VERSION 5.8 ;
BUSBITCHARS "[]" ;
DIVIDERCHAR "/" ;
UNITS
    DATABASE MICRONS 1000 ;
END UNITS

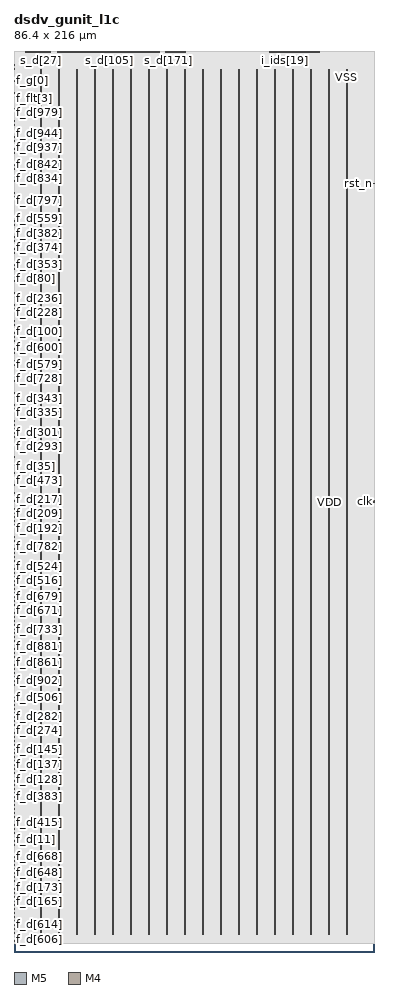
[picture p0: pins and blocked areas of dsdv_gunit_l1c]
MACRO dsdv_gunit_l1c
  FOREIGN dsdv_gunit_l1c 0 0 ;
  CLASS BLOCK ;
  SIZE 86.4 BY 216 ;
  PIN clk
    DIRECTION INPUT ;
    USE SIGNAL ;
    PORT
      LAYER M5 ;
        RECT  86.328 107.772 86.4 108.252 ;
    END
  END clk
  PIN f_d[0]
    DIRECTION INPUT ;
    USE SIGNAL ;
    PORT
      LAYER M4 ;
        RECT  0 24.912 0.084 24.936 ;
    END
  END f_d[0]
  PIN f_d[100]
    DIRECTION INPUT ;
    USE SIGNAL ;
    PORT
      LAYER M4 ;
        RECT  0 147.024 0.084 147.048 ;
    END
  END f_d[100]
  PIN f_d[101]
    DIRECTION INPUT ;
    USE SIGNAL ;
    PORT
      LAYER M4 ;
        RECT  0 147.216 0.084 147.24 ;
    END
  END f_d[101]
  PIN f_d[102]
    DIRECTION INPUT ;
    USE SIGNAL ;
    PORT
      LAYER M4 ;
        RECT  0 147.408 0.084 147.432 ;
    END
  END f_d[102]
  PIN f_d[103]
    DIRECTION INPUT ;
    USE SIGNAL ;
    PORT
      LAYER M4 ;
        RECT  0 147.6 0.084 147.624 ;
    END
  END f_d[103]
  PIN f_d[104]
    DIRECTION INPUT ;
    USE SIGNAL ;
    PORT
      LAYER M4 ;
        RECT  0 147.792 0.084 147.816 ;
    END
  END f_d[104]
  PIN f_d[105]
    DIRECTION INPUT ;
    USE SIGNAL ;
    PORT
      LAYER M4 ;
        RECT  0 147.984 0.084 148.008 ;
    END
  END f_d[105]
  PIN f_d[106]
    DIRECTION INPUT ;
    USE SIGNAL ;
    PORT
      LAYER M4 ;
        RECT  0 148.176 0.084 148.2 ;
    END
  END f_d[106]
  PIN f_d[107]
    DIRECTION INPUT ;
    USE SIGNAL ;
    PORT
      LAYER M4 ;
        RECT  0 148.368 0.084 148.392 ;
    END
  END f_d[107]
  PIN f_d[108]
    DIRECTION INPUT ;
    USE SIGNAL ;
    PORT
      LAYER M4 ;
        RECT  0 148.56 0.084 148.584 ;
    END
  END f_d[108]
  PIN f_d[109]
    DIRECTION INPUT ;
    USE SIGNAL ;
    PORT
      LAYER M4 ;
        RECT  0 148.752 0.084 148.776 ;
    END
  END f_d[109]
  PIN f_d[10]
    DIRECTION INPUT ;
    USE SIGNAL ;
    PORT
      LAYER M4 ;
        RECT  0 26.832 0.084 26.856 ;
    END
  END f_d[10]
  PIN f_d[110]
    DIRECTION INPUT ;
    USE SIGNAL ;
    PORT
      LAYER M4 ;
        RECT  0 148.944 0.084 148.968 ;
    END
  END f_d[110]
  PIN f_d[111]
    DIRECTION INPUT ;
    USE SIGNAL ;
    PORT
      LAYER M4 ;
        RECT  0 149.136 0.084 149.16 ;
    END
  END f_d[111]
  PIN f_d[112]
    DIRECTION INPUT ;
    USE SIGNAL ;
    PORT
      LAYER M4 ;
        RECT  0 149.328 0.084 149.352 ;
    END
  END f_d[112]
  PIN f_d[113]
    DIRECTION INPUT ;
    USE SIGNAL ;
    PORT
      LAYER M4 ;
        RECT  0 149.52 0.084 149.544 ;
    END
  END f_d[113]
  PIN f_d[114]
    DIRECTION INPUT ;
    USE SIGNAL ;
    PORT
      LAYER M4 ;
        RECT  0 149.712 0.084 149.736 ;
    END
  END f_d[114]
  PIN f_d[115]
    DIRECTION INPUT ;
    USE SIGNAL ;
    PORT
      LAYER M4 ;
        RECT  0 149.904 0.084 149.928 ;
    END
  END f_d[115]
  PIN f_d[116]
    DIRECTION INPUT ;
    USE SIGNAL ;
    PORT
      LAYER M4 ;
        RECT  0 150.096 0.084 150.12 ;
    END
  END f_d[116]
  PIN f_d[117]
    DIRECTION INPUT ;
    USE SIGNAL ;
    PORT
      LAYER M4 ;
        RECT  0 150.288 0.084 150.312 ;
    END
  END f_d[117]
  PIN f_d[118]
    DIRECTION INPUT ;
    USE SIGNAL ;
    PORT
      LAYER M4 ;
        RECT  0 150.48 0.084 150.504 ;
    END
  END f_d[118]
  PIN f_d[119]
    DIRECTION INPUT ;
    USE SIGNAL ;
    PORT
      LAYER M4 ;
        RECT  0 150.672 0.084 150.696 ;
    END
  END f_d[119]
  PIN f_d[11]
    DIRECTION INPUT ;
    USE SIGNAL ;
    PORT
      LAYER M4 ;
        RECT  0 27.024 0.084 27.048 ;
    END
  END f_d[11]
  PIN f_d[120]
    DIRECTION INPUT ;
    USE SIGNAL ;
    PORT
      LAYER M4 ;
        RECT  0 150.864 0.084 150.888 ;
    END
  END f_d[120]
  PIN f_d[121]
    DIRECTION INPUT ;
    USE SIGNAL ;
    PORT
      LAYER M4 ;
        RECT  0 151.056 0.084 151.08 ;
    END
  END f_d[121]
  PIN f_d[122]
    DIRECTION INPUT ;
    USE SIGNAL ;
    PORT
      LAYER M4 ;
        RECT  0 151.248 0.084 151.272 ;
    END
  END f_d[122]
  PIN f_d[123]
    DIRECTION INPUT ;
    USE SIGNAL ;
    PORT
      LAYER M4 ;
        RECT  0 151.44 0.084 151.464 ;
    END
  END f_d[123]
  PIN f_d[124]
    DIRECTION INPUT ;
    USE SIGNAL ;
    PORT
      LAYER M4 ;
        RECT  0 151.632 0.084 151.656 ;
    END
  END f_d[124]
  PIN f_d[125]
    DIRECTION INPUT ;
    USE SIGNAL ;
    PORT
      LAYER M4 ;
        RECT  0 151.824 0.084 151.848 ;
    END
  END f_d[125]
  PIN f_d[126]
    DIRECTION INPUT ;
    USE SIGNAL ;
    PORT
      LAYER M4 ;
        RECT  0 152.016 0.084 152.04 ;
    END
  END f_d[126]
  PIN f_d[127]
    DIRECTION INPUT ;
    USE SIGNAL ;
    PORT
      LAYER M4 ;
        RECT  0 152.208 0.084 152.232 ;
    END
  END f_d[127]
  PIN f_d[128]
    DIRECTION INPUT ;
    USE SIGNAL ;
    PORT
      LAYER M4 ;
        RECT  0 43.344 0.084 43.368 ;
    END
  END f_d[128]
  PIN f_d[129]
    DIRECTION INPUT ;
    USE SIGNAL ;
    PORT
      LAYER M4 ;
        RECT  0 43.536 0.084 43.56 ;
    END
  END f_d[129]
  PIN f_d[12]
    DIRECTION INPUT ;
    USE SIGNAL ;
    PORT
      LAYER M4 ;
        RECT  0 27.216 0.084 27.24 ;
    END
  END f_d[12]
  PIN f_d[130]
    DIRECTION INPUT ;
    USE SIGNAL ;
    PORT
      LAYER M4 ;
        RECT  0 43.728 0.084 43.752 ;
    END
  END f_d[130]
  PIN f_d[131]
    DIRECTION INPUT ;
    USE SIGNAL ;
    PORT
      LAYER M4 ;
        RECT  0 43.92 0.084 43.944 ;
    END
  END f_d[131]
  PIN f_d[132]
    DIRECTION INPUT ;
    USE SIGNAL ;
    PORT
      LAYER M4 ;
        RECT  0 44.112 0.084 44.136 ;
    END
  END f_d[132]
  PIN f_d[133]
    DIRECTION INPUT ;
    USE SIGNAL ;
    PORT
      LAYER M4 ;
        RECT  0 44.304 0.084 44.328 ;
    END
  END f_d[133]
  PIN f_d[134]
    DIRECTION INPUT ;
    USE SIGNAL ;
    PORT
      LAYER M4 ;
        RECT  0 44.496 0.084 44.52 ;
    END
  END f_d[134]
  PIN f_d[135]
    DIRECTION INPUT ;
    USE SIGNAL ;
    PORT
      LAYER M4 ;
        RECT  0 44.688 0.084 44.712 ;
    END
  END f_d[135]
  PIN f_d[136]
    DIRECTION INPUT ;
    USE SIGNAL ;
    PORT
      LAYER M4 ;
        RECT  0 44.88 0.084 44.904 ;
    END
  END f_d[136]
  PIN f_d[137]
    DIRECTION INPUT ;
    USE SIGNAL ;
    PORT
      LAYER M4 ;
        RECT  0 45.072 0.084 45.096 ;
    END
  END f_d[137]
  PIN f_d[138]
    DIRECTION INPUT ;
    USE SIGNAL ;
    PORT
      LAYER M4 ;
        RECT  0 45.264 0.084 45.288 ;
    END
  END f_d[138]
  PIN f_d[139]
    DIRECTION INPUT ;
    USE SIGNAL ;
    PORT
      LAYER M4 ;
        RECT  0 45.456 0.084 45.48 ;
    END
  END f_d[139]
  PIN f_d[13]
    DIRECTION INPUT ;
    USE SIGNAL ;
    PORT
      LAYER M4 ;
        RECT  0 27.408 0.084 27.432 ;
    END
  END f_d[13]
  PIN f_d[140]
    DIRECTION INPUT ;
    USE SIGNAL ;
    PORT
      LAYER M4 ;
        RECT  0 45.648 0.084 45.672 ;
    END
  END f_d[140]
  PIN f_d[141]
    DIRECTION INPUT ;
    USE SIGNAL ;
    PORT
      LAYER M4 ;
        RECT  0 45.84 0.084 45.864 ;
    END
  END f_d[141]
  PIN f_d[142]
    DIRECTION INPUT ;
    USE SIGNAL ;
    PORT
      LAYER M4 ;
        RECT  0 46.032 0.084 46.056 ;
    END
  END f_d[142]
  PIN f_d[143]
    DIRECTION INPUT ;
    USE SIGNAL ;
    PORT
      LAYER M4 ;
        RECT  0 46.224 0.084 46.248 ;
    END
  END f_d[143]
  PIN f_d[144]
    DIRECTION INPUT ;
    USE SIGNAL ;
    PORT
      LAYER M4 ;
        RECT  0 46.416 0.084 46.44 ;
    END
  END f_d[144]
  PIN f_d[145]
    DIRECTION INPUT ;
    USE SIGNAL ;
    PORT
      LAYER M4 ;
        RECT  0 46.608 0.084 46.632 ;
    END
  END f_d[145]
  PIN f_d[146]
    DIRECTION INPUT ;
    USE SIGNAL ;
    PORT
      LAYER M4 ;
        RECT  0 46.8 0.084 46.824 ;
    END
  END f_d[146]
  PIN f_d[147]
    DIRECTION INPUT ;
    USE SIGNAL ;
    PORT
      LAYER M4 ;
        RECT  0 46.992 0.084 47.016 ;
    END
  END f_d[147]
  PIN f_d[148]
    DIRECTION INPUT ;
    USE SIGNAL ;
    PORT
      LAYER M4 ;
        RECT  0 47.184 0.084 47.208 ;
    END
  END f_d[148]
  PIN f_d[149]
    DIRECTION INPUT ;
    USE SIGNAL ;
    PORT
      LAYER M4 ;
        RECT  0 47.376 0.084 47.4 ;
    END
  END f_d[149]
  PIN f_d[14]
    DIRECTION INPUT ;
    USE SIGNAL ;
    PORT
      LAYER M4 ;
        RECT  0 27.6 0.084 27.624 ;
    END
  END f_d[14]
  PIN f_d[150]
    DIRECTION INPUT ;
    USE SIGNAL ;
    PORT
      LAYER M4 ;
        RECT  0 47.568 0.084 47.592 ;
    END
  END f_d[150]
  PIN f_d[151]
    DIRECTION INPUT ;
    USE SIGNAL ;
    PORT
      LAYER M4 ;
        RECT  0 47.76 0.084 47.784 ;
    END
  END f_d[151]
  PIN f_d[152]
    DIRECTION INPUT ;
    USE SIGNAL ;
    PORT
      LAYER M4 ;
        RECT  0 47.952 0.084 47.976 ;
    END
  END f_d[152]
  PIN f_d[153]
    DIRECTION INPUT ;
    USE SIGNAL ;
    PORT
      LAYER M4 ;
        RECT  0 48.144 0.084 48.168 ;
    END
  END f_d[153]
  PIN f_d[154]
    DIRECTION INPUT ;
    USE SIGNAL ;
    PORT
      LAYER M4 ;
        RECT  0 48.336 0.084 48.36 ;
    END
  END f_d[154]
  PIN f_d[155]
    DIRECTION INPUT ;
    USE SIGNAL ;
    PORT
      LAYER M4 ;
        RECT  0 48.528 0.084 48.552 ;
    END
  END f_d[155]
  PIN f_d[156]
    DIRECTION INPUT ;
    USE SIGNAL ;
    PORT
      LAYER M4 ;
        RECT  0 48.72 0.084 48.744 ;
    END
  END f_d[156]
  PIN f_d[157]
    DIRECTION INPUT ;
    USE SIGNAL ;
    PORT
      LAYER M4 ;
        RECT  0 48.912 0.084 48.936 ;
    END
  END f_d[157]
  PIN f_d[158]
    DIRECTION INPUT ;
    USE SIGNAL ;
    PORT
      LAYER M4 ;
        RECT  0 49.104 0.084 49.128 ;
    END
  END f_d[158]
  PIN f_d[159]
    DIRECTION INPUT ;
    USE SIGNAL ;
    PORT
      LAYER M4 ;
        RECT  0 49.296 0.084 49.32 ;
    END
  END f_d[159]
  PIN f_d[15]
    DIRECTION INPUT ;
    USE SIGNAL ;
    PORT
      LAYER M4 ;
        RECT  0 27.792 0.084 27.816 ;
    END
  END f_d[15]
  PIN f_d[160]
    DIRECTION INPUT ;
    USE SIGNAL ;
    PORT
      LAYER M4 ;
        RECT  0 11.088 0.084 11.112 ;
    END
  END f_d[160]
  PIN f_d[161]
    DIRECTION INPUT ;
    USE SIGNAL ;
    PORT
      LAYER M4 ;
        RECT  0 11.28 0.084 11.304 ;
    END
  END f_d[161]
  PIN f_d[162]
    DIRECTION INPUT ;
    USE SIGNAL ;
    PORT
      LAYER M4 ;
        RECT  0 11.472 0.084 11.496 ;
    END
  END f_d[162]
  PIN f_d[163]
    DIRECTION INPUT ;
    USE SIGNAL ;
    PORT
      LAYER M4 ;
        RECT  0 11.664 0.084 11.688 ;
    END
  END f_d[163]
  PIN f_d[164]
    DIRECTION INPUT ;
    USE SIGNAL ;
    PORT
      LAYER M4 ;
        RECT  0 11.856 0.084 11.88 ;
    END
  END f_d[164]
  PIN f_d[165]
    DIRECTION INPUT ;
    USE SIGNAL ;
    PORT
      LAYER M4 ;
        RECT  0 12.048 0.084 12.072 ;
    END
  END f_d[165]
  PIN f_d[166]
    DIRECTION INPUT ;
    USE SIGNAL ;
    PORT
      LAYER M4 ;
        RECT  0 12.24 0.084 12.264 ;
    END
  END f_d[166]
  PIN f_d[167]
    DIRECTION INPUT ;
    USE SIGNAL ;
    PORT
      LAYER M4 ;
        RECT  0 12.432 0.084 12.456 ;
    END
  END f_d[167]
  PIN f_d[168]
    DIRECTION INPUT ;
    USE SIGNAL ;
    PORT
      LAYER M4 ;
        RECT  0 12.624 0.084 12.648 ;
    END
  END f_d[168]
  PIN f_d[169]
    DIRECTION INPUT ;
    USE SIGNAL ;
    PORT
      LAYER M4 ;
        RECT  0 12.816 0.084 12.84 ;
    END
  END f_d[169]
  PIN f_d[16]
    DIRECTION INPUT ;
    USE SIGNAL ;
    PORT
      LAYER M4 ;
        RECT  0 27.984 0.084 28.008 ;
    END
  END f_d[16]
  PIN f_d[170]
    DIRECTION INPUT ;
    USE SIGNAL ;
    PORT
      LAYER M4 ;
        RECT  0 13.008 0.084 13.032 ;
    END
  END f_d[170]
  PIN f_d[171]
    DIRECTION INPUT ;
    USE SIGNAL ;
    PORT
      LAYER M4 ;
        RECT  0 13.2 0.084 13.224 ;
    END
  END f_d[171]
  PIN f_d[172]
    DIRECTION INPUT ;
    USE SIGNAL ;
    PORT
      LAYER M4 ;
        RECT  0 13.392 0.084 13.416 ;
    END
  END f_d[172]
  PIN f_d[173]
    DIRECTION INPUT ;
    USE SIGNAL ;
    PORT
      LAYER M4 ;
        RECT  0 13.584 0.084 13.608 ;
    END
  END f_d[173]
  PIN f_d[174]
    DIRECTION INPUT ;
    USE SIGNAL ;
    PORT
      LAYER M4 ;
        RECT  0 13.776 0.084 13.8 ;
    END
  END f_d[174]
  PIN f_d[175]
    DIRECTION INPUT ;
    USE SIGNAL ;
    PORT
      LAYER M4 ;
        RECT  0 13.968 0.084 13.992 ;
    END
  END f_d[175]
  PIN f_d[176]
    DIRECTION INPUT ;
    USE SIGNAL ;
    PORT
      LAYER M4 ;
        RECT  0 14.16 0.084 14.184 ;
    END
  END f_d[176]
  PIN f_d[177]
    DIRECTION INPUT ;
    USE SIGNAL ;
    PORT
      LAYER M4 ;
        RECT  0 14.352 0.084 14.376 ;
    END
  END f_d[177]
  PIN f_d[178]
    DIRECTION INPUT ;
    USE SIGNAL ;
    PORT
      LAYER M4 ;
        RECT  0 14.544 0.084 14.568 ;
    END
  END f_d[178]
  PIN f_d[179]
    DIRECTION INPUT ;
    USE SIGNAL ;
    PORT
      LAYER M4 ;
        RECT  0 14.736 0.084 14.76 ;
    END
  END f_d[179]
  PIN f_d[17]
    DIRECTION INPUT ;
    USE SIGNAL ;
    PORT
      LAYER M4 ;
        RECT  0 28.176 0.084 28.2 ;
    END
  END f_d[17]
  PIN f_d[180]
    DIRECTION INPUT ;
    USE SIGNAL ;
    PORT
      LAYER M4 ;
        RECT  0 14.928 0.084 14.952 ;
    END
  END f_d[180]
  PIN f_d[181]
    DIRECTION INPUT ;
    USE SIGNAL ;
    PORT
      LAYER M4 ;
        RECT  0 15.12 0.084 15.144 ;
    END
  END f_d[181]
  PIN f_d[182]
    DIRECTION INPUT ;
    USE SIGNAL ;
    PORT
      LAYER M4 ;
        RECT  0 15.312 0.084 15.336 ;
    END
  END f_d[182]
  PIN f_d[183]
    DIRECTION INPUT ;
    USE SIGNAL ;
    PORT
      LAYER M4 ;
        RECT  0 15.504 0.084 15.528 ;
    END
  END f_d[183]
  PIN f_d[184]
    DIRECTION INPUT ;
    USE SIGNAL ;
    PORT
      LAYER M4 ;
        RECT  0 15.696 0.084 15.72 ;
    END
  END f_d[184]
  PIN f_d[185]
    DIRECTION INPUT ;
    USE SIGNAL ;
    PORT
      LAYER M4 ;
        RECT  0 15.888 0.084 15.912 ;
    END
  END f_d[185]
  PIN f_d[186]
    DIRECTION INPUT ;
    USE SIGNAL ;
    PORT
      LAYER M4 ;
        RECT  0 16.08 0.084 16.104 ;
    END
  END f_d[186]
  PIN f_d[187]
    DIRECTION INPUT ;
    USE SIGNAL ;
    PORT
      LAYER M4 ;
        RECT  0 16.272 0.084 16.296 ;
    END
  END f_d[187]
  PIN f_d[188]
    DIRECTION INPUT ;
    USE SIGNAL ;
    PORT
      LAYER M4 ;
        RECT  0 16.464 0.084 16.488 ;
    END
  END f_d[188]
  PIN f_d[189]
    DIRECTION INPUT ;
    USE SIGNAL ;
    PORT
      LAYER M4 ;
        RECT  0 16.656 0.084 16.68 ;
    END
  END f_d[189]
  PIN f_d[18]
    DIRECTION INPUT ;
    USE SIGNAL ;
    PORT
      LAYER M4 ;
        RECT  0 28.368 0.084 28.392 ;
    END
  END f_d[18]
  PIN f_d[190]
    DIRECTION INPUT ;
    USE SIGNAL ;
    PORT
      LAYER M4 ;
        RECT  0 16.848 0.084 16.872 ;
    END
  END f_d[190]
  PIN f_d[191]
    DIRECTION INPUT ;
    USE SIGNAL ;
    PORT
      LAYER M4 ;
        RECT  0 17.04 0.084 17.064 ;
    END
  END f_d[191]
  PIN f_d[192]
    DIRECTION INPUT ;
    USE SIGNAL ;
    PORT
      LAYER M4 ;
        RECT  0 101.712 0.084 101.736 ;
    END
  END f_d[192]
  PIN f_d[193]
    DIRECTION INPUT ;
    USE SIGNAL ;
    PORT
      LAYER M4 ;
        RECT  0 101.904 0.084 101.928 ;
    END
  END f_d[193]
  PIN f_d[194]
    DIRECTION INPUT ;
    USE SIGNAL ;
    PORT
      LAYER M4 ;
        RECT  0 102.096 0.084 102.12 ;
    END
  END f_d[194]
  PIN f_d[195]
    DIRECTION INPUT ;
    USE SIGNAL ;
    PORT
      LAYER M4 ;
        RECT  0 102.288 0.084 102.312 ;
    END
  END f_d[195]
  PIN f_d[196]
    DIRECTION INPUT ;
    USE SIGNAL ;
    PORT
      LAYER M4 ;
        RECT  0 102.48 0.084 102.504 ;
    END
  END f_d[196]
  PIN f_d[197]
    DIRECTION INPUT ;
    USE SIGNAL ;
    PORT
      LAYER M4 ;
        RECT  0 102.672 0.084 102.696 ;
    END
  END f_d[197]
  PIN f_d[198]
    DIRECTION INPUT ;
    USE SIGNAL ;
    PORT
      LAYER M4 ;
        RECT  0 102.864 0.084 102.888 ;
    END
  END f_d[198]
  PIN f_d[199]
    DIRECTION INPUT ;
    USE SIGNAL ;
    PORT
      LAYER M4 ;
        RECT  0 103.056 0.084 103.08 ;
    END
  END f_d[199]
  PIN f_d[19]
    DIRECTION INPUT ;
    USE SIGNAL ;
    PORT
      LAYER M4 ;
        RECT  0 28.56 0.084 28.584 ;
    END
  END f_d[19]
  PIN f_d[1]
    DIRECTION INPUT ;
    USE SIGNAL ;
    PORT
      LAYER M4 ;
        RECT  0 25.104 0.084 25.128 ;
    END
  END f_d[1]
  PIN f_d[200]
    DIRECTION INPUT ;
    USE SIGNAL ;
    PORT
      LAYER M4 ;
        RECT  0 103.248 0.084 103.272 ;
    END
  END f_d[200]
  PIN f_d[201]
    DIRECTION INPUT ;
    USE SIGNAL ;
    PORT
      LAYER M4 ;
        RECT  0 103.44 0.084 103.464 ;
    END
  END f_d[201]
  PIN f_d[202]
    DIRECTION INPUT ;
    USE SIGNAL ;
    PORT
      LAYER M4 ;
        RECT  0 103.632 0.084 103.656 ;
    END
  END f_d[202]
  PIN f_d[203]
    DIRECTION INPUT ;
    USE SIGNAL ;
    PORT
      LAYER M4 ;
        RECT  0 103.824 0.084 103.848 ;
    END
  END f_d[203]
  PIN f_d[204]
    DIRECTION INPUT ;
    USE SIGNAL ;
    PORT
      LAYER M4 ;
        RECT  0 104.016 0.084 104.04 ;
    END
  END f_d[204]
  PIN f_d[205]
    DIRECTION INPUT ;
    USE SIGNAL ;
    PORT
      LAYER M4 ;
        RECT  0 104.4 0.084 104.424 ;
    END
  END f_d[205]
  PIN f_d[206]
    DIRECTION INPUT ;
    USE SIGNAL ;
    PORT
      LAYER M4 ;
        RECT  0 104.592 0.084 104.616 ;
    END
  END f_d[206]
  PIN f_d[207]
    DIRECTION INPUT ;
    USE SIGNAL ;
    PORT
      LAYER M4 ;
        RECT  0 104.784 0.084 104.808 ;
    END
  END f_d[207]
  PIN f_d[208]
    DIRECTION INPUT ;
    USE SIGNAL ;
    PORT
      LAYER M4 ;
        RECT  0 104.976 0.084 105 ;
    END
  END f_d[208]
  PIN f_d[209]
    DIRECTION INPUT ;
    USE SIGNAL ;
    PORT
      LAYER M4 ;
        RECT  0 105.168 0.084 105.192 ;
    END
  END f_d[209]
  PIN f_d[20]
    DIRECTION INPUT ;
    USE SIGNAL ;
    PORT
      LAYER M4 ;
        RECT  0 28.752 0.084 28.776 ;
    END
  END f_d[20]
  PIN f_d[210]
    DIRECTION INPUT ;
    USE SIGNAL ;
    PORT
      LAYER M4 ;
        RECT  0 105.36 0.084 105.384 ;
    END
  END f_d[210]
  PIN f_d[211]
    DIRECTION INPUT ;
    USE SIGNAL ;
    PORT
      LAYER M4 ;
        RECT  0 105.552 0.084 105.576 ;
    END
  END f_d[211]
  PIN f_d[212]
    DIRECTION INPUT ;
    USE SIGNAL ;
    PORT
      LAYER M4 ;
        RECT  0 105.744 0.084 105.768 ;
    END
  END f_d[212]
  PIN f_d[213]
    DIRECTION INPUT ;
    USE SIGNAL ;
    PORT
      LAYER M4 ;
        RECT  0 105.936 0.084 105.96 ;
    END
  END f_d[213]
  PIN f_d[214]
    DIRECTION INPUT ;
    USE SIGNAL ;
    PORT
      LAYER M4 ;
        RECT  0 106.128 0.084 106.152 ;
    END
  END f_d[214]
  PIN f_d[215]
    DIRECTION INPUT ;
    USE SIGNAL ;
    PORT
      LAYER M4 ;
        RECT  0 106.32 0.084 106.344 ;
    END
  END f_d[215]
  PIN f_d[216]
    DIRECTION INPUT ;
    USE SIGNAL ;
    PORT
      LAYER M4 ;
        RECT  0 106.512 0.084 106.536 ;
    END
  END f_d[216]
  PIN f_d[217]
    DIRECTION INPUT ;
    USE SIGNAL ;
    PORT
      LAYER M4 ;
        RECT  0 106.704 0.084 106.728 ;
    END
  END f_d[217]
  PIN f_d[218]
    DIRECTION INPUT ;
    USE SIGNAL ;
    PORT
      LAYER M4 ;
        RECT  0 106.896 0.084 106.92 ;
    END
  END f_d[218]
  PIN f_d[219]
    DIRECTION INPUT ;
    USE SIGNAL ;
    PORT
      LAYER M4 ;
        RECT  0 107.088 0.084 107.112 ;
    END
  END f_d[219]
  PIN f_d[21]
    DIRECTION INPUT ;
    USE SIGNAL ;
    PORT
      LAYER M4 ;
        RECT  0 28.944 0.084 28.968 ;
    END
  END f_d[21]
  PIN f_d[220]
    DIRECTION INPUT ;
    USE SIGNAL ;
    PORT
      LAYER M4 ;
        RECT  0 107.28 0.084 107.304 ;
    END
  END f_d[220]
  PIN f_d[221]
    DIRECTION INPUT ;
    USE SIGNAL ;
    PORT
      LAYER M4 ;
        RECT  0 107.472 0.084 107.496 ;
    END
  END f_d[221]
  PIN f_d[222]
    DIRECTION INPUT ;
    USE SIGNAL ;
    PORT
      LAYER M4 ;
        RECT  0 107.664 0.084 107.688 ;
    END
  END f_d[222]
  PIN f_d[223]
    DIRECTION INPUT ;
    USE SIGNAL ;
    PORT
      LAYER M4 ;
        RECT  0 152.4 0.084 152.424 ;
    END
  END f_d[223]
  PIN f_d[224]
    DIRECTION INPUT ;
    USE SIGNAL ;
    PORT
      LAYER M4 ;
        RECT  0 152.592 0.084 152.616 ;
    END
  END f_d[224]
  PIN f_d[225]
    DIRECTION INPUT ;
    USE SIGNAL ;
    PORT
      LAYER M4 ;
        RECT  0 152.784 0.084 152.808 ;
    END
  END f_d[225]
  PIN f_d[226]
    DIRECTION INPUT ;
    USE SIGNAL ;
    PORT
      LAYER M4 ;
        RECT  0 152.976 0.084 153 ;
    END
  END f_d[226]
  PIN f_d[227]
    DIRECTION INPUT ;
    USE SIGNAL ;
    PORT
      LAYER M4 ;
        RECT  0 153.168 0.084 153.192 ;
    END
  END f_d[227]
  PIN f_d[228]
    DIRECTION INPUT ;
    USE SIGNAL ;
    PORT
      LAYER M4 ;
        RECT  0 153.36 0.084 153.384 ;
    END
  END f_d[228]
  PIN f_d[229]
    DIRECTION INPUT ;
    USE SIGNAL ;
    PORT
      LAYER M4 ;
        RECT  0 153.552 0.084 153.576 ;
    END
  END f_d[229]
  PIN f_d[22]
    DIRECTION INPUT ;
    USE SIGNAL ;
    PORT
      LAYER M4 ;
        RECT  0 29.136 0.084 29.16 ;
    END
  END f_d[22]
  PIN f_d[230]
    DIRECTION INPUT ;
    USE SIGNAL ;
    PORT
      LAYER M4 ;
        RECT  0 153.744 0.084 153.768 ;
    END
  END f_d[230]
  PIN f_d[231]
    DIRECTION INPUT ;
    USE SIGNAL ;
    PORT
      LAYER M4 ;
        RECT  0 153.936 0.084 153.96 ;
    END
  END f_d[231]
  PIN f_d[232]
    DIRECTION INPUT ;
    USE SIGNAL ;
    PORT
      LAYER M4 ;
        RECT  0 154.128 0.084 154.152 ;
    END
  END f_d[232]
  PIN f_d[233]
    DIRECTION INPUT ;
    USE SIGNAL ;
    PORT
      LAYER M4 ;
        RECT  0 154.32 0.084 154.344 ;
    END
  END f_d[233]
  PIN f_d[234]
    DIRECTION INPUT ;
    USE SIGNAL ;
    PORT
      LAYER M4 ;
        RECT  0 154.512 0.084 154.536 ;
    END
  END f_d[234]
  PIN f_d[235]
    DIRECTION INPUT ;
    USE SIGNAL ;
    PORT
      LAYER M4 ;
        RECT  0 154.704 0.084 154.728 ;
    END
  END f_d[235]
  PIN f_d[236]
    DIRECTION INPUT ;
    USE SIGNAL ;
    PORT
      LAYER M4 ;
        RECT  0 154.896 0.084 154.92 ;
    END
  END f_d[236]
  PIN f_d[237]
    DIRECTION INPUT ;
    USE SIGNAL ;
    PORT
      LAYER M4 ;
        RECT  0 155.088 0.084 155.112 ;
    END
  END f_d[237]
  PIN f_d[238]
    DIRECTION INPUT ;
    USE SIGNAL ;
    PORT
      LAYER M4 ;
        RECT  0 155.28 0.084 155.304 ;
    END
  END f_d[238]
  PIN f_d[239]
    DIRECTION INPUT ;
    USE SIGNAL ;
    PORT
      LAYER M4 ;
        RECT  0 155.472 0.084 155.496 ;
    END
  END f_d[239]
  PIN f_d[23]
    DIRECTION INPUT ;
    USE SIGNAL ;
    PORT
      LAYER M4 ;
        RECT  0 29.328 0.084 29.352 ;
    END
  END f_d[23]
  PIN f_d[240]
    DIRECTION INPUT ;
    USE SIGNAL ;
    PORT
      LAYER M4 ;
        RECT  0 155.664 0.084 155.688 ;
    END
  END f_d[240]
  PIN f_d[241]
    DIRECTION INPUT ;
    USE SIGNAL ;
    PORT
      LAYER M4 ;
        RECT  0 155.856 0.084 155.88 ;
    END
  END f_d[241]
  PIN f_d[242]
    DIRECTION INPUT ;
    USE SIGNAL ;
    PORT
      LAYER M4 ;
        RECT  0 156.048 0.084 156.072 ;
    END
  END f_d[242]
  PIN f_d[243]
    DIRECTION INPUT ;
    USE SIGNAL ;
    PORT
      LAYER M4 ;
        RECT  0 156.24 0.084 156.264 ;
    END
  END f_d[243]
  PIN f_d[244]
    DIRECTION INPUT ;
    USE SIGNAL ;
    PORT
      LAYER M4 ;
        RECT  0 156.432 0.084 156.456 ;
    END
  END f_d[244]
  PIN f_d[245]
    DIRECTION INPUT ;
    USE SIGNAL ;
    PORT
      LAYER M4 ;
        RECT  0 156.624 0.084 156.648 ;
    END
  END f_d[245]
  PIN f_d[246]
    DIRECTION INPUT ;
    USE SIGNAL ;
    PORT
      LAYER M4 ;
        RECT  0 156.816 0.084 156.84 ;
    END
  END f_d[246]
  PIN f_d[247]
    DIRECTION INPUT ;
    USE SIGNAL ;
    PORT
      LAYER M4 ;
        RECT  0 157.008 0.084 157.032 ;
    END
  END f_d[247]
  PIN f_d[248]
    DIRECTION INPUT ;
    USE SIGNAL ;
    PORT
      LAYER M4 ;
        RECT  0 157.2 0.084 157.224 ;
    END
  END f_d[248]
  PIN f_d[249]
    DIRECTION INPUT ;
    USE SIGNAL ;
    PORT
      LAYER M4 ;
        RECT  0 157.392 0.084 157.416 ;
    END
  END f_d[249]
  PIN f_d[24]
    DIRECTION INPUT ;
    USE SIGNAL ;
    PORT
      LAYER M4 ;
        RECT  0 29.52 0.084 29.544 ;
    END
  END f_d[24]
  PIN f_d[250]
    DIRECTION INPUT ;
    USE SIGNAL ;
    PORT
      LAYER M4 ;
        RECT  0 157.584 0.084 157.608 ;
    END
  END f_d[250]
  PIN f_d[251]
    DIRECTION INPUT ;
    USE SIGNAL ;
    PORT
      LAYER M4 ;
        RECT  0 157.776 0.084 157.8 ;
    END
  END f_d[251]
  PIN f_d[252]
    DIRECTION INPUT ;
    USE SIGNAL ;
    PORT
      LAYER M4 ;
        RECT  0 157.968 0.084 157.992 ;
    END
  END f_d[252]
  PIN f_d[253]
    DIRECTION INPUT ;
    USE SIGNAL ;
    PORT
      LAYER M4 ;
        RECT  0 158.16 0.084 158.184 ;
    END
  END f_d[253]
  PIN f_d[254]
    DIRECTION INPUT ;
    USE SIGNAL ;
    PORT
      LAYER M4 ;
        RECT  0 158.352 0.084 158.376 ;
    END
  END f_d[254]
  PIN f_d[255]
    DIRECTION INPUT ;
    USE SIGNAL ;
    PORT
      LAYER M4 ;
        RECT  0 49.488 0.084 49.512 ;
    END
  END f_d[255]
  PIN f_d[256]
    DIRECTION INPUT ;
    USE SIGNAL ;
    PORT
      LAYER M4 ;
        RECT  0 49.68 0.084 49.704 ;
    END
  END f_d[256]
  PIN f_d[257]
    DIRECTION INPUT ;
    USE SIGNAL ;
    PORT
      LAYER M4 ;
        RECT  0 49.872 0.084 49.896 ;
    END
  END f_d[257]
  PIN f_d[258]
    DIRECTION INPUT ;
    USE SIGNAL ;
    PORT
      LAYER M4 ;
        RECT  0 50.064 0.084 50.088 ;
    END
  END f_d[258]
  PIN f_d[259]
    DIRECTION INPUT ;
    USE SIGNAL ;
    PORT
      LAYER M4 ;
        RECT  0 50.256 0.084 50.28 ;
    END
  END f_d[259]
  PIN f_d[25]
    DIRECTION INPUT ;
    USE SIGNAL ;
    PORT
      LAYER M4 ;
        RECT  0 29.712 0.084 29.736 ;
    END
  END f_d[25]
  PIN f_d[260]
    DIRECTION INPUT ;
    USE SIGNAL ;
    PORT
      LAYER M4 ;
        RECT  0 50.448 0.084 50.472 ;
    END
  END f_d[260]
  PIN f_d[261]
    DIRECTION INPUT ;
    USE SIGNAL ;
    PORT
      LAYER M4 ;
        RECT  0 50.64 0.084 50.664 ;
    END
  END f_d[261]
  PIN f_d[262]
    DIRECTION INPUT ;
    USE SIGNAL ;
    PORT
      LAYER M4 ;
        RECT  0 50.832 0.084 50.856 ;
    END
  END f_d[262]
  PIN f_d[263]
    DIRECTION INPUT ;
    USE SIGNAL ;
    PORT
      LAYER M4 ;
        RECT  0 51.024 0.084 51.048 ;
    END
  END f_d[263]
  PIN f_d[264]
    DIRECTION INPUT ;
    USE SIGNAL ;
    PORT
      LAYER M4 ;
        RECT  0 51.216 0.084 51.24 ;
    END
  END f_d[264]
  PIN f_d[265]
    DIRECTION INPUT ;
    USE SIGNAL ;
    PORT
      LAYER M4 ;
        RECT  0 51.408 0.084 51.432 ;
    END
  END f_d[265]
  PIN f_d[266]
    DIRECTION INPUT ;
    USE SIGNAL ;
    PORT
      LAYER M4 ;
        RECT  0 51.6 0.084 51.624 ;
    END
  END f_d[266]
  PIN f_d[267]
    DIRECTION INPUT ;
    USE SIGNAL ;
    PORT
      LAYER M4 ;
        RECT  0 51.792 0.084 51.816 ;
    END
  END f_d[267]
  PIN f_d[268]
    DIRECTION INPUT ;
    USE SIGNAL ;
    PORT
      LAYER M4 ;
        RECT  0 51.984 0.084 52.008 ;
    END
  END f_d[268]
  PIN f_d[269]
    DIRECTION INPUT ;
    USE SIGNAL ;
    PORT
      LAYER M4 ;
        RECT  0 52.176 0.084 52.2 ;
    END
  END f_d[269]
  PIN f_d[26]
    DIRECTION INPUT ;
    USE SIGNAL ;
    PORT
      LAYER M4 ;
        RECT  0 29.904 0.084 29.928 ;
    END
  END f_d[26]
  PIN f_d[270]
    DIRECTION INPUT ;
    USE SIGNAL ;
    PORT
      LAYER M4 ;
        RECT  0 52.368 0.084 52.392 ;
    END
  END f_d[270]
  PIN f_d[271]
    DIRECTION INPUT ;
    USE SIGNAL ;
    PORT
      LAYER M4 ;
        RECT  0 52.56 0.084 52.584 ;
    END
  END f_d[271]
  PIN f_d[272]
    DIRECTION INPUT ;
    USE SIGNAL ;
    PORT
      LAYER M4 ;
        RECT  0 52.752 0.084 52.776 ;
    END
  END f_d[272]
  PIN f_d[273]
    DIRECTION INPUT ;
    USE SIGNAL ;
    PORT
      LAYER M4 ;
        RECT  0 52.944 0.084 52.968 ;
    END
  END f_d[273]
  PIN f_d[274]
    DIRECTION INPUT ;
    USE SIGNAL ;
    PORT
      LAYER M4 ;
        RECT  0 53.136 0.084 53.16 ;
    END
  END f_d[274]
  PIN f_d[275]
    DIRECTION INPUT ;
    USE SIGNAL ;
    PORT
      LAYER M4 ;
        RECT  0 53.328 0.084 53.352 ;
    END
  END f_d[275]
  PIN f_d[276]
    DIRECTION INPUT ;
    USE SIGNAL ;
    PORT
      LAYER M4 ;
        RECT  0 53.52 0.084 53.544 ;
    END
  END f_d[276]
  PIN f_d[277]
    DIRECTION INPUT ;
    USE SIGNAL ;
    PORT
      LAYER M4 ;
        RECT  0 53.712 0.084 53.736 ;
    END
  END f_d[277]
  PIN f_d[278]
    DIRECTION INPUT ;
    USE SIGNAL ;
    PORT
      LAYER M4 ;
        RECT  0 53.904 0.084 53.928 ;
    END
  END f_d[278]
  PIN f_d[279]
    DIRECTION INPUT ;
    USE SIGNAL ;
    PORT
      LAYER M4 ;
        RECT  0 54.096 0.084 54.12 ;
    END
  END f_d[279]
  PIN f_d[27]
    DIRECTION INPUT ;
    USE SIGNAL ;
    PORT
      LAYER M4 ;
        RECT  0 30.096 0.084 30.12 ;
    END
  END f_d[27]
  PIN f_d[280]
    DIRECTION INPUT ;
    USE SIGNAL ;
    PORT
      LAYER M4 ;
        RECT  0 54.288 0.084 54.312 ;
    END
  END f_d[280]
  PIN f_d[281]
    DIRECTION INPUT ;
    USE SIGNAL ;
    PORT
      LAYER M4 ;
        RECT  0 54.48 0.084 54.504 ;
    END
  END f_d[281]
  PIN f_d[282]
    DIRECTION INPUT ;
    USE SIGNAL ;
    PORT
      LAYER M4 ;
        RECT  0 54.672 0.084 54.696 ;
    END
  END f_d[282]
  PIN f_d[283]
    DIRECTION INPUT ;
    USE SIGNAL ;
    PORT
      LAYER M4 ;
        RECT  0 54.864 0.084 54.888 ;
    END
  END f_d[283]
  PIN f_d[284]
    DIRECTION INPUT ;
    USE SIGNAL ;
    PORT
      LAYER M4 ;
        RECT  0 55.056 0.084 55.08 ;
    END
  END f_d[284]
  PIN f_d[285]
    DIRECTION INPUT ;
    USE SIGNAL ;
    PORT
      LAYER M4 ;
        RECT  0 55.248 0.084 55.272 ;
    END
  END f_d[285]
  PIN f_d[286]
    DIRECTION INPUT ;
    USE SIGNAL ;
    PORT
      LAYER M4 ;
        RECT  0 55.44 0.084 55.464 ;
    END
  END f_d[286]
  PIN f_d[287]
    DIRECTION INPUT ;
    USE SIGNAL ;
    PORT
      LAYER M4 ;
        RECT  0 120.144 0.084 120.168 ;
    END
  END f_d[287]
  PIN f_d[288]
    DIRECTION INPUT ;
    USE SIGNAL ;
    PORT
      LAYER M4 ;
        RECT  0 120.336 0.084 120.36 ;
    END
  END f_d[288]
  PIN f_d[289]
    DIRECTION INPUT ;
    USE SIGNAL ;
    PORT
      LAYER M4 ;
        RECT  0 120.528 0.084 120.552 ;
    END
  END f_d[289]
  PIN f_d[28]
    DIRECTION INPUT ;
    USE SIGNAL ;
    PORT
      LAYER M4 ;
        RECT  0 30.288 0.084 30.312 ;
    END
  END f_d[28]
  PIN f_d[290]
    DIRECTION INPUT ;
    USE SIGNAL ;
    PORT
      LAYER M4 ;
        RECT  0 120.72 0.084 120.744 ;
    END
  END f_d[290]
  PIN f_d[291]
    DIRECTION INPUT ;
    USE SIGNAL ;
    PORT
      LAYER M4 ;
        RECT  0 120.912 0.084 120.936 ;
    END
  END f_d[291]
  PIN f_d[292]
    DIRECTION INPUT ;
    USE SIGNAL ;
    PORT
      LAYER M4 ;
        RECT  0 121.104 0.084 121.128 ;
    END
  END f_d[292]
  PIN f_d[293]
    DIRECTION INPUT ;
    USE SIGNAL ;
    PORT
      LAYER M4 ;
        RECT  0 121.296 0.084 121.32 ;
    END
  END f_d[293]
  PIN f_d[294]
    DIRECTION INPUT ;
    USE SIGNAL ;
    PORT
      LAYER M4 ;
        RECT  0 121.488 0.084 121.512 ;
    END
  END f_d[294]
  PIN f_d[295]
    DIRECTION INPUT ;
    USE SIGNAL ;
    PORT
      LAYER M4 ;
        RECT  0 121.68 0.084 121.704 ;
    END
  END f_d[295]
  PIN f_d[296]
    DIRECTION INPUT ;
    USE SIGNAL ;
    PORT
      LAYER M4 ;
        RECT  0 121.872 0.084 121.896 ;
    END
  END f_d[296]
  PIN f_d[297]
    DIRECTION INPUT ;
    USE SIGNAL ;
    PORT
      LAYER M4 ;
        RECT  0 122.064 0.084 122.088 ;
    END
  END f_d[297]
  PIN f_d[298]
    DIRECTION INPUT ;
    USE SIGNAL ;
    PORT
      LAYER M4 ;
        RECT  0 122.256 0.084 122.28 ;
    END
  END f_d[298]
  PIN f_d[299]
    DIRECTION INPUT ;
    USE SIGNAL ;
    PORT
      LAYER M4 ;
        RECT  0 122.448 0.084 122.472 ;
    END
  END f_d[299]
  PIN f_d[29]
    DIRECTION INPUT ;
    USE SIGNAL ;
    PORT
      LAYER M4 ;
        RECT  0 30.48 0.084 30.504 ;
    END
  END f_d[29]
  PIN f_d[2]
    DIRECTION INPUT ;
    USE SIGNAL ;
    PORT
      LAYER M4 ;
        RECT  0 25.296 0.084 25.32 ;
    END
  END f_d[2]
  PIN f_d[300]
    DIRECTION INPUT ;
    USE SIGNAL ;
    PORT
      LAYER M4 ;
        RECT  0 122.64 0.084 122.664 ;
    END
  END f_d[300]
  PIN f_d[301]
    DIRECTION INPUT ;
    USE SIGNAL ;
    PORT
      LAYER M4 ;
        RECT  0 122.832 0.084 122.856 ;
    END
  END f_d[301]
  PIN f_d[302]
    DIRECTION INPUT ;
    USE SIGNAL ;
    PORT
      LAYER M4 ;
        RECT  0 123.024 0.084 123.048 ;
    END
  END f_d[302]
  PIN f_d[303]
    DIRECTION INPUT ;
    USE SIGNAL ;
    PORT
      LAYER M4 ;
        RECT  0 123.216 0.084 123.24 ;
    END
  END f_d[303]
  PIN f_d[304]
    DIRECTION INPUT ;
    USE SIGNAL ;
    PORT
      LAYER M4 ;
        RECT  0 123.408 0.084 123.432 ;
    END
  END f_d[304]
  PIN f_d[305]
    DIRECTION INPUT ;
    USE SIGNAL ;
    PORT
      LAYER M4 ;
        RECT  0 123.6 0.084 123.624 ;
    END
  END f_d[305]
  PIN f_d[306]
    DIRECTION INPUT ;
    USE SIGNAL ;
    PORT
      LAYER M4 ;
        RECT  0 123.792 0.084 123.816 ;
    END
  END f_d[306]
  PIN f_d[307]
    DIRECTION INPUT ;
    USE SIGNAL ;
    PORT
      LAYER M4 ;
        RECT  0 123.984 0.084 124.008 ;
    END
  END f_d[307]
  PIN f_d[308]
    DIRECTION INPUT ;
    USE SIGNAL ;
    PORT
      LAYER M4 ;
        RECT  0 124.176 0.084 124.2 ;
    END
  END f_d[308]
  PIN f_d[309]
    DIRECTION INPUT ;
    USE SIGNAL ;
    PORT
      LAYER M4 ;
        RECT  0 124.368 0.084 124.392 ;
    END
  END f_d[309]
  PIN f_d[30]
    DIRECTION INPUT ;
    USE SIGNAL ;
    PORT
      LAYER M4 ;
        RECT  0 30.672 0.084 30.696 ;
    END
  END f_d[30]
  PIN f_d[310]
    DIRECTION INPUT ;
    USE SIGNAL ;
    PORT
      LAYER M4 ;
        RECT  0 124.56 0.084 124.584 ;
    END
  END f_d[310]
  PIN f_d[311]
    DIRECTION INPUT ;
    USE SIGNAL ;
    PORT
      LAYER M4 ;
        RECT  0 124.752 0.084 124.776 ;
    END
  END f_d[311]
  PIN f_d[312]
    DIRECTION INPUT ;
    USE SIGNAL ;
    PORT
      LAYER M4 ;
        RECT  0 124.944 0.084 124.968 ;
    END
  END f_d[312]
  PIN f_d[313]
    DIRECTION INPUT ;
    USE SIGNAL ;
    PORT
      LAYER M4 ;
        RECT  0 125.136 0.084 125.16 ;
    END
  END f_d[313]
  PIN f_d[314]
    DIRECTION INPUT ;
    USE SIGNAL ;
    PORT
      LAYER M4 ;
        RECT  0 125.328 0.084 125.352 ;
    END
  END f_d[314]
  PIN f_d[315]
    DIRECTION INPUT ;
    USE SIGNAL ;
    PORT
      LAYER M4 ;
        RECT  0 125.52 0.084 125.544 ;
    END
  END f_d[315]
  PIN f_d[316]
    DIRECTION INPUT ;
    USE SIGNAL ;
    PORT
      LAYER M4 ;
        RECT  0 125.712 0.084 125.736 ;
    END
  END f_d[316]
  PIN f_d[317]
    DIRECTION INPUT ;
    USE SIGNAL ;
    PORT
      LAYER M4 ;
        RECT  0 125.904 0.084 125.928 ;
    END
  END f_d[317]
  PIN f_d[318]
    DIRECTION INPUT ;
    USE SIGNAL ;
    PORT
      LAYER M4 ;
        RECT  0 126.096 0.084 126.12 ;
    END
  END f_d[318]
  PIN f_d[319]
    DIRECTION INPUT ;
    USE SIGNAL ;
    PORT
      LAYER M4 ;
        RECT  0 126.288 0.084 126.312 ;
    END
  END f_d[319]
  PIN f_d[31]
    DIRECTION INPUT ;
    USE SIGNAL ;
    PORT
      LAYER M4 ;
        RECT  0 30.864 0.084 30.888 ;
    END
  END f_d[31]
  PIN f_d[320]
    DIRECTION INPUT ;
    USE SIGNAL ;
    PORT
      LAYER M4 ;
        RECT  0 126.48 0.084 126.504 ;
    END
  END f_d[320]
  PIN f_d[321]
    DIRECTION INPUT ;
    USE SIGNAL ;
    PORT
      LAYER M4 ;
        RECT  0 126.672 0.084 126.696 ;
    END
  END f_d[321]
  PIN f_d[322]
    DIRECTION INPUT ;
    USE SIGNAL ;
    PORT
      LAYER M4 ;
        RECT  0 126.864 0.084 126.888 ;
    END
  END f_d[322]
  PIN f_d[323]
    DIRECTION INPUT ;
    USE SIGNAL ;
    PORT
      LAYER M4 ;
        RECT  0 127.056 0.084 127.08 ;
    END
  END f_d[323]
  PIN f_d[324]
    DIRECTION INPUT ;
    USE SIGNAL ;
    PORT
      LAYER M4 ;
        RECT  0 127.248 0.084 127.272 ;
    END
  END f_d[324]
  PIN f_d[325]
    DIRECTION INPUT ;
    USE SIGNAL ;
    PORT
      LAYER M4 ;
        RECT  0 127.44 0.084 127.464 ;
    END
  END f_d[325]
  PIN f_d[326]
    DIRECTION INPUT ;
    USE SIGNAL ;
    PORT
      LAYER M4 ;
        RECT  0 127.632 0.084 127.656 ;
    END
  END f_d[326]
  PIN f_d[327]
    DIRECTION INPUT ;
    USE SIGNAL ;
    PORT
      LAYER M4 ;
        RECT  0 127.824 0.084 127.848 ;
    END
  END f_d[327]
  PIN f_d[328]
    DIRECTION INPUT ;
    USE SIGNAL ;
    PORT
      LAYER M4 ;
        RECT  0 128.016 0.084 128.04 ;
    END
  END f_d[328]
  PIN f_d[329]
    DIRECTION INPUT ;
    USE SIGNAL ;
    PORT
      LAYER M4 ;
        RECT  0 128.208 0.084 128.232 ;
    END
  END f_d[329]
  PIN f_d[32]
    DIRECTION INPUT ;
    USE SIGNAL ;
    PORT
      LAYER M4 ;
        RECT  0 114 0.084 114.024 ;
    END
  END f_d[32]
  PIN f_d[330]
    DIRECTION INPUT ;
    USE SIGNAL ;
    PORT
      LAYER M4 ;
        RECT  0 128.4 0.084 128.424 ;
    END
  END f_d[330]
  PIN f_d[331]
    DIRECTION INPUT ;
    USE SIGNAL ;
    PORT
      LAYER M4 ;
        RECT  0 128.592 0.084 128.616 ;
    END
  END f_d[331]
  PIN f_d[332]
    DIRECTION INPUT ;
    USE SIGNAL ;
    PORT
      LAYER M4 ;
        RECT  0 128.784 0.084 128.808 ;
    END
  END f_d[332]
  PIN f_d[333]
    DIRECTION INPUT ;
    USE SIGNAL ;
    PORT
      LAYER M4 ;
        RECT  0 128.976 0.084 129 ;
    END
  END f_d[333]
  PIN f_d[334]
    DIRECTION INPUT ;
    USE SIGNAL ;
    PORT
      LAYER M4 ;
        RECT  0 129.168 0.084 129.192 ;
    END
  END f_d[334]
  PIN f_d[335]
    DIRECTION INPUT ;
    USE SIGNAL ;
    PORT
      LAYER M4 ;
        RECT  0 129.36 0.084 129.384 ;
    END
  END f_d[335]
  PIN f_d[336]
    DIRECTION INPUT ;
    USE SIGNAL ;
    PORT
      LAYER M4 ;
        RECT  0 129.552 0.084 129.576 ;
    END
  END f_d[336]
  PIN f_d[337]
    DIRECTION INPUT ;
    USE SIGNAL ;
    PORT
      LAYER M4 ;
        RECT  0 129.744 0.084 129.768 ;
    END
  END f_d[337]
  PIN f_d[338]
    DIRECTION INPUT ;
    USE SIGNAL ;
    PORT
      LAYER M4 ;
        RECT  0 129.936 0.084 129.96 ;
    END
  END f_d[338]
  PIN f_d[339]
    DIRECTION INPUT ;
    USE SIGNAL ;
    PORT
      LAYER M4 ;
        RECT  0 130.128 0.084 130.152 ;
    END
  END f_d[339]
  PIN f_d[33]
    DIRECTION INPUT ;
    USE SIGNAL ;
    PORT
      LAYER M4 ;
        RECT  0 114.192 0.084 114.216 ;
    END
  END f_d[33]
  PIN f_d[340]
    DIRECTION INPUT ;
    USE SIGNAL ;
    PORT
      LAYER M4 ;
        RECT  0 130.32 0.084 130.344 ;
    END
  END f_d[340]
  PIN f_d[341]
    DIRECTION INPUT ;
    USE SIGNAL ;
    PORT
      LAYER M4 ;
        RECT  0 130.512 0.084 130.536 ;
    END
  END f_d[341]
  PIN f_d[342]
    DIRECTION INPUT ;
    USE SIGNAL ;
    PORT
      LAYER M4 ;
        RECT  0 130.704 0.084 130.728 ;
    END
  END f_d[342]
  PIN f_d[343]
    DIRECTION INPUT ;
    USE SIGNAL ;
    PORT
      LAYER M4 ;
        RECT  0 130.896 0.084 130.92 ;
    END
  END f_d[343]
  PIN f_d[344]
    DIRECTION INPUT ;
    USE SIGNAL ;
    PORT
      LAYER M4 ;
        RECT  0 131.088 0.084 131.112 ;
    END
  END f_d[344]
  PIN f_d[345]
    DIRECTION INPUT ;
    USE SIGNAL ;
    PORT
      LAYER M4 ;
        RECT  0 131.28 0.084 131.304 ;
    END
  END f_d[345]
  PIN f_d[346]
    DIRECTION INPUT ;
    USE SIGNAL ;
    PORT
      LAYER M4 ;
        RECT  0 131.472 0.084 131.496 ;
    END
  END f_d[346]
  PIN f_d[347]
    DIRECTION INPUT ;
    USE SIGNAL ;
    PORT
      LAYER M4 ;
        RECT  0 131.664 0.084 131.688 ;
    END
  END f_d[347]
  PIN f_d[348]
    DIRECTION INPUT ;
    USE SIGNAL ;
    PORT
      LAYER M4 ;
        RECT  0 131.856 0.084 131.88 ;
    END
  END f_d[348]
  PIN f_d[349]
    DIRECTION INPUT ;
    USE SIGNAL ;
    PORT
      LAYER M4 ;
        RECT  0 132.048 0.084 132.072 ;
    END
  END f_d[349]
  PIN f_d[34]
    DIRECTION INPUT ;
    USE SIGNAL ;
    PORT
      LAYER M4 ;
        RECT  0 114.384 0.084 114.408 ;
    END
  END f_d[34]
  PIN f_d[350]
    DIRECTION INPUT ;
    USE SIGNAL ;
    PORT
      LAYER M4 ;
        RECT  0 132.24 0.084 132.264 ;
    END
  END f_d[350]
  PIN f_d[351]
    DIRECTION INPUT ;
    USE SIGNAL ;
    PORT
      LAYER M4 ;
        RECT  0 164.688 0.084 164.712 ;
    END
  END f_d[351]
  PIN f_d[352]
    DIRECTION INPUT ;
    USE SIGNAL ;
    PORT
      LAYER M4 ;
        RECT  0 164.88 0.084 164.904 ;
    END
  END f_d[352]
  PIN f_d[353]
    DIRECTION INPUT ;
    USE SIGNAL ;
    PORT
      LAYER M4 ;
        RECT  0 165.072 0.084 165.096 ;
    END
  END f_d[353]
  PIN f_d[354]
    DIRECTION INPUT ;
    USE SIGNAL ;
    PORT
      LAYER M4 ;
        RECT  0 165.264 0.084 165.288 ;
    END
  END f_d[354]
  PIN f_d[355]
    DIRECTION INPUT ;
    USE SIGNAL ;
    PORT
      LAYER M4 ;
        RECT  0 165.456 0.084 165.48 ;
    END
  END f_d[355]
  PIN f_d[356]
    DIRECTION INPUT ;
    USE SIGNAL ;
    PORT
      LAYER M4 ;
        RECT  0 165.648 0.084 165.672 ;
    END
  END f_d[356]
  PIN f_d[357]
    DIRECTION INPUT ;
    USE SIGNAL ;
    PORT
      LAYER M4 ;
        RECT  0 165.84 0.084 165.864 ;
    END
  END f_d[357]
  PIN f_d[358]
    DIRECTION INPUT ;
    USE SIGNAL ;
    PORT
      LAYER M4 ;
        RECT  0 166.032 0.084 166.056 ;
    END
  END f_d[358]
  PIN f_d[359]
    DIRECTION INPUT ;
    USE SIGNAL ;
    PORT
      LAYER M4 ;
        RECT  0 166.224 0.084 166.248 ;
    END
  END f_d[359]
  PIN f_d[35]
    DIRECTION INPUT ;
    USE SIGNAL ;
    PORT
      LAYER M4 ;
        RECT  0 114.576 0.084 114.6 ;
    END
  END f_d[35]
  PIN f_d[360]
    DIRECTION INPUT ;
    USE SIGNAL ;
    PORT
      LAYER M4 ;
        RECT  0 166.416 0.084 166.44 ;
    END
  END f_d[360]
  PIN f_d[361]
    DIRECTION INPUT ;
    USE SIGNAL ;
    PORT
      LAYER M4 ;
        RECT  0 166.608 0.084 166.632 ;
    END
  END f_d[361]
  PIN f_d[362]
    DIRECTION INPUT ;
    USE SIGNAL ;
    PORT
      LAYER M4 ;
        RECT  0 166.8 0.084 166.824 ;
    END
  END f_d[362]
  PIN f_d[363]
    DIRECTION INPUT ;
    USE SIGNAL ;
    PORT
      LAYER M4 ;
        RECT  0 166.992 0.084 167.016 ;
    END
  END f_d[363]
  PIN f_d[364]
    DIRECTION INPUT ;
    USE SIGNAL ;
    PORT
      LAYER M4 ;
        RECT  0 167.184 0.084 167.208 ;
    END
  END f_d[364]
  PIN f_d[365]
    DIRECTION INPUT ;
    USE SIGNAL ;
    PORT
      LAYER M4 ;
        RECT  0 167.376 0.084 167.4 ;
    END
  END f_d[365]
  PIN f_d[366]
    DIRECTION INPUT ;
    USE SIGNAL ;
    PORT
      LAYER M4 ;
        RECT  0 167.568 0.084 167.592 ;
    END
  END f_d[366]
  PIN f_d[367]
    DIRECTION INPUT ;
    USE SIGNAL ;
    PORT
      LAYER M4 ;
        RECT  0 167.76 0.084 167.784 ;
    END
  END f_d[367]
  PIN f_d[368]
    DIRECTION INPUT ;
    USE SIGNAL ;
    PORT
      LAYER M4 ;
        RECT  0 167.952 0.084 167.976 ;
    END
  END f_d[368]
  PIN f_d[369]
    DIRECTION INPUT ;
    USE SIGNAL ;
    PORT
      LAYER M4 ;
        RECT  0 168.144 0.084 168.168 ;
    END
  END f_d[369]
  PIN f_d[36]
    DIRECTION INPUT ;
    USE SIGNAL ;
    PORT
      LAYER M4 ;
        RECT  0 114.768 0.084 114.792 ;
    END
  END f_d[36]
  PIN f_d[370]
    DIRECTION INPUT ;
    USE SIGNAL ;
    PORT
      LAYER M4 ;
        RECT  0 168.336 0.084 168.36 ;
    END
  END f_d[370]
  PIN f_d[371]
    DIRECTION INPUT ;
    USE SIGNAL ;
    PORT
      LAYER M4 ;
        RECT  0 168.528 0.084 168.552 ;
    END
  END f_d[371]
  PIN f_d[372]
    DIRECTION INPUT ;
    USE SIGNAL ;
    PORT
      LAYER M4 ;
        RECT  0 168.72 0.084 168.744 ;
    END
  END f_d[372]
  PIN f_d[373]
    DIRECTION INPUT ;
    USE SIGNAL ;
    PORT
      LAYER M4 ;
        RECT  0 168.912 0.084 168.936 ;
    END
  END f_d[373]
  PIN f_d[374]
    DIRECTION INPUT ;
    USE SIGNAL ;
    PORT
      LAYER M4 ;
        RECT  0 169.104 0.084 169.128 ;
    END
  END f_d[374]
  PIN f_d[375]
    DIRECTION INPUT ;
    USE SIGNAL ;
    PORT
      LAYER M4 ;
        RECT  0 169.296 0.084 169.32 ;
    END
  END f_d[375]
  PIN f_d[376]
    DIRECTION INPUT ;
    USE SIGNAL ;
    PORT
      LAYER M4 ;
        RECT  0 169.488 0.084 169.512 ;
    END
  END f_d[376]
  PIN f_d[377]
    DIRECTION INPUT ;
    USE SIGNAL ;
    PORT
      LAYER M4 ;
        RECT  0 169.68 0.084 169.704 ;
    END
  END f_d[377]
  PIN f_d[378]
    DIRECTION INPUT ;
    USE SIGNAL ;
    PORT
      LAYER M4 ;
        RECT  0 169.872 0.084 169.896 ;
    END
  END f_d[378]
  PIN f_d[379]
    DIRECTION INPUT ;
    USE SIGNAL ;
    PORT
      LAYER M4 ;
        RECT  0 170.064 0.084 170.088 ;
    END
  END f_d[379]
  PIN f_d[37]
    DIRECTION INPUT ;
    USE SIGNAL ;
    PORT
      LAYER M4 ;
        RECT  0 114.96 0.084 114.984 ;
    END
  END f_d[37]
  PIN f_d[380]
    DIRECTION INPUT ;
    USE SIGNAL ;
    PORT
      LAYER M4 ;
        RECT  0 170.256 0.084 170.28 ;
    END
  END f_d[380]
  PIN f_d[381]
    DIRECTION INPUT ;
    USE SIGNAL ;
    PORT
      LAYER M4 ;
        RECT  0 170.448 0.084 170.472 ;
    END
  END f_d[381]
  PIN f_d[382]
    DIRECTION INPUT ;
    USE SIGNAL ;
    PORT
      LAYER M4 ;
        RECT  0 170.64 0.084 170.664 ;
    END
  END f_d[382]
  PIN f_d[383]
    DIRECTION INPUT ;
    USE SIGNAL ;
    PORT
      LAYER M4 ;
        RECT  0 37.2 0.084 37.224 ;
    END
  END f_d[383]
  PIN f_d[384]
    DIRECTION INPUT ;
    USE SIGNAL ;
    PORT
      LAYER M4 ;
        RECT  0 37.392 0.084 37.416 ;
    END
  END f_d[384]
  PIN f_d[385]
    DIRECTION INPUT ;
    USE SIGNAL ;
    PORT
      LAYER M4 ;
        RECT  0 37.584 0.084 37.608 ;
    END
  END f_d[385]
  PIN f_d[386]
    DIRECTION INPUT ;
    USE SIGNAL ;
    PORT
      LAYER M4 ;
        RECT  0 37.776 0.084 37.8 ;
    END
  END f_d[386]
  PIN f_d[387]
    DIRECTION INPUT ;
    USE SIGNAL ;
    PORT
      LAYER M4 ;
        RECT  0 37.968 0.084 37.992 ;
    END
  END f_d[387]
  PIN f_d[388]
    DIRECTION INPUT ;
    USE SIGNAL ;
    PORT
      LAYER M4 ;
        RECT  0 38.16 0.084 38.184 ;
    END
  END f_d[388]
  PIN f_d[389]
    DIRECTION INPUT ;
    USE SIGNAL ;
    PORT
      LAYER M4 ;
        RECT  0 38.352 0.084 38.376 ;
    END
  END f_d[389]
  PIN f_d[38]
    DIRECTION INPUT ;
    USE SIGNAL ;
    PORT
      LAYER M4 ;
        RECT  0 115.152 0.084 115.176 ;
    END
  END f_d[38]
  PIN f_d[390]
    DIRECTION INPUT ;
    USE SIGNAL ;
    PORT
      LAYER M4 ;
        RECT  0 38.544 0.084 38.568 ;
    END
  END f_d[390]
  PIN f_d[391]
    DIRECTION INPUT ;
    USE SIGNAL ;
    PORT
      LAYER M4 ;
        RECT  0 38.736 0.084 38.76 ;
    END
  END f_d[391]
  PIN f_d[392]
    DIRECTION INPUT ;
    USE SIGNAL ;
    PORT
      LAYER M4 ;
        RECT  0 38.928 0.084 38.952 ;
    END
  END f_d[392]
  PIN f_d[393]
    DIRECTION INPUT ;
    USE SIGNAL ;
    PORT
      LAYER M4 ;
        RECT  0 39.12 0.084 39.144 ;
    END
  END f_d[393]
  PIN f_d[394]
    DIRECTION INPUT ;
    USE SIGNAL ;
    PORT
      LAYER M4 ;
        RECT  0 39.312 0.084 39.336 ;
    END
  END f_d[394]
  PIN f_d[395]
    DIRECTION INPUT ;
    USE SIGNAL ;
    PORT
      LAYER M4 ;
        RECT  0 39.504 0.084 39.528 ;
    END
  END f_d[395]
  PIN f_d[396]
    DIRECTION INPUT ;
    USE SIGNAL ;
    PORT
      LAYER M4 ;
        RECT  0 39.696 0.084 39.72 ;
    END
  END f_d[396]
  PIN f_d[397]
    DIRECTION INPUT ;
    USE SIGNAL ;
    PORT
      LAYER M4 ;
        RECT  0 39.888 0.084 39.912 ;
    END
  END f_d[397]
  PIN f_d[398]
    DIRECTION INPUT ;
    USE SIGNAL ;
    PORT
      LAYER M4 ;
        RECT  0 40.08 0.084 40.104 ;
    END
  END f_d[398]
  PIN f_d[399]
    DIRECTION INPUT ;
    USE SIGNAL ;
    PORT
      LAYER M4 ;
        RECT  0 40.272 0.084 40.296 ;
    END
  END f_d[399]
  PIN f_d[39]
    DIRECTION INPUT ;
    USE SIGNAL ;
    PORT
      LAYER M4 ;
        RECT  0 115.344 0.084 115.368 ;
    END
  END f_d[39]
  PIN f_d[3]
    DIRECTION INPUT ;
    USE SIGNAL ;
    PORT
      LAYER M4 ;
        RECT  0 25.488 0.084 25.512 ;
    END
  END f_d[3]
  PIN f_d[400]
    DIRECTION INPUT ;
    USE SIGNAL ;
    PORT
      LAYER M4 ;
        RECT  0 40.464 0.084 40.488 ;
    END
  END f_d[400]
  PIN f_d[401]
    DIRECTION INPUT ;
    USE SIGNAL ;
    PORT
      LAYER M4 ;
        RECT  0 40.656 0.084 40.68 ;
    END
  END f_d[401]
  PIN f_d[402]
    DIRECTION INPUT ;
    USE SIGNAL ;
    PORT
      LAYER M4 ;
        RECT  0 40.848 0.084 40.872 ;
    END
  END f_d[402]
  PIN f_d[403]
    DIRECTION INPUT ;
    USE SIGNAL ;
    PORT
      LAYER M4 ;
        RECT  0 41.04 0.084 41.064 ;
    END
  END f_d[403]
  PIN f_d[404]
    DIRECTION INPUT ;
    USE SIGNAL ;
    PORT
      LAYER M4 ;
        RECT  0 41.232 0.084 41.256 ;
    END
  END f_d[404]
  PIN f_d[405]
    DIRECTION INPUT ;
    USE SIGNAL ;
    PORT
      LAYER M4 ;
        RECT  0 41.424 0.084 41.448 ;
    END
  END f_d[405]
  PIN f_d[406]
    DIRECTION INPUT ;
    USE SIGNAL ;
    PORT
      LAYER M4 ;
        RECT  0 41.616 0.084 41.64 ;
    END
  END f_d[406]
  PIN f_d[407]
    DIRECTION INPUT ;
    USE SIGNAL ;
    PORT
      LAYER M4 ;
        RECT  0 41.808 0.084 41.832 ;
    END
  END f_d[407]
  PIN f_d[408]
    DIRECTION INPUT ;
    USE SIGNAL ;
    PORT
      LAYER M4 ;
        RECT  0 42 0.084 42.024 ;
    END
  END f_d[408]
  PIN f_d[409]
    DIRECTION INPUT ;
    USE SIGNAL ;
    PORT
      LAYER M4 ;
        RECT  0 42.192 0.084 42.216 ;
    END
  END f_d[409]
  PIN f_d[40]
    DIRECTION INPUT ;
    USE SIGNAL ;
    PORT
      LAYER M4 ;
        RECT  0 115.536 0.084 115.56 ;
    END
  END f_d[40]
  PIN f_d[410]
    DIRECTION INPUT ;
    USE SIGNAL ;
    PORT
      LAYER M4 ;
        RECT  0 42.384 0.084 42.408 ;
    END
  END f_d[410]
  PIN f_d[411]
    DIRECTION INPUT ;
    USE SIGNAL ;
    PORT
      LAYER M4 ;
        RECT  0 42.576 0.084 42.6 ;
    END
  END f_d[411]
  PIN f_d[412]
    DIRECTION INPUT ;
    USE SIGNAL ;
    PORT
      LAYER M4 ;
        RECT  0 42.768 0.084 42.792 ;
    END
  END f_d[412]
  PIN f_d[413]
    DIRECTION INPUT ;
    USE SIGNAL ;
    PORT
      LAYER M4 ;
        RECT  0 42.96 0.084 42.984 ;
    END
  END f_d[413]
  PIN f_d[414]
    DIRECTION INPUT ;
    USE SIGNAL ;
    PORT
      LAYER M4 ;
        RECT  0 43.152 0.084 43.176 ;
    END
  END f_d[414]
  PIN f_d[415]
    DIRECTION INPUT ;
    USE SIGNAL ;
    PORT
      LAYER M4 ;
        RECT  0 31.056 0.084 31.08 ;
    END
  END f_d[415]
  PIN f_d[416]
    DIRECTION INPUT ;
    USE SIGNAL ;
    PORT
      LAYER M4 ;
        RECT  0 31.248 0.084 31.272 ;
    END
  END f_d[416]
  PIN f_d[417]
    DIRECTION INPUT ;
    USE SIGNAL ;
    PORT
      LAYER M4 ;
        RECT  0 31.44 0.084 31.464 ;
    END
  END f_d[417]
  PIN f_d[418]
    DIRECTION INPUT ;
    USE SIGNAL ;
    PORT
      LAYER M4 ;
        RECT  0 31.632 0.084 31.656 ;
    END
  END f_d[418]
  PIN f_d[419]
    DIRECTION INPUT ;
    USE SIGNAL ;
    PORT
      LAYER M4 ;
        RECT  0 31.824 0.084 31.848 ;
    END
  END f_d[419]
  PIN f_d[41]
    DIRECTION INPUT ;
    USE SIGNAL ;
    PORT
      LAYER M4 ;
        RECT  0 115.728 0.084 115.752 ;
    END
  END f_d[41]
  PIN f_d[420]
    DIRECTION INPUT ;
    USE SIGNAL ;
    PORT
      LAYER M4 ;
        RECT  0 32.016 0.084 32.04 ;
    END
  END f_d[420]
  PIN f_d[421]
    DIRECTION INPUT ;
    USE SIGNAL ;
    PORT
      LAYER M4 ;
        RECT  0 32.208 0.084 32.232 ;
    END
  END f_d[421]
  PIN f_d[422]
    DIRECTION INPUT ;
    USE SIGNAL ;
    PORT
      LAYER M4 ;
        RECT  0 32.4 0.084 32.424 ;
    END
  END f_d[422]
  PIN f_d[423]
    DIRECTION INPUT ;
    USE SIGNAL ;
    PORT
      LAYER M4 ;
        RECT  0 32.592 0.084 32.616 ;
    END
  END f_d[423]
  PIN f_d[424]
    DIRECTION INPUT ;
    USE SIGNAL ;
    PORT
      LAYER M4 ;
        RECT  0 32.784 0.084 32.808 ;
    END
  END f_d[424]
  PIN f_d[425]
    DIRECTION INPUT ;
    USE SIGNAL ;
    PORT
      LAYER M4 ;
        RECT  0 32.976 0.084 33 ;
    END
  END f_d[425]
  PIN f_d[426]
    DIRECTION INPUT ;
    USE SIGNAL ;
    PORT
      LAYER M4 ;
        RECT  0 33.168 0.084 33.192 ;
    END
  END f_d[426]
  PIN f_d[427]
    DIRECTION INPUT ;
    USE SIGNAL ;
    PORT
      LAYER M4 ;
        RECT  0 33.36 0.084 33.384 ;
    END
  END f_d[427]
  PIN f_d[428]
    DIRECTION INPUT ;
    USE SIGNAL ;
    PORT
      LAYER M4 ;
        RECT  0 33.552 0.084 33.576 ;
    END
  END f_d[428]
  PIN f_d[429]
    DIRECTION INPUT ;
    USE SIGNAL ;
    PORT
      LAYER M4 ;
        RECT  0 33.744 0.084 33.768 ;
    END
  END f_d[429]
  PIN f_d[42]
    DIRECTION INPUT ;
    USE SIGNAL ;
    PORT
      LAYER M4 ;
        RECT  0 115.92 0.084 115.944 ;
    END
  END f_d[42]
  PIN f_d[430]
    DIRECTION INPUT ;
    USE SIGNAL ;
    PORT
      LAYER M4 ;
        RECT  0 33.936 0.084 33.96 ;
    END
  END f_d[430]
  PIN f_d[431]
    DIRECTION INPUT ;
    USE SIGNAL ;
    PORT
      LAYER M4 ;
        RECT  0 34.128 0.084 34.152 ;
    END
  END f_d[431]
  PIN f_d[432]
    DIRECTION INPUT ;
    USE SIGNAL ;
    PORT
      LAYER M4 ;
        RECT  0 34.32 0.084 34.344 ;
    END
  END f_d[432]
  PIN f_d[433]
    DIRECTION INPUT ;
    USE SIGNAL ;
    PORT
      LAYER M4 ;
        RECT  0 34.512 0.084 34.536 ;
    END
  END f_d[433]
  PIN f_d[434]
    DIRECTION INPUT ;
    USE SIGNAL ;
    PORT
      LAYER M4 ;
        RECT  0 34.704 0.084 34.728 ;
    END
  END f_d[434]
  PIN f_d[435]
    DIRECTION INPUT ;
    USE SIGNAL ;
    PORT
      LAYER M4 ;
        RECT  0 34.896 0.084 34.92 ;
    END
  END f_d[435]
  PIN f_d[436]
    DIRECTION INPUT ;
    USE SIGNAL ;
    PORT
      LAYER M4 ;
        RECT  0 35.088 0.084 35.112 ;
    END
  END f_d[436]
  PIN f_d[437]
    DIRECTION INPUT ;
    USE SIGNAL ;
    PORT
      LAYER M4 ;
        RECT  0 35.28 0.084 35.304 ;
    END
  END f_d[437]
  PIN f_d[438]
    DIRECTION INPUT ;
    USE SIGNAL ;
    PORT
      LAYER M4 ;
        RECT  0 35.472 0.084 35.496 ;
    END
  END f_d[438]
  PIN f_d[439]
    DIRECTION INPUT ;
    USE SIGNAL ;
    PORT
      LAYER M4 ;
        RECT  0 35.664 0.084 35.688 ;
    END
  END f_d[439]
  PIN f_d[43]
    DIRECTION INPUT ;
    USE SIGNAL ;
    PORT
      LAYER M4 ;
        RECT  0 116.112 0.084 116.136 ;
    END
  END f_d[43]
  PIN f_d[440]
    DIRECTION INPUT ;
    USE SIGNAL ;
    PORT
      LAYER M4 ;
        RECT  0 35.856 0.084 35.88 ;
    END
  END f_d[440]
  PIN f_d[441]
    DIRECTION INPUT ;
    USE SIGNAL ;
    PORT
      LAYER M4 ;
        RECT  0 36.048 0.084 36.072 ;
    END
  END f_d[441]
  PIN f_d[442]
    DIRECTION INPUT ;
    USE SIGNAL ;
    PORT
      LAYER M4 ;
        RECT  0 36.24 0.084 36.264 ;
    END
  END f_d[442]
  PIN f_d[443]
    DIRECTION INPUT ;
    USE SIGNAL ;
    PORT
      LAYER M4 ;
        RECT  0 36.432 0.084 36.456 ;
    END
  END f_d[443]
  PIN f_d[444]
    DIRECTION INPUT ;
    USE SIGNAL ;
    PORT
      LAYER M4 ;
        RECT  0 36.624 0.084 36.648 ;
    END
  END f_d[444]
  PIN f_d[445]
    DIRECTION INPUT ;
    USE SIGNAL ;
    PORT
      LAYER M4 ;
        RECT  0 36.816 0.084 36.84 ;
    END
  END f_d[445]
  PIN f_d[446]
    DIRECTION INPUT ;
    USE SIGNAL ;
    PORT
      LAYER M4 ;
        RECT  0 37.008 0.084 37.032 ;
    END
  END f_d[446]
  PIN f_d[447]
    DIRECTION INPUT ;
    USE SIGNAL ;
    PORT
      LAYER M4 ;
        RECT  0 107.856 0.084 107.88 ;
    END
  END f_d[447]
  PIN f_d[448]
    DIRECTION INPUT ;
    USE SIGNAL ;
    PORT
      LAYER M4 ;
        RECT  0 108.048 0.084 108.072 ;
    END
  END f_d[448]
  PIN f_d[449]
    DIRECTION INPUT ;
    USE SIGNAL ;
    PORT
      LAYER M4 ;
        RECT  0 108.24 0.084 108.264 ;
    END
  END f_d[449]
  PIN f_d[44]
    DIRECTION INPUT ;
    USE SIGNAL ;
    PORT
      LAYER M4 ;
        RECT  0 116.304 0.084 116.328 ;
    END
  END f_d[44]
  PIN f_d[450]
    DIRECTION INPUT ;
    USE SIGNAL ;
    PORT
      LAYER M4 ;
        RECT  0 108.624 0.084 108.648 ;
    END
  END f_d[450]
  PIN f_d[451]
    DIRECTION INPUT ;
    USE SIGNAL ;
    PORT
      LAYER M4 ;
        RECT  0 108.816 0.084 108.84 ;
    END
  END f_d[451]
  PIN f_d[452]
    DIRECTION INPUT ;
    USE SIGNAL ;
    PORT
      LAYER M4 ;
        RECT  0 109.008 0.084 109.032 ;
    END
  END f_d[452]
  PIN f_d[453]
    DIRECTION INPUT ;
    USE SIGNAL ;
    PORT
      LAYER M4 ;
        RECT  0 109.2 0.084 109.224 ;
    END
  END f_d[453]
  PIN f_d[454]
    DIRECTION INPUT ;
    USE SIGNAL ;
    PORT
      LAYER M4 ;
        RECT  0 109.392 0.084 109.416 ;
    END
  END f_d[454]
  PIN f_d[455]
    DIRECTION INPUT ;
    USE SIGNAL ;
    PORT
      LAYER M4 ;
        RECT  0 109.584 0.084 109.608 ;
    END
  END f_d[455]
  PIN f_d[456]
    DIRECTION INPUT ;
    USE SIGNAL ;
    PORT
      LAYER M4 ;
        RECT  0 109.776 0.084 109.8 ;
    END
  END f_d[456]
  PIN f_d[457]
    DIRECTION INPUT ;
    USE SIGNAL ;
    PORT
      LAYER M4 ;
        RECT  0 109.968 0.084 109.992 ;
    END
  END f_d[457]
  PIN f_d[458]
    DIRECTION INPUT ;
    USE SIGNAL ;
    PORT
      LAYER M4 ;
        RECT  0 110.16 0.084 110.184 ;
    END
  END f_d[458]
  PIN f_d[459]
    DIRECTION INPUT ;
    USE SIGNAL ;
    PORT
      LAYER M4 ;
        RECT  0 110.352 0.084 110.376 ;
    END
  END f_d[459]
  PIN f_d[45]
    DIRECTION INPUT ;
    USE SIGNAL ;
    PORT
      LAYER M4 ;
        RECT  0 116.496 0.084 116.52 ;
    END
  END f_d[45]
  PIN f_d[460]
    DIRECTION INPUT ;
    USE SIGNAL ;
    PORT
      LAYER M4 ;
        RECT  0 110.544 0.084 110.568 ;
    END
  END f_d[460]
  PIN f_d[461]
    DIRECTION INPUT ;
    USE SIGNAL ;
    PORT
      LAYER M4 ;
        RECT  0 110.736 0.084 110.76 ;
    END
  END f_d[461]
  PIN f_d[462]
    DIRECTION INPUT ;
    USE SIGNAL ;
    PORT
      LAYER M4 ;
        RECT  0 110.928 0.084 110.952 ;
    END
  END f_d[462]
  PIN f_d[463]
    DIRECTION INPUT ;
    USE SIGNAL ;
    PORT
      LAYER M4 ;
        RECT  0 111.12 0.084 111.144 ;
    END
  END f_d[463]
  PIN f_d[464]
    DIRECTION INPUT ;
    USE SIGNAL ;
    PORT
      LAYER M4 ;
        RECT  0 111.312 0.084 111.336 ;
    END
  END f_d[464]
  PIN f_d[465]
    DIRECTION INPUT ;
    USE SIGNAL ;
    PORT
      LAYER M4 ;
        RECT  0 111.504 0.084 111.528 ;
    END
  END f_d[465]
  PIN f_d[466]
    DIRECTION INPUT ;
    USE SIGNAL ;
    PORT
      LAYER M4 ;
        RECT  0 111.696 0.084 111.72 ;
    END
  END f_d[466]
  PIN f_d[467]
    DIRECTION INPUT ;
    USE SIGNAL ;
    PORT
      LAYER M4 ;
        RECT  0 111.888 0.084 111.912 ;
    END
  END f_d[467]
  PIN f_d[468]
    DIRECTION INPUT ;
    USE SIGNAL ;
    PORT
      LAYER M4 ;
        RECT  0 112.08 0.084 112.104 ;
    END
  END f_d[468]
  PIN f_d[469]
    DIRECTION INPUT ;
    USE SIGNAL ;
    PORT
      LAYER M4 ;
        RECT  0 112.272 0.084 112.296 ;
    END
  END f_d[469]
  PIN f_d[46]
    DIRECTION INPUT ;
    USE SIGNAL ;
    PORT
      LAYER M4 ;
        RECT  0 116.688 0.084 116.712 ;
    END
  END f_d[46]
  PIN f_d[470]
    DIRECTION INPUT ;
    USE SIGNAL ;
    PORT
      LAYER M4 ;
        RECT  0 112.464 0.084 112.488 ;
    END
  END f_d[470]
  PIN f_d[471]
    DIRECTION INPUT ;
    USE SIGNAL ;
    PORT
      LAYER M4 ;
        RECT  0 112.656 0.084 112.68 ;
    END
  END f_d[471]
  PIN f_d[472]
    DIRECTION INPUT ;
    USE SIGNAL ;
    PORT
      LAYER M4 ;
        RECT  0 112.848 0.084 112.872 ;
    END
  END f_d[472]
  PIN f_d[473]
    DIRECTION INPUT ;
    USE SIGNAL ;
    PORT
      LAYER M4 ;
        RECT  0 113.04 0.084 113.064 ;
    END
  END f_d[473]
  PIN f_d[474]
    DIRECTION INPUT ;
    USE SIGNAL ;
    PORT
      LAYER M4 ;
        RECT  0 113.232 0.084 113.256 ;
    END
  END f_d[474]
  PIN f_d[475]
    DIRECTION INPUT ;
    USE SIGNAL ;
    PORT
      LAYER M4 ;
        RECT  0 113.424 0.084 113.448 ;
    END
  END f_d[475]
  PIN f_d[476]
    DIRECTION INPUT ;
    USE SIGNAL ;
    PORT
      LAYER M4 ;
        RECT  0 113.616 0.084 113.64 ;
    END
  END f_d[476]
  PIN f_d[477]
    DIRECTION INPUT ;
    USE SIGNAL ;
    PORT
      LAYER M4 ;
        RECT  0 113.808 0.084 113.832 ;
    END
  END f_d[477]
  PIN f_d[478]
    DIRECTION INPUT ;
    USE SIGNAL ;
    PORT
      LAYER M4 ;
        RECT  0 55.632 0.084 55.656 ;
    END
  END f_d[478]
  PIN f_d[479]
    DIRECTION INPUT ;
    USE SIGNAL ;
    PORT
      LAYER M4 ;
        RECT  0 55.824 0.084 55.848 ;
    END
  END f_d[479]
  PIN f_d[47]
    DIRECTION INPUT ;
    USE SIGNAL ;
    PORT
      LAYER M4 ;
        RECT  0 116.88 0.084 116.904 ;
    END
  END f_d[47]
  PIN f_d[480]
    DIRECTION INPUT ;
    USE SIGNAL ;
    PORT
      LAYER M4 ;
        RECT  0 56.016 0.084 56.04 ;
    END
  END f_d[480]
  PIN f_d[481]
    DIRECTION INPUT ;
    USE SIGNAL ;
    PORT
      LAYER M4 ;
        RECT  0 56.208 0.084 56.232 ;
    END
  END f_d[481]
  PIN f_d[482]
    DIRECTION INPUT ;
    USE SIGNAL ;
    PORT
      LAYER M4 ;
        RECT  0 56.4 0.084 56.424 ;
    END
  END f_d[482]
  PIN f_d[483]
    DIRECTION INPUT ;
    USE SIGNAL ;
    PORT
      LAYER M4 ;
        RECT  0 56.592 0.084 56.616 ;
    END
  END f_d[483]
  PIN f_d[484]
    DIRECTION INPUT ;
    USE SIGNAL ;
    PORT
      LAYER M4 ;
        RECT  0 56.784 0.084 56.808 ;
    END
  END f_d[484]
  PIN f_d[485]
    DIRECTION INPUT ;
    USE SIGNAL ;
    PORT
      LAYER M4 ;
        RECT  0 56.976 0.084 57 ;
    END
  END f_d[485]
  PIN f_d[486]
    DIRECTION INPUT ;
    USE SIGNAL ;
    PORT
      LAYER M4 ;
        RECT  0 57.168 0.084 57.192 ;
    END
  END f_d[486]
  PIN f_d[487]
    DIRECTION INPUT ;
    USE SIGNAL ;
    PORT
      LAYER M4 ;
        RECT  0 57.36 0.084 57.384 ;
    END
  END f_d[487]
  PIN f_d[488]
    DIRECTION INPUT ;
    USE SIGNAL ;
    PORT
      LAYER M4 ;
        RECT  0 57.552 0.084 57.576 ;
    END
  END f_d[488]
  PIN f_d[489]
    DIRECTION INPUT ;
    USE SIGNAL ;
    PORT
      LAYER M4 ;
        RECT  0 57.744 0.084 57.768 ;
    END
  END f_d[489]
  PIN f_d[48]
    DIRECTION INPUT ;
    USE SIGNAL ;
    PORT
      LAYER M4 ;
        RECT  0 117.072 0.084 117.096 ;
    END
  END f_d[48]
  PIN f_d[490]
    DIRECTION INPUT ;
    USE SIGNAL ;
    PORT
      LAYER M4 ;
        RECT  0 57.936 0.084 57.96 ;
    END
  END f_d[490]
  PIN f_d[491]
    DIRECTION INPUT ;
    USE SIGNAL ;
    PORT
      LAYER M4 ;
        RECT  0 58.128 0.084 58.152 ;
    END
  END f_d[491]
  PIN f_d[492]
    DIRECTION INPUT ;
    USE SIGNAL ;
    PORT
      LAYER M4 ;
        RECT  0 58.32 0.084 58.344 ;
    END
  END f_d[492]
  PIN f_d[493]
    DIRECTION INPUT ;
    USE SIGNAL ;
    PORT
      LAYER M4 ;
        RECT  0 58.512 0.084 58.536 ;
    END
  END f_d[493]
  PIN f_d[494]
    DIRECTION INPUT ;
    USE SIGNAL ;
    PORT
      LAYER M4 ;
        RECT  0 58.704 0.084 58.728 ;
    END
  END f_d[494]
  PIN f_d[495]
    DIRECTION INPUT ;
    USE SIGNAL ;
    PORT
      LAYER M4 ;
        RECT  0 58.896 0.084 58.92 ;
    END
  END f_d[495]
  PIN f_d[496]
    DIRECTION INPUT ;
    USE SIGNAL ;
    PORT
      LAYER M4 ;
        RECT  0 59.088 0.084 59.112 ;
    END
  END f_d[496]
  PIN f_d[497]
    DIRECTION INPUT ;
    USE SIGNAL ;
    PORT
      LAYER M4 ;
        RECT  0 59.28 0.084 59.304 ;
    END
  END f_d[497]
  PIN f_d[498]
    DIRECTION INPUT ;
    USE SIGNAL ;
    PORT
      LAYER M4 ;
        RECT  0 59.472 0.084 59.496 ;
    END
  END f_d[498]
  PIN f_d[499]
    DIRECTION INPUT ;
    USE SIGNAL ;
    PORT
      LAYER M4 ;
        RECT  0 59.664 0.084 59.688 ;
    END
  END f_d[499]
  PIN f_d[49]
    DIRECTION INPUT ;
    USE SIGNAL ;
    PORT
      LAYER M4 ;
        RECT  0 117.264 0.084 117.288 ;
    END
  END f_d[49]
  PIN f_d[4]
    DIRECTION INPUT ;
    USE SIGNAL ;
    PORT
      LAYER M4 ;
        RECT  0 25.68 0.084 25.704 ;
    END
  END f_d[4]
  PIN f_d[500]
    DIRECTION INPUT ;
    USE SIGNAL ;
    PORT
      LAYER M4 ;
        RECT  0 59.856 0.084 59.88 ;
    END
  END f_d[500]
  PIN f_d[501]
    DIRECTION INPUT ;
    USE SIGNAL ;
    PORT
      LAYER M4 ;
        RECT  0 60.048 0.084 60.072 ;
    END
  END f_d[501]
  PIN f_d[502]
    DIRECTION INPUT ;
    USE SIGNAL ;
    PORT
      LAYER M4 ;
        RECT  0 60.24 0.084 60.264 ;
    END
  END f_d[502]
  PIN f_d[503]
    DIRECTION INPUT ;
    USE SIGNAL ;
    PORT
      LAYER M4 ;
        RECT  0 60.432 0.084 60.456 ;
    END
  END f_d[503]
  PIN f_d[504]
    DIRECTION INPUT ;
    USE SIGNAL ;
    PORT
      LAYER M4 ;
        RECT  0 60.624 0.084 60.648 ;
    END
  END f_d[504]
  PIN f_d[505]
    DIRECTION INPUT ;
    USE SIGNAL ;
    PORT
      LAYER M4 ;
        RECT  0 60.816 0.084 60.84 ;
    END
  END f_d[505]
  PIN f_d[506]
    DIRECTION INPUT ;
    USE SIGNAL ;
    PORT
      LAYER M4 ;
        RECT  0 61.008 0.084 61.032 ;
    END
  END f_d[506]
  PIN f_d[507]
    DIRECTION INPUT ;
    USE SIGNAL ;
    PORT
      LAYER M4 ;
        RECT  0 61.2 0.084 61.224 ;
    END
  END f_d[507]
  PIN f_d[508]
    DIRECTION INPUT ;
    USE SIGNAL ;
    PORT
      LAYER M4 ;
        RECT  0 61.392 0.084 61.416 ;
    END
  END f_d[508]
  PIN f_d[509]
    DIRECTION INPUT ;
    USE SIGNAL ;
    PORT
      LAYER M4 ;
        RECT  0 61.584 0.084 61.608 ;
    END
  END f_d[509]
  PIN f_d[50]
    DIRECTION INPUT ;
    USE SIGNAL ;
    PORT
      LAYER M4 ;
        RECT  0 117.456 0.084 117.48 ;
    END
  END f_d[50]
  PIN f_d[510]
    DIRECTION INPUT ;
    USE SIGNAL ;
    PORT
      LAYER M4 ;
        RECT  0 87.888 0.084 87.912 ;
    END
  END f_d[510]
  PIN f_d[511]
    DIRECTION INPUT ;
    USE SIGNAL ;
    PORT
      LAYER M4 ;
        RECT  0 88.08 0.084 88.104 ;
    END
  END f_d[511]
  PIN f_d[512]
    DIRECTION INPUT ;
    USE SIGNAL ;
    PORT
      LAYER M4 ;
        RECT  0 88.272 0.084 88.296 ;
    END
  END f_d[512]
  PIN f_d[513]
    DIRECTION INPUT ;
    USE SIGNAL ;
    PORT
      LAYER M4 ;
        RECT  0 88.464 0.084 88.488 ;
    END
  END f_d[513]
  PIN f_d[514]
    DIRECTION INPUT ;
    USE SIGNAL ;
    PORT
      LAYER M4 ;
        RECT  0 88.656 0.084 88.68 ;
    END
  END f_d[514]
  PIN f_d[515]
    DIRECTION INPUT ;
    USE SIGNAL ;
    PORT
      LAYER M4 ;
        RECT  0 88.848 0.084 88.872 ;
    END
  END f_d[515]
  PIN f_d[516]
    DIRECTION INPUT ;
    USE SIGNAL ;
    PORT
      LAYER M4 ;
        RECT  0 89.04 0.084 89.064 ;
    END
  END f_d[516]
  PIN f_d[517]
    DIRECTION INPUT ;
    USE SIGNAL ;
    PORT
      LAYER M4 ;
        RECT  0 89.232 0.084 89.256 ;
    END
  END f_d[517]
  PIN f_d[518]
    DIRECTION INPUT ;
    USE SIGNAL ;
    PORT
      LAYER M4 ;
        RECT  0 89.424 0.084 89.448 ;
    END
  END f_d[518]
  PIN f_d[519]
    DIRECTION INPUT ;
    USE SIGNAL ;
    PORT
      LAYER M4 ;
        RECT  0 89.616 0.084 89.64 ;
    END
  END f_d[519]
  PIN f_d[51]
    DIRECTION INPUT ;
    USE SIGNAL ;
    PORT
      LAYER M4 ;
        RECT  0 117.648 0.084 117.672 ;
    END
  END f_d[51]
  PIN f_d[520]
    DIRECTION INPUT ;
    USE SIGNAL ;
    PORT
      LAYER M4 ;
        RECT  0 89.808 0.084 89.832 ;
    END
  END f_d[520]
  PIN f_d[521]
    DIRECTION INPUT ;
    USE SIGNAL ;
    PORT
      LAYER M4 ;
        RECT  0 90 0.084 90.024 ;
    END
  END f_d[521]
  PIN f_d[522]
    DIRECTION INPUT ;
    USE SIGNAL ;
    PORT
      LAYER M4 ;
        RECT  0 90.192 0.084 90.216 ;
    END
  END f_d[522]
  PIN f_d[523]
    DIRECTION INPUT ;
    USE SIGNAL ;
    PORT
      LAYER M4 ;
        RECT  0 90.384 0.084 90.408 ;
    END
  END f_d[523]
  PIN f_d[524]
    DIRECTION INPUT ;
    USE SIGNAL ;
    PORT
      LAYER M4 ;
        RECT  0 90.576 0.084 90.6 ;
    END
  END f_d[524]
  PIN f_d[525]
    DIRECTION INPUT ;
    USE SIGNAL ;
    PORT
      LAYER M4 ;
        RECT  0 90.768 0.084 90.792 ;
    END
  END f_d[525]
  PIN f_d[526]
    DIRECTION INPUT ;
    USE SIGNAL ;
    PORT
      LAYER M4 ;
        RECT  0 90.96 0.084 90.984 ;
    END
  END f_d[526]
  PIN f_d[527]
    DIRECTION INPUT ;
    USE SIGNAL ;
    PORT
      LAYER M4 ;
        RECT  0 91.152 0.084 91.176 ;
    END
  END f_d[527]
  PIN f_d[528]
    DIRECTION INPUT ;
    USE SIGNAL ;
    PORT
      LAYER M4 ;
        RECT  0 91.344 0.084 91.368 ;
    END
  END f_d[528]
  PIN f_d[529]
    DIRECTION INPUT ;
    USE SIGNAL ;
    PORT
      LAYER M4 ;
        RECT  0 91.536 0.084 91.56 ;
    END
  END f_d[529]
  PIN f_d[52]
    DIRECTION INPUT ;
    USE SIGNAL ;
    PORT
      LAYER M4 ;
        RECT  0 117.84 0.084 117.864 ;
    END
  END f_d[52]
  PIN f_d[530]
    DIRECTION INPUT ;
    USE SIGNAL ;
    PORT
      LAYER M4 ;
        RECT  0 91.728 0.084 91.752 ;
    END
  END f_d[530]
  PIN f_d[531]
    DIRECTION INPUT ;
    USE SIGNAL ;
    PORT
      LAYER M4 ;
        RECT  0 91.92 0.084 91.944 ;
    END
  END f_d[531]
  PIN f_d[532]
    DIRECTION INPUT ;
    USE SIGNAL ;
    PORT
      LAYER M4 ;
        RECT  0 92.112 0.084 92.136 ;
    END
  END f_d[532]
  PIN f_d[533]
    DIRECTION INPUT ;
    USE SIGNAL ;
    PORT
      LAYER M4 ;
        RECT  0 92.304 0.084 92.328 ;
    END
  END f_d[533]
  PIN f_d[534]
    DIRECTION INPUT ;
    USE SIGNAL ;
    PORT
      LAYER M4 ;
        RECT  0 92.496 0.084 92.52 ;
    END
  END f_d[534]
  PIN f_d[535]
    DIRECTION INPUT ;
    USE SIGNAL ;
    PORT
      LAYER M4 ;
        RECT  0 92.688 0.084 92.712 ;
    END
  END f_d[535]
  PIN f_d[536]
    DIRECTION INPUT ;
    USE SIGNAL ;
    PORT
      LAYER M4 ;
        RECT  0 92.88 0.084 92.904 ;
    END
  END f_d[536]
  PIN f_d[537]
    DIRECTION INPUT ;
    USE SIGNAL ;
    PORT
      LAYER M4 ;
        RECT  0 93.072 0.084 93.096 ;
    END
  END f_d[537]
  PIN f_d[538]
    DIRECTION INPUT ;
    USE SIGNAL ;
    PORT
      LAYER M4 ;
        RECT  0 93.264 0.084 93.288 ;
    END
  END f_d[538]
  PIN f_d[539]
    DIRECTION INPUT ;
    USE SIGNAL ;
    PORT
      LAYER M4 ;
        RECT  0 93.456 0.084 93.48 ;
    END
  END f_d[539]
  PIN f_d[53]
    DIRECTION INPUT ;
    USE SIGNAL ;
    PORT
      LAYER M4 ;
        RECT  0 118.032 0.084 118.056 ;
    END
  END f_d[53]
  PIN f_d[540]
    DIRECTION INPUT ;
    USE SIGNAL ;
    PORT
      LAYER M4 ;
        RECT  0 93.648 0.084 93.672 ;
    END
  END f_d[540]
  PIN f_d[541]
    DIRECTION INPUT ;
    USE SIGNAL ;
    PORT
      LAYER M4 ;
        RECT  0 93.84 0.084 93.864 ;
    END
  END f_d[541]
  PIN f_d[542]
    DIRECTION INPUT ;
    USE SIGNAL ;
    PORT
      LAYER M4 ;
        RECT  0 170.832 0.084 170.856 ;
    END
  END f_d[542]
  PIN f_d[543]
    DIRECTION INPUT ;
    USE SIGNAL ;
    PORT
      LAYER M4 ;
        RECT  0 171.024 0.084 171.048 ;
    END
  END f_d[543]
  PIN f_d[544]
    DIRECTION INPUT ;
    USE SIGNAL ;
    PORT
      LAYER M4 ;
        RECT  0 171.216 0.084 171.24 ;
    END
  END f_d[544]
  PIN f_d[545]
    DIRECTION INPUT ;
    USE SIGNAL ;
    PORT
      LAYER M4 ;
        RECT  0 171.408 0.084 171.432 ;
    END
  END f_d[545]
  PIN f_d[546]
    DIRECTION INPUT ;
    USE SIGNAL ;
    PORT
      LAYER M4 ;
        RECT  0 171.6 0.084 171.624 ;
    END
  END f_d[546]
  PIN f_d[547]
    DIRECTION INPUT ;
    USE SIGNAL ;
    PORT
      LAYER M4 ;
        RECT  0 171.792 0.084 171.816 ;
    END
  END f_d[547]
  PIN f_d[548]
    DIRECTION INPUT ;
    USE SIGNAL ;
    PORT
      LAYER M4 ;
        RECT  0 171.984 0.084 172.008 ;
    END
  END f_d[548]
  PIN f_d[549]
    DIRECTION INPUT ;
    USE SIGNAL ;
    PORT
      LAYER M4 ;
        RECT  0 172.176 0.084 172.2 ;
    END
  END f_d[549]
  PIN f_d[54]
    DIRECTION INPUT ;
    USE SIGNAL ;
    PORT
      LAYER M4 ;
        RECT  0 118.224 0.084 118.248 ;
    END
  END f_d[54]
  PIN f_d[550]
    DIRECTION INPUT ;
    USE SIGNAL ;
    PORT
      LAYER M4 ;
        RECT  0 172.368 0.084 172.392 ;
    END
  END f_d[550]
  PIN f_d[551]
    DIRECTION INPUT ;
    USE SIGNAL ;
    PORT
      LAYER M4 ;
        RECT  0 172.56 0.084 172.584 ;
    END
  END f_d[551]
  PIN f_d[552]
    DIRECTION INPUT ;
    USE SIGNAL ;
    PORT
      LAYER M4 ;
        RECT  0 172.752 0.084 172.776 ;
    END
  END f_d[552]
  PIN f_d[553]
    DIRECTION INPUT ;
    USE SIGNAL ;
    PORT
      LAYER M4 ;
        RECT  0 172.944 0.084 172.968 ;
    END
  END f_d[553]
  PIN f_d[554]
    DIRECTION INPUT ;
    USE SIGNAL ;
    PORT
      LAYER M4 ;
        RECT  0 173.136 0.084 173.16 ;
    END
  END f_d[554]
  PIN f_d[555]
    DIRECTION INPUT ;
    USE SIGNAL ;
    PORT
      LAYER M4 ;
        RECT  0 173.328 0.084 173.352 ;
    END
  END f_d[555]
  PIN f_d[556]
    DIRECTION INPUT ;
    USE SIGNAL ;
    PORT
      LAYER M4 ;
        RECT  0 173.52 0.084 173.544 ;
    END
  END f_d[556]
  PIN f_d[557]
    DIRECTION INPUT ;
    USE SIGNAL ;
    PORT
      LAYER M4 ;
        RECT  0 173.712 0.084 173.736 ;
    END
  END f_d[557]
  PIN f_d[558]
    DIRECTION INPUT ;
    USE SIGNAL ;
    PORT
      LAYER M4 ;
        RECT  0 173.904 0.084 173.928 ;
    END
  END f_d[558]
  PIN f_d[559]
    DIRECTION INPUT ;
    USE SIGNAL ;
    PORT
      LAYER M4 ;
        RECT  0 174.096 0.084 174.12 ;
    END
  END f_d[559]
  PIN f_d[55]
    DIRECTION INPUT ;
    USE SIGNAL ;
    PORT
      LAYER M4 ;
        RECT  0 118.416 0.084 118.44 ;
    END
  END f_d[55]
  PIN f_d[560]
    DIRECTION INPUT ;
    USE SIGNAL ;
    PORT
      LAYER M4 ;
        RECT  0 174.288 0.084 174.312 ;
    END
  END f_d[560]
  PIN f_d[561]
    DIRECTION INPUT ;
    USE SIGNAL ;
    PORT
      LAYER M4 ;
        RECT  0 174.48 0.084 174.504 ;
    END
  END f_d[561]
  PIN f_d[562]
    DIRECTION INPUT ;
    USE SIGNAL ;
    PORT
      LAYER M4 ;
        RECT  0 174.672 0.084 174.696 ;
    END
  END f_d[562]
  PIN f_d[563]
    DIRECTION INPUT ;
    USE SIGNAL ;
    PORT
      LAYER M4 ;
        RECT  0 174.864 0.084 174.888 ;
    END
  END f_d[563]
  PIN f_d[564]
    DIRECTION INPUT ;
    USE SIGNAL ;
    PORT
      LAYER M4 ;
        RECT  0 175.056 0.084 175.08 ;
    END
  END f_d[564]
  PIN f_d[565]
    DIRECTION INPUT ;
    USE SIGNAL ;
    PORT
      LAYER M4 ;
        RECT  0 175.248 0.084 175.272 ;
    END
  END f_d[565]
  PIN f_d[566]
    DIRECTION INPUT ;
    USE SIGNAL ;
    PORT
      LAYER M4 ;
        RECT  0 175.44 0.084 175.464 ;
    END
  END f_d[566]
  PIN f_d[567]
    DIRECTION INPUT ;
    USE SIGNAL ;
    PORT
      LAYER M4 ;
        RECT  0 175.632 0.084 175.656 ;
    END
  END f_d[567]
  PIN f_d[568]
    DIRECTION INPUT ;
    USE SIGNAL ;
    PORT
      LAYER M4 ;
        RECT  0 175.824 0.084 175.848 ;
    END
  END f_d[568]
  PIN f_d[569]
    DIRECTION INPUT ;
    USE SIGNAL ;
    PORT
      LAYER M4 ;
        RECT  0 176.016 0.084 176.04 ;
    END
  END f_d[569]
  PIN f_d[56]
    DIRECTION INPUT ;
    USE SIGNAL ;
    PORT
      LAYER M4 ;
        RECT  0 118.608 0.084 118.632 ;
    END
  END f_d[56]
  PIN f_d[570]
    DIRECTION INPUT ;
    USE SIGNAL ;
    PORT
      LAYER M4 ;
        RECT  0 176.208 0.084 176.232 ;
    END
  END f_d[570]
  PIN f_d[571]
    DIRECTION INPUT ;
    USE SIGNAL ;
    PORT
      LAYER M4 ;
        RECT  0 176.4 0.084 176.424 ;
    END
  END f_d[571]
  PIN f_d[572]
    DIRECTION INPUT ;
    USE SIGNAL ;
    PORT
      LAYER M4 ;
        RECT  0 176.592 0.084 176.616 ;
    END
  END f_d[572]
  PIN f_d[573]
    DIRECTION INPUT ;
    USE SIGNAL ;
    PORT
      LAYER M4 ;
        RECT  0 176.784 0.084 176.808 ;
    END
  END f_d[573]
  PIN f_d[574]
    DIRECTION INPUT ;
    USE SIGNAL ;
    PORT
      LAYER M4 ;
        RECT  0 140.112 0.084 140.136 ;
    END
  END f_d[574]
  PIN f_d[575]
    DIRECTION INPUT ;
    USE SIGNAL ;
    PORT
      LAYER M4 ;
        RECT  0 140.304 0.084 140.328 ;
    END
  END f_d[575]
  PIN f_d[576]
    DIRECTION INPUT ;
    USE SIGNAL ;
    PORT
      LAYER M4 ;
        RECT  0 140.496 0.084 140.52 ;
    END
  END f_d[576]
  PIN f_d[577]
    DIRECTION INPUT ;
    USE SIGNAL ;
    PORT
      LAYER M4 ;
        RECT  0 140.688 0.084 140.712 ;
    END
  END f_d[577]
  PIN f_d[578]
    DIRECTION INPUT ;
    USE SIGNAL ;
    PORT
      LAYER M4 ;
        RECT  0 140.88 0.084 140.904 ;
    END
  END f_d[578]
  PIN f_d[579]
    DIRECTION INPUT ;
    USE SIGNAL ;
    PORT
      LAYER M4 ;
        RECT  0 141.072 0.084 141.096 ;
    END
  END f_d[579]
  PIN f_d[57]
    DIRECTION INPUT ;
    USE SIGNAL ;
    PORT
      LAYER M4 ;
        RECT  0 118.8 0.084 118.824 ;
    END
  END f_d[57]
  PIN f_d[580]
    DIRECTION INPUT ;
    USE SIGNAL ;
    PORT
      LAYER M4 ;
        RECT  0 141.264 0.084 141.288 ;
    END
  END f_d[580]
  PIN f_d[581]
    DIRECTION INPUT ;
    USE SIGNAL ;
    PORT
      LAYER M4 ;
        RECT  0 141.456 0.084 141.48 ;
    END
  END f_d[581]
  PIN f_d[582]
    DIRECTION INPUT ;
    USE SIGNAL ;
    PORT
      LAYER M4 ;
        RECT  0 141.648 0.084 141.672 ;
    END
  END f_d[582]
  PIN f_d[583]
    DIRECTION INPUT ;
    USE SIGNAL ;
    PORT
      LAYER M4 ;
        RECT  0 141.84 0.084 141.864 ;
    END
  END f_d[583]
  PIN f_d[584]
    DIRECTION INPUT ;
    USE SIGNAL ;
    PORT
      LAYER M4 ;
        RECT  0 142.032 0.084 142.056 ;
    END
  END f_d[584]
  PIN f_d[585]
    DIRECTION INPUT ;
    USE SIGNAL ;
    PORT
      LAYER M4 ;
        RECT  0 142.224 0.084 142.248 ;
    END
  END f_d[585]
  PIN f_d[586]
    DIRECTION INPUT ;
    USE SIGNAL ;
    PORT
      LAYER M4 ;
        RECT  0 142.416 0.084 142.44 ;
    END
  END f_d[586]
  PIN f_d[587]
    DIRECTION INPUT ;
    USE SIGNAL ;
    PORT
      LAYER M4 ;
        RECT  0 142.608 0.084 142.632 ;
    END
  END f_d[587]
  PIN f_d[588]
    DIRECTION INPUT ;
    USE SIGNAL ;
    PORT
      LAYER M4 ;
        RECT  0 142.8 0.084 142.824 ;
    END
  END f_d[588]
  PIN f_d[589]
    DIRECTION INPUT ;
    USE SIGNAL ;
    PORT
      LAYER M4 ;
        RECT  0 142.992 0.084 143.016 ;
    END
  END f_d[589]
  PIN f_d[58]
    DIRECTION INPUT ;
    USE SIGNAL ;
    PORT
      LAYER M4 ;
        RECT  0 118.992 0.084 119.016 ;
    END
  END f_d[58]
  PIN f_d[590]
    DIRECTION INPUT ;
    USE SIGNAL ;
    PORT
      LAYER M4 ;
        RECT  0 143.184 0.084 143.208 ;
    END
  END f_d[590]
  PIN f_d[591]
    DIRECTION INPUT ;
    USE SIGNAL ;
    PORT
      LAYER M4 ;
        RECT  0 143.376 0.084 143.4 ;
    END
  END f_d[591]
  PIN f_d[592]
    DIRECTION INPUT ;
    USE SIGNAL ;
    PORT
      LAYER M4 ;
        RECT  0 143.568 0.084 143.592 ;
    END
  END f_d[592]
  PIN f_d[593]
    DIRECTION INPUT ;
    USE SIGNAL ;
    PORT
      LAYER M4 ;
        RECT  0 143.76 0.084 143.784 ;
    END
  END f_d[593]
  PIN f_d[594]
    DIRECTION INPUT ;
    USE SIGNAL ;
    PORT
      LAYER M4 ;
        RECT  0 143.952 0.084 143.976 ;
    END
  END f_d[594]
  PIN f_d[595]
    DIRECTION INPUT ;
    USE SIGNAL ;
    PORT
      LAYER M4 ;
        RECT  0 144.144 0.084 144.168 ;
    END
  END f_d[595]
  PIN f_d[596]
    DIRECTION INPUT ;
    USE SIGNAL ;
    PORT
      LAYER M4 ;
        RECT  0 144.336 0.084 144.36 ;
    END
  END f_d[596]
  PIN f_d[597]
    DIRECTION INPUT ;
    USE SIGNAL ;
    PORT
      LAYER M4 ;
        RECT  0 144.528 0.084 144.552 ;
    END
  END f_d[597]
  PIN f_d[598]
    DIRECTION INPUT ;
    USE SIGNAL ;
    PORT
      LAYER M4 ;
        RECT  0 144.72 0.084 144.744 ;
    END
  END f_d[598]
  PIN f_d[599]
    DIRECTION INPUT ;
    USE SIGNAL ;
    PORT
      LAYER M4 ;
        RECT  0 144.912 0.084 144.936 ;
    END
  END f_d[599]
  PIN f_d[59]
    DIRECTION INPUT ;
    USE SIGNAL ;
    PORT
      LAYER M4 ;
        RECT  0 119.184 0.084 119.208 ;
    END
  END f_d[59]
  PIN f_d[5]
    DIRECTION INPUT ;
    USE SIGNAL ;
    PORT
      LAYER M4 ;
        RECT  0 25.872 0.084 25.896 ;
    END
  END f_d[5]
  PIN f_d[600]
    DIRECTION INPUT ;
    USE SIGNAL ;
    PORT
      LAYER M4 ;
        RECT  0 145.104 0.084 145.128 ;
    END
  END f_d[600]
  PIN f_d[601]
    DIRECTION INPUT ;
    USE SIGNAL ;
    PORT
      LAYER M4 ;
        RECT  0 145.296 0.084 145.32 ;
    END
  END f_d[601]
  PIN f_d[602]
    DIRECTION INPUT ;
    USE SIGNAL ;
    PORT
      LAYER M4 ;
        RECT  0 145.488 0.084 145.512 ;
    END
  END f_d[602]
  PIN f_d[603]
    DIRECTION INPUT ;
    USE SIGNAL ;
    PORT
      LAYER M4 ;
        RECT  0 145.68 0.084 145.704 ;
    END
  END f_d[603]
  PIN f_d[604]
    DIRECTION INPUT ;
    USE SIGNAL ;
    PORT
      LAYER M4 ;
        RECT  0 145.872 0.084 145.896 ;
    END
  END f_d[604]
  PIN f_d[605]
    DIRECTION INPUT ;
    USE SIGNAL ;
    PORT
      LAYER M4 ;
        RECT  0 146.064 0.084 146.088 ;
    END
  END f_d[605]
  PIN f_d[606]
    DIRECTION INPUT ;
    USE SIGNAL ;
    PORT
      LAYER M4 ;
        RECT  0 4.944 0.084 4.968 ;
    END
  END f_d[606]
  PIN f_d[607]
    DIRECTION INPUT ;
    USE SIGNAL ;
    PORT
      LAYER M4 ;
        RECT  0 5.136 0.084 5.16 ;
    END
  END f_d[607]
  PIN f_d[608]
    DIRECTION INPUT ;
    USE SIGNAL ;
    PORT
      LAYER M4 ;
        RECT  0 5.328 0.084 5.352 ;
    END
  END f_d[608]
  PIN f_d[609]
    DIRECTION INPUT ;
    USE SIGNAL ;
    PORT
      LAYER M4 ;
        RECT  0 5.52 0.084 5.544 ;
    END
  END f_d[609]
  PIN f_d[60]
    DIRECTION INPUT ;
    USE SIGNAL ;
    PORT
      LAYER M4 ;
        RECT  0 119.376 0.084 119.4 ;
    END
  END f_d[60]
  PIN f_d[610]
    DIRECTION INPUT ;
    USE SIGNAL ;
    PORT
      LAYER M4 ;
        RECT  0 5.712 0.084 5.736 ;
    END
  END f_d[610]
  PIN f_d[611]
    DIRECTION INPUT ;
    USE SIGNAL ;
    PORT
      LAYER M4 ;
        RECT  0 5.904 0.084 5.928 ;
    END
  END f_d[611]
  PIN f_d[612]
    DIRECTION INPUT ;
    USE SIGNAL ;
    PORT
      LAYER M4 ;
        RECT  0 6.096 0.084 6.12 ;
    END
  END f_d[612]
  PIN f_d[613]
    DIRECTION INPUT ;
    USE SIGNAL ;
    PORT
      LAYER M4 ;
        RECT  0 6.288 0.084 6.312 ;
    END
  END f_d[613]
  PIN f_d[614]
    DIRECTION INPUT ;
    USE SIGNAL ;
    PORT
      LAYER M4 ;
        RECT  0 6.48 0.084 6.504 ;
    END
  END f_d[614]
  PIN f_d[615]
    DIRECTION INPUT ;
    USE SIGNAL ;
    PORT
      LAYER M4 ;
        RECT  0 6.672 0.084 6.696 ;
    END
  END f_d[615]
  PIN f_d[616]
    DIRECTION INPUT ;
    USE SIGNAL ;
    PORT
      LAYER M4 ;
        RECT  0 6.864 0.084 6.888 ;
    END
  END f_d[616]
  PIN f_d[617]
    DIRECTION INPUT ;
    USE SIGNAL ;
    PORT
      LAYER M4 ;
        RECT  0 7.056 0.084 7.08 ;
    END
  END f_d[617]
  PIN f_d[618]
    DIRECTION INPUT ;
    USE SIGNAL ;
    PORT
      LAYER M4 ;
        RECT  0 7.248 0.084 7.272 ;
    END
  END f_d[618]
  PIN f_d[619]
    DIRECTION INPUT ;
    USE SIGNAL ;
    PORT
      LAYER M4 ;
        RECT  0 7.44 0.084 7.464 ;
    END
  END f_d[619]
  PIN f_d[61]
    DIRECTION INPUT ;
    USE SIGNAL ;
    PORT
      LAYER M4 ;
        RECT  0 119.568 0.084 119.592 ;
    END
  END f_d[61]
  PIN f_d[620]
    DIRECTION INPUT ;
    USE SIGNAL ;
    PORT
      LAYER M4 ;
        RECT  0 7.632 0.084 7.656 ;
    END
  END f_d[620]
  PIN f_d[621]
    DIRECTION INPUT ;
    USE SIGNAL ;
    PORT
      LAYER M4 ;
        RECT  0 7.824 0.084 7.848 ;
    END
  END f_d[621]
  PIN f_d[622]
    DIRECTION INPUT ;
    USE SIGNAL ;
    PORT
      LAYER M4 ;
        RECT  0 8.016 0.084 8.04 ;
    END
  END f_d[622]
  PIN f_d[623]
    DIRECTION INPUT ;
    USE SIGNAL ;
    PORT
      LAYER M4 ;
        RECT  0 8.208 0.084 8.232 ;
    END
  END f_d[623]
  PIN f_d[624]
    DIRECTION INPUT ;
    USE SIGNAL ;
    PORT
      LAYER M4 ;
        RECT  0 8.4 0.084 8.424 ;
    END
  END f_d[624]
  PIN f_d[625]
    DIRECTION INPUT ;
    USE SIGNAL ;
    PORT
      LAYER M4 ;
        RECT  0 8.592 0.084 8.616 ;
    END
  END f_d[625]
  PIN f_d[626]
    DIRECTION INPUT ;
    USE SIGNAL ;
    PORT
      LAYER M4 ;
        RECT  0 8.784 0.084 8.808 ;
    END
  END f_d[626]
  PIN f_d[627]
    DIRECTION INPUT ;
    USE SIGNAL ;
    PORT
      LAYER M4 ;
        RECT  0 8.976 0.084 9 ;
    END
  END f_d[627]
  PIN f_d[628]
    DIRECTION INPUT ;
    USE SIGNAL ;
    PORT
      LAYER M4 ;
        RECT  0 9.168 0.084 9.192 ;
    END
  END f_d[628]
  PIN f_d[629]
    DIRECTION INPUT ;
    USE SIGNAL ;
    PORT
      LAYER M4 ;
        RECT  0 9.36 0.084 9.384 ;
    END
  END f_d[629]
  PIN f_d[62]
    DIRECTION INPUT ;
    USE SIGNAL ;
    PORT
      LAYER M4 ;
        RECT  0 119.76 0.084 119.784 ;
    END
  END f_d[62]
  PIN f_d[630]
    DIRECTION INPUT ;
    USE SIGNAL ;
    PORT
      LAYER M4 ;
        RECT  0 9.552 0.084 9.576 ;
    END
  END f_d[630]
  PIN f_d[631]
    DIRECTION INPUT ;
    USE SIGNAL ;
    PORT
      LAYER M4 ;
        RECT  0 9.744 0.084 9.768 ;
    END
  END f_d[631]
  PIN f_d[632]
    DIRECTION INPUT ;
    USE SIGNAL ;
    PORT
      LAYER M4 ;
        RECT  0 9.936 0.084 9.96 ;
    END
  END f_d[632]
  PIN f_d[633]
    DIRECTION INPUT ;
    USE SIGNAL ;
    PORT
      LAYER M4 ;
        RECT  0 10.128 0.084 10.152 ;
    END
  END f_d[633]
  PIN f_d[634]
    DIRECTION INPUT ;
    USE SIGNAL ;
    PORT
      LAYER M4 ;
        RECT  0 10.32 0.084 10.344 ;
    END
  END f_d[634]
  PIN f_d[635]
    DIRECTION INPUT ;
    USE SIGNAL ;
    PORT
      LAYER M4 ;
        RECT  0 10.512 0.084 10.536 ;
    END
  END f_d[635]
  PIN f_d[636]
    DIRECTION INPUT ;
    USE SIGNAL ;
    PORT
      LAYER M4 ;
        RECT  0 10.704 0.084 10.728 ;
    END
  END f_d[636]
  PIN f_d[637]
    DIRECTION INPUT ;
    USE SIGNAL ;
    PORT
      LAYER M4 ;
        RECT  0 10.896 0.084 10.92 ;
    END
  END f_d[637]
  PIN f_d[638]
    DIRECTION INPUT ;
    USE SIGNAL ;
    PORT
      LAYER M4 ;
        RECT  0 17.232 0.084 17.256 ;
    END
  END f_d[638]
  PIN f_d[639]
    DIRECTION INPUT ;
    USE SIGNAL ;
    PORT
      LAYER M4 ;
        RECT  0 17.424 0.084 17.448 ;
    END
  END f_d[639]
  PIN f_d[63]
    DIRECTION INPUT ;
    USE SIGNAL ;
    PORT
      LAYER M4 ;
        RECT  0 119.952 0.084 119.976 ;
    END
  END f_d[63]
  PIN f_d[640]
    DIRECTION INPUT ;
    USE SIGNAL ;
    PORT
      LAYER M4 ;
        RECT  0 17.616 0.084 17.64 ;
    END
  END f_d[640]
  PIN f_d[641]
    DIRECTION INPUT ;
    USE SIGNAL ;
    PORT
      LAYER M4 ;
        RECT  0 17.808 0.084 17.832 ;
    END
  END f_d[641]
  PIN f_d[642]
    DIRECTION INPUT ;
    USE SIGNAL ;
    PORT
      LAYER M4 ;
        RECT  0 18 0.084 18.024 ;
    END
  END f_d[642]
  PIN f_d[643]
    DIRECTION INPUT ;
    USE SIGNAL ;
    PORT
      LAYER M4 ;
        RECT  0 18.192 0.084 18.216 ;
    END
  END f_d[643]
  PIN f_d[644]
    DIRECTION INPUT ;
    USE SIGNAL ;
    PORT
      LAYER M4 ;
        RECT  0 18.384 0.084 18.408 ;
    END
  END f_d[644]
  PIN f_d[645]
    DIRECTION INPUT ;
    USE SIGNAL ;
    PORT
      LAYER M4 ;
        RECT  0 18.576 0.084 18.6 ;
    END
  END f_d[645]
  PIN f_d[646]
    DIRECTION INPUT ;
    USE SIGNAL ;
    PORT
      LAYER M4 ;
        RECT  0 18.768 0.084 18.792 ;
    END
  END f_d[646]
  PIN f_d[647]
    DIRECTION INPUT ;
    USE SIGNAL ;
    PORT
      LAYER M4 ;
        RECT  0 18.96 0.084 18.984 ;
    END
  END f_d[647]
  PIN f_d[648]
    DIRECTION INPUT ;
    USE SIGNAL ;
    PORT
      LAYER M4 ;
        RECT  0 19.152 0.084 19.176 ;
    END
  END f_d[648]
  PIN f_d[649]
    DIRECTION INPUT ;
    USE SIGNAL ;
    PORT
      LAYER M4 ;
        RECT  0 19.344 0.084 19.368 ;
    END
  END f_d[649]
  PIN f_d[64]
    DIRECTION INPUT ;
    USE SIGNAL ;
    PORT
      LAYER M4 ;
        RECT  0 158.544 0.084 158.568 ;
    END
  END f_d[64]
  PIN f_d[650]
    DIRECTION INPUT ;
    USE SIGNAL ;
    PORT
      LAYER M4 ;
        RECT  0 19.536 0.084 19.56 ;
    END
  END f_d[650]
  PIN f_d[651]
    DIRECTION INPUT ;
    USE SIGNAL ;
    PORT
      LAYER M4 ;
        RECT  0 19.728 0.084 19.752 ;
    END
  END f_d[651]
  PIN f_d[652]
    DIRECTION INPUT ;
    USE SIGNAL ;
    PORT
      LAYER M4 ;
        RECT  0 19.92 0.084 19.944 ;
    END
  END f_d[652]
  PIN f_d[653]
    DIRECTION INPUT ;
    USE SIGNAL ;
    PORT
      LAYER M4 ;
        RECT  0 20.112 0.084 20.136 ;
    END
  END f_d[653]
  PIN f_d[654]
    DIRECTION INPUT ;
    USE SIGNAL ;
    PORT
      LAYER M4 ;
        RECT  0 20.304 0.084 20.328 ;
    END
  END f_d[654]
  PIN f_d[655]
    DIRECTION INPUT ;
    USE SIGNAL ;
    PORT
      LAYER M4 ;
        RECT  0 20.496 0.084 20.52 ;
    END
  END f_d[655]
  PIN f_d[656]
    DIRECTION INPUT ;
    USE SIGNAL ;
    PORT
      LAYER M4 ;
        RECT  0 20.688 0.084 20.712 ;
    END
  END f_d[656]
  PIN f_d[657]
    DIRECTION INPUT ;
    USE SIGNAL ;
    PORT
      LAYER M4 ;
        RECT  0 20.88 0.084 20.904 ;
    END
  END f_d[657]
  PIN f_d[658]
    DIRECTION INPUT ;
    USE SIGNAL ;
    PORT
      LAYER M4 ;
        RECT  0 21.072 0.084 21.096 ;
    END
  END f_d[658]
  PIN f_d[659]
    DIRECTION INPUT ;
    USE SIGNAL ;
    PORT
      LAYER M4 ;
        RECT  0 21.264 0.084 21.288 ;
    END
  END f_d[659]
  PIN f_d[65]
    DIRECTION INPUT ;
    USE SIGNAL ;
    PORT
      LAYER M4 ;
        RECT  0 158.736 0.084 158.76 ;
    END
  END f_d[65]
  PIN f_d[660]
    DIRECTION INPUT ;
    USE SIGNAL ;
    PORT
      LAYER M4 ;
        RECT  0 21.456 0.084 21.48 ;
    END
  END f_d[660]
  PIN f_d[661]
    DIRECTION INPUT ;
    USE SIGNAL ;
    PORT
      LAYER M4 ;
        RECT  0 21.648 0.084 21.672 ;
    END
  END f_d[661]
  PIN f_d[662]
    DIRECTION INPUT ;
    USE SIGNAL ;
    PORT
      LAYER M4 ;
        RECT  0 21.84 0.084 21.864 ;
    END
  END f_d[662]
  PIN f_d[663]
    DIRECTION INPUT ;
    USE SIGNAL ;
    PORT
      LAYER M4 ;
        RECT  0 22.032 0.084 22.056 ;
    END
  END f_d[663]
  PIN f_d[664]
    DIRECTION INPUT ;
    USE SIGNAL ;
    PORT
      LAYER M4 ;
        RECT  0 22.224 0.084 22.248 ;
    END
  END f_d[664]
  PIN f_d[665]
    DIRECTION INPUT ;
    USE SIGNAL ;
    PORT
      LAYER M4 ;
        RECT  0 22.416 0.084 22.44 ;
    END
  END f_d[665]
  PIN f_d[666]
    DIRECTION INPUT ;
    USE SIGNAL ;
    PORT
      LAYER M4 ;
        RECT  0 22.608 0.084 22.632 ;
    END
  END f_d[666]
  PIN f_d[667]
    DIRECTION INPUT ;
    USE SIGNAL ;
    PORT
      LAYER M4 ;
        RECT  0 22.8 0.084 22.824 ;
    END
  END f_d[667]
  PIN f_d[668]
    DIRECTION INPUT ;
    USE SIGNAL ;
    PORT
      LAYER M4 ;
        RECT  0 22.992 0.084 23.016 ;
    END
  END f_d[668]
  PIN f_d[669]
    DIRECTION INPUT ;
    USE SIGNAL ;
    PORT
      LAYER M4 ;
        RECT  0 23.184 0.084 23.208 ;
    END
  END f_d[669]
  PIN f_d[66]
    DIRECTION INPUT ;
    USE SIGNAL ;
    PORT
      LAYER M4 ;
        RECT  0 158.928 0.084 158.952 ;
    END
  END f_d[66]
  PIN f_d[670]
    DIRECTION INPUT ;
    USE SIGNAL ;
    PORT
      LAYER M4 ;
        RECT  0 81.744 0.084 81.768 ;
    END
  END f_d[670]
  PIN f_d[671]
    DIRECTION INPUT ;
    USE SIGNAL ;
    PORT
      LAYER M4 ;
        RECT  0 81.936 0.084 81.96 ;
    END
  END f_d[671]
  PIN f_d[672]
    DIRECTION INPUT ;
    USE SIGNAL ;
    PORT
      LAYER M4 ;
        RECT  0 82.128 0.084 82.152 ;
    END
  END f_d[672]
  PIN f_d[673]
    DIRECTION INPUT ;
    USE SIGNAL ;
    PORT
      LAYER M4 ;
        RECT  0 82.32 0.084 82.344 ;
    END
  END f_d[673]
  PIN f_d[674]
    DIRECTION INPUT ;
    USE SIGNAL ;
    PORT
      LAYER M4 ;
        RECT  0 82.512 0.084 82.536 ;
    END
  END f_d[674]
  PIN f_d[675]
    DIRECTION INPUT ;
    USE SIGNAL ;
    PORT
      LAYER M4 ;
        RECT  0 82.704 0.084 82.728 ;
    END
  END f_d[675]
  PIN f_d[676]
    DIRECTION INPUT ;
    USE SIGNAL ;
    PORT
      LAYER M4 ;
        RECT  0 82.896 0.084 82.92 ;
    END
  END f_d[676]
  PIN f_d[677]
    DIRECTION INPUT ;
    USE SIGNAL ;
    PORT
      LAYER M4 ;
        RECT  0 83.088 0.084 83.112 ;
    END
  END f_d[677]
  PIN f_d[678]
    DIRECTION INPUT ;
    USE SIGNAL ;
    PORT
      LAYER M4 ;
        RECT  0 83.28 0.084 83.304 ;
    END
  END f_d[678]
  PIN f_d[679]
    DIRECTION INPUT ;
    USE SIGNAL ;
    PORT
      LAYER M4 ;
        RECT  0 83.472 0.084 83.496 ;
    END
  END f_d[679]
  PIN f_d[67]
    DIRECTION INPUT ;
    USE SIGNAL ;
    PORT
      LAYER M4 ;
        RECT  0 159.12 0.084 159.144 ;
    END
  END f_d[67]
  PIN f_d[680]
    DIRECTION INPUT ;
    USE SIGNAL ;
    PORT
      LAYER M4 ;
        RECT  0 83.664 0.084 83.688 ;
    END
  END f_d[680]
  PIN f_d[681]
    DIRECTION INPUT ;
    USE SIGNAL ;
    PORT
      LAYER M4 ;
        RECT  0 83.856 0.084 83.88 ;
    END
  END f_d[681]
  PIN f_d[682]
    DIRECTION INPUT ;
    USE SIGNAL ;
    PORT
      LAYER M4 ;
        RECT  0 84.048 0.084 84.072 ;
    END
  END f_d[682]
  PIN f_d[683]
    DIRECTION INPUT ;
    USE SIGNAL ;
    PORT
      LAYER M4 ;
        RECT  0 84.24 0.084 84.264 ;
    END
  END f_d[683]
  PIN f_d[684]
    DIRECTION INPUT ;
    USE SIGNAL ;
    PORT
      LAYER M4 ;
        RECT  0 84.432 0.084 84.456 ;
    END
  END f_d[684]
  PIN f_d[685]
    DIRECTION INPUT ;
    USE SIGNAL ;
    PORT
      LAYER M4 ;
        RECT  0 84.624 0.084 84.648 ;
    END
  END f_d[685]
  PIN f_d[686]
    DIRECTION INPUT ;
    USE SIGNAL ;
    PORT
      LAYER M4 ;
        RECT  0 84.816 0.084 84.84 ;
    END
  END f_d[686]
  PIN f_d[687]
    DIRECTION INPUT ;
    USE SIGNAL ;
    PORT
      LAYER M4 ;
        RECT  0 85.008 0.084 85.032 ;
    END
  END f_d[687]
  PIN f_d[688]
    DIRECTION INPUT ;
    USE SIGNAL ;
    PORT
      LAYER M4 ;
        RECT  0 85.2 0.084 85.224 ;
    END
  END f_d[688]
  PIN f_d[689]
    DIRECTION INPUT ;
    USE SIGNAL ;
    PORT
      LAYER M4 ;
        RECT  0 85.392 0.084 85.416 ;
    END
  END f_d[689]
  PIN f_d[68]
    DIRECTION INPUT ;
    USE SIGNAL ;
    PORT
      LAYER M4 ;
        RECT  0 159.312 0.084 159.336 ;
    END
  END f_d[68]
  PIN f_d[690]
    DIRECTION INPUT ;
    USE SIGNAL ;
    PORT
      LAYER M4 ;
        RECT  0 85.584 0.084 85.608 ;
    END
  END f_d[690]
  PIN f_d[691]
    DIRECTION INPUT ;
    USE SIGNAL ;
    PORT
      LAYER M4 ;
        RECT  0 85.776 0.084 85.8 ;
    END
  END f_d[691]
  PIN f_d[692]
    DIRECTION INPUT ;
    USE SIGNAL ;
    PORT
      LAYER M4 ;
        RECT  0 85.968 0.084 85.992 ;
    END
  END f_d[692]
  PIN f_d[693]
    DIRECTION INPUT ;
    USE SIGNAL ;
    PORT
      LAYER M4 ;
        RECT  0 86.16 0.084 86.184 ;
    END
  END f_d[693]
  PIN f_d[694]
    DIRECTION INPUT ;
    USE SIGNAL ;
    PORT
      LAYER M4 ;
        RECT  0 86.352 0.084 86.376 ;
    END
  END f_d[694]
  PIN f_d[695]
    DIRECTION INPUT ;
    USE SIGNAL ;
    PORT
      LAYER M4 ;
        RECT  0 86.736 0.084 86.76 ;
    END
  END f_d[695]
  PIN f_d[696]
    DIRECTION INPUT ;
    USE SIGNAL ;
    PORT
      LAYER M4 ;
        RECT  0 86.928 0.084 86.952 ;
    END
  END f_d[696]
  PIN f_d[697]
    DIRECTION INPUT ;
    USE SIGNAL ;
    PORT
      LAYER M4 ;
        RECT  0 87.12 0.084 87.144 ;
    END
  END f_d[697]
  PIN f_d[698]
    DIRECTION INPUT ;
    USE SIGNAL ;
    PORT
      LAYER M4 ;
        RECT  0 87.312 0.084 87.336 ;
    END
  END f_d[698]
  PIN f_d[699]
    DIRECTION INPUT ;
    USE SIGNAL ;
    PORT
      LAYER M4 ;
        RECT  0 87.504 0.084 87.528 ;
    END
  END f_d[699]
  PIN f_d[69]
    DIRECTION INPUT ;
    USE SIGNAL ;
    PORT
      LAYER M4 ;
        RECT  0 159.504 0.084 159.528 ;
    END
  END f_d[69]
  PIN f_d[6]
    DIRECTION INPUT ;
    USE SIGNAL ;
    PORT
      LAYER M4 ;
        RECT  0 26.064 0.084 26.088 ;
    END
  END f_d[6]
  PIN f_d[700]
    DIRECTION INPUT ;
    USE SIGNAL ;
    PORT
      LAYER M4 ;
        RECT  0 87.696 0.084 87.72 ;
    END
  END f_d[700]
  PIN f_d[701]
    DIRECTION INPUT ;
    USE SIGNAL ;
    PORT
      LAYER M4 ;
        RECT  0 132.432 0.084 132.456 ;
    END
  END f_d[701]
  PIN f_d[702]
    DIRECTION INPUT ;
    USE SIGNAL ;
    PORT
      LAYER M4 ;
        RECT  0 132.624 0.084 132.648 ;
    END
  END f_d[702]
  PIN f_d[703]
    DIRECTION INPUT ;
    USE SIGNAL ;
    PORT
      LAYER M4 ;
        RECT  0 132.816 0.084 132.84 ;
    END
  END f_d[703]
  PIN f_d[704]
    DIRECTION INPUT ;
    USE SIGNAL ;
    PORT
      LAYER M4 ;
        RECT  0 133.008 0.084 133.032 ;
    END
  END f_d[704]
  PIN f_d[705]
    DIRECTION INPUT ;
    USE SIGNAL ;
    PORT
      LAYER M4 ;
        RECT  0 133.2 0.084 133.224 ;
    END
  END f_d[705]
  PIN f_d[706]
    DIRECTION INPUT ;
    USE SIGNAL ;
    PORT
      LAYER M4 ;
        RECT  0 133.392 0.084 133.416 ;
    END
  END f_d[706]
  PIN f_d[707]
    DIRECTION INPUT ;
    USE SIGNAL ;
    PORT
      LAYER M4 ;
        RECT  0 133.584 0.084 133.608 ;
    END
  END f_d[707]
  PIN f_d[708]
    DIRECTION INPUT ;
    USE SIGNAL ;
    PORT
      LAYER M4 ;
        RECT  0 133.776 0.084 133.8 ;
    END
  END f_d[708]
  PIN f_d[709]
    DIRECTION INPUT ;
    USE SIGNAL ;
    PORT
      LAYER M4 ;
        RECT  0 133.968 0.084 133.992 ;
    END
  END f_d[709]
  PIN f_d[70]
    DIRECTION INPUT ;
    USE SIGNAL ;
    PORT
      LAYER M4 ;
        RECT  0 159.696 0.084 159.72 ;
    END
  END f_d[70]
  PIN f_d[710]
    DIRECTION INPUT ;
    USE SIGNAL ;
    PORT
      LAYER M4 ;
        RECT  0 134.16 0.084 134.184 ;
    END
  END f_d[710]
  PIN f_d[711]
    DIRECTION INPUT ;
    USE SIGNAL ;
    PORT
      LAYER M4 ;
        RECT  0 134.352 0.084 134.376 ;
    END
  END f_d[711]
  PIN f_d[712]
    DIRECTION INPUT ;
    USE SIGNAL ;
    PORT
      LAYER M4 ;
        RECT  0 134.544 0.084 134.568 ;
    END
  END f_d[712]
  PIN f_d[713]
    DIRECTION INPUT ;
    USE SIGNAL ;
    PORT
      LAYER M4 ;
        RECT  0 134.736 0.084 134.76 ;
    END
  END f_d[713]
  PIN f_d[714]
    DIRECTION INPUT ;
    USE SIGNAL ;
    PORT
      LAYER M4 ;
        RECT  0 134.928 0.084 134.952 ;
    END
  END f_d[714]
  PIN f_d[715]
    DIRECTION INPUT ;
    USE SIGNAL ;
    PORT
      LAYER M4 ;
        RECT  0 135.12 0.084 135.144 ;
    END
  END f_d[715]
  PIN f_d[716]
    DIRECTION INPUT ;
    USE SIGNAL ;
    PORT
      LAYER M4 ;
        RECT  0 135.312 0.084 135.336 ;
    END
  END f_d[716]
  PIN f_d[717]
    DIRECTION INPUT ;
    USE SIGNAL ;
    PORT
      LAYER M4 ;
        RECT  0 135.504 0.084 135.528 ;
    END
  END f_d[717]
  PIN f_d[718]
    DIRECTION INPUT ;
    USE SIGNAL ;
    PORT
      LAYER M4 ;
        RECT  0 135.696 0.084 135.72 ;
    END
  END f_d[718]
  PIN f_d[719]
    DIRECTION INPUT ;
    USE SIGNAL ;
    PORT
      LAYER M4 ;
        RECT  0 135.888 0.084 135.912 ;
    END
  END f_d[719]
  PIN f_d[71]
    DIRECTION INPUT ;
    USE SIGNAL ;
    PORT
      LAYER M4 ;
        RECT  0 159.888 0.084 159.912 ;
    END
  END f_d[71]
  PIN f_d[720]
    DIRECTION INPUT ;
    USE SIGNAL ;
    PORT
      LAYER M4 ;
        RECT  0 136.08 0.084 136.104 ;
    END
  END f_d[720]
  PIN f_d[721]
    DIRECTION INPUT ;
    USE SIGNAL ;
    PORT
      LAYER M4 ;
        RECT  0 136.272 0.084 136.296 ;
    END
  END f_d[721]
  PIN f_d[722]
    DIRECTION INPUT ;
    USE SIGNAL ;
    PORT
      LAYER M4 ;
        RECT  0 136.464 0.084 136.488 ;
    END
  END f_d[722]
  PIN f_d[723]
    DIRECTION INPUT ;
    USE SIGNAL ;
    PORT
      LAYER M4 ;
        RECT  0 136.656 0.084 136.68 ;
    END
  END f_d[723]
  PIN f_d[724]
    DIRECTION INPUT ;
    USE SIGNAL ;
    PORT
      LAYER M4 ;
        RECT  0 136.848 0.084 136.872 ;
    END
  END f_d[724]
  PIN f_d[725]
    DIRECTION INPUT ;
    USE SIGNAL ;
    PORT
      LAYER M4 ;
        RECT  0 137.04 0.084 137.064 ;
    END
  END f_d[725]
  PIN f_d[726]
    DIRECTION INPUT ;
    USE SIGNAL ;
    PORT
      LAYER M4 ;
        RECT  0 137.232 0.084 137.256 ;
    END
  END f_d[726]
  PIN f_d[727]
    DIRECTION INPUT ;
    USE SIGNAL ;
    PORT
      LAYER M4 ;
        RECT  0 137.424 0.084 137.448 ;
    END
  END f_d[727]
  PIN f_d[728]
    DIRECTION INPUT ;
    USE SIGNAL ;
    PORT
      LAYER M4 ;
        RECT  0 137.616 0.084 137.64 ;
    END
  END f_d[728]
  PIN f_d[729]
    DIRECTION INPUT ;
    USE SIGNAL ;
    PORT
      LAYER M4 ;
        RECT  0 137.808 0.084 137.832 ;
    END
  END f_d[729]
  PIN f_d[72]
    DIRECTION INPUT ;
    USE SIGNAL ;
    PORT
      LAYER M4 ;
        RECT  0 160.08 0.084 160.104 ;
    END
  END f_d[72]
  PIN f_d[730]
    DIRECTION INPUT ;
    USE SIGNAL ;
    PORT
      LAYER M4 ;
        RECT  0 138 0.084 138.024 ;
    END
  END f_d[730]
  PIN f_d[731]
    DIRECTION INPUT ;
    USE SIGNAL ;
    PORT
      LAYER M4 ;
        RECT  0 138.192 0.084 138.216 ;
    END
  END f_d[731]
  PIN f_d[732]
    DIRECTION INPUT ;
    USE SIGNAL ;
    PORT
      LAYER M4 ;
        RECT  0 138.384 0.084 138.408 ;
    END
  END f_d[732]
  PIN f_d[733]
    DIRECTION INPUT ;
    USE SIGNAL ;
    PORT
      LAYER M4 ;
        RECT  0 75.6 0.084 75.624 ;
    END
  END f_d[733]
  PIN f_d[734]
    DIRECTION INPUT ;
    USE SIGNAL ;
    PORT
      LAYER M4 ;
        RECT  0 75.792 0.084 75.816 ;
    END
  END f_d[734]
  PIN f_d[735]
    DIRECTION INPUT ;
    USE SIGNAL ;
    PORT
      LAYER M4 ;
        RECT  0 75.984 0.084 76.008 ;
    END
  END f_d[735]
  PIN f_d[736]
    DIRECTION INPUT ;
    USE SIGNAL ;
    PORT
      LAYER M4 ;
        RECT  0 76.176 0.084 76.2 ;
    END
  END f_d[736]
  PIN f_d[737]
    DIRECTION INPUT ;
    USE SIGNAL ;
    PORT
      LAYER M4 ;
        RECT  0 76.368 0.084 76.392 ;
    END
  END f_d[737]
  PIN f_d[738]
    DIRECTION INPUT ;
    USE SIGNAL ;
    PORT
      LAYER M4 ;
        RECT  0 76.56 0.084 76.584 ;
    END
  END f_d[738]
  PIN f_d[739]
    DIRECTION INPUT ;
    USE SIGNAL ;
    PORT
      LAYER M4 ;
        RECT  0 76.752 0.084 76.776 ;
    END
  END f_d[739]
  PIN f_d[73]
    DIRECTION INPUT ;
    USE SIGNAL ;
    PORT
      LAYER M4 ;
        RECT  0 160.272 0.084 160.296 ;
    END
  END f_d[73]
  PIN f_d[740]
    DIRECTION INPUT ;
    USE SIGNAL ;
    PORT
      LAYER M4 ;
        RECT  0 76.944 0.084 76.968 ;
    END
  END f_d[740]
  PIN f_d[741]
    DIRECTION INPUT ;
    USE SIGNAL ;
    PORT
      LAYER M4 ;
        RECT  0 77.136 0.084 77.16 ;
    END
  END f_d[741]
  PIN f_d[742]
    DIRECTION INPUT ;
    USE SIGNAL ;
    PORT
      LAYER M4 ;
        RECT  0 77.328 0.084 77.352 ;
    END
  END f_d[742]
  PIN f_d[743]
    DIRECTION INPUT ;
    USE SIGNAL ;
    PORT
      LAYER M4 ;
        RECT  0 77.52 0.084 77.544 ;
    END
  END f_d[743]
  PIN f_d[744]
    DIRECTION INPUT ;
    USE SIGNAL ;
    PORT
      LAYER M4 ;
        RECT  0 77.712 0.084 77.736 ;
    END
  END f_d[744]
  PIN f_d[745]
    DIRECTION INPUT ;
    USE SIGNAL ;
    PORT
      LAYER M4 ;
        RECT  0 77.904 0.084 77.928 ;
    END
  END f_d[745]
  PIN f_d[746]
    DIRECTION INPUT ;
    USE SIGNAL ;
    PORT
      LAYER M4 ;
        RECT  0 78.096 0.084 78.12 ;
    END
  END f_d[746]
  PIN f_d[747]
    DIRECTION INPUT ;
    USE SIGNAL ;
    PORT
      LAYER M4 ;
        RECT  0 78.288 0.084 78.312 ;
    END
  END f_d[747]
  PIN f_d[748]
    DIRECTION INPUT ;
    USE SIGNAL ;
    PORT
      LAYER M4 ;
        RECT  0 78.48 0.084 78.504 ;
    END
  END f_d[748]
  PIN f_d[749]
    DIRECTION INPUT ;
    USE SIGNAL ;
    PORT
      LAYER M4 ;
        RECT  0 78.672 0.084 78.696 ;
    END
  END f_d[749]
  PIN f_d[74]
    DIRECTION INPUT ;
    USE SIGNAL ;
    PORT
      LAYER M4 ;
        RECT  0 160.464 0.084 160.488 ;
    END
  END f_d[74]
  PIN f_d[750]
    DIRECTION INPUT ;
    USE SIGNAL ;
    PORT
      LAYER M4 ;
        RECT  0 78.864 0.084 78.888 ;
    END
  END f_d[750]
  PIN f_d[751]
    DIRECTION INPUT ;
    USE SIGNAL ;
    PORT
      LAYER M4 ;
        RECT  0 79.056 0.084 79.08 ;
    END
  END f_d[751]
  PIN f_d[752]
    DIRECTION INPUT ;
    USE SIGNAL ;
    PORT
      LAYER M4 ;
        RECT  0 79.248 0.084 79.272 ;
    END
  END f_d[752]
  PIN f_d[753]
    DIRECTION INPUT ;
    USE SIGNAL ;
    PORT
      LAYER M4 ;
        RECT  0 79.44 0.084 79.464 ;
    END
  END f_d[753]
  PIN f_d[754]
    DIRECTION INPUT ;
    USE SIGNAL ;
    PORT
      LAYER M4 ;
        RECT  0 79.632 0.084 79.656 ;
    END
  END f_d[754]
  PIN f_d[755]
    DIRECTION INPUT ;
    USE SIGNAL ;
    PORT
      LAYER M4 ;
        RECT  0 79.824 0.084 79.848 ;
    END
  END f_d[755]
  PIN f_d[756]
    DIRECTION INPUT ;
    USE SIGNAL ;
    PORT
      LAYER M4 ;
        RECT  0 80.016 0.084 80.04 ;
    END
  END f_d[756]
  PIN f_d[757]
    DIRECTION INPUT ;
    USE SIGNAL ;
    PORT
      LAYER M4 ;
        RECT  0 80.208 0.084 80.232 ;
    END
  END f_d[757]
  PIN f_d[758]
    DIRECTION INPUT ;
    USE SIGNAL ;
    PORT
      LAYER M4 ;
        RECT  0 80.4 0.084 80.424 ;
    END
  END f_d[758]
  PIN f_d[759]
    DIRECTION INPUT ;
    USE SIGNAL ;
    PORT
      LAYER M4 ;
        RECT  0 80.592 0.084 80.616 ;
    END
  END f_d[759]
  PIN f_d[75]
    DIRECTION INPUT ;
    USE SIGNAL ;
    PORT
      LAYER M4 ;
        RECT  0 160.656 0.084 160.68 ;
    END
  END f_d[75]
  PIN f_d[760]
    DIRECTION INPUT ;
    USE SIGNAL ;
    PORT
      LAYER M4 ;
        RECT  0 80.784 0.084 80.808 ;
    END
  END f_d[760]
  PIN f_d[761]
    DIRECTION INPUT ;
    USE SIGNAL ;
    PORT
      LAYER M4 ;
        RECT  0 80.976 0.084 81 ;
    END
  END f_d[761]
  PIN f_d[762]
    DIRECTION INPUT ;
    USE SIGNAL ;
    PORT
      LAYER M4 ;
        RECT  0 81.168 0.084 81.192 ;
    END
  END f_d[762]
  PIN f_d[763]
    DIRECTION INPUT ;
    USE SIGNAL ;
    PORT
      LAYER M4 ;
        RECT  0 81.36 0.084 81.384 ;
    END
  END f_d[763]
  PIN f_d[764]
    DIRECTION INPUT ;
    USE SIGNAL ;
    PORT
      LAYER M4 ;
        RECT  0 81.552 0.084 81.576 ;
    END
  END f_d[764]
  PIN f_d[765]
    DIRECTION INPUT ;
    USE SIGNAL ;
    PORT
      LAYER M4 ;
        RECT  0 94.032 0.084 94.056 ;
    END
  END f_d[765]
  PIN f_d[766]
    DIRECTION INPUT ;
    USE SIGNAL ;
    PORT
      LAYER M4 ;
        RECT  0 94.224 0.084 94.248 ;
    END
  END f_d[766]
  PIN f_d[767]
    DIRECTION INPUT ;
    USE SIGNAL ;
    PORT
      LAYER M4 ;
        RECT  0 94.416 0.084 94.44 ;
    END
  END f_d[767]
  PIN f_d[768]
    DIRECTION INPUT ;
    USE SIGNAL ;
    PORT
      LAYER M4 ;
        RECT  0 94.608 0.084 94.632 ;
    END
  END f_d[768]
  PIN f_d[769]
    DIRECTION INPUT ;
    USE SIGNAL ;
    PORT
      LAYER M4 ;
        RECT  0 94.8 0.084 94.824 ;
    END
  END f_d[769]
  PIN f_d[76]
    DIRECTION INPUT ;
    USE SIGNAL ;
    PORT
      LAYER M4 ;
        RECT  0 160.848 0.084 160.872 ;
    END
  END f_d[76]
  PIN f_d[770]
    DIRECTION INPUT ;
    USE SIGNAL ;
    PORT
      LAYER M4 ;
        RECT  0 94.992 0.084 95.016 ;
    END
  END f_d[770]
  PIN f_d[771]
    DIRECTION INPUT ;
    USE SIGNAL ;
    PORT
      LAYER M4 ;
        RECT  0 95.184 0.084 95.208 ;
    END
  END f_d[771]
  PIN f_d[772]
    DIRECTION INPUT ;
    USE SIGNAL ;
    PORT
      LAYER M4 ;
        RECT  0 95.376 0.084 95.4 ;
    END
  END f_d[772]
  PIN f_d[773]
    DIRECTION INPUT ;
    USE SIGNAL ;
    PORT
      LAYER M4 ;
        RECT  0 95.568 0.084 95.592 ;
    END
  END f_d[773]
  PIN f_d[774]
    DIRECTION INPUT ;
    USE SIGNAL ;
    PORT
      LAYER M4 ;
        RECT  0 95.76 0.084 95.784 ;
    END
  END f_d[774]
  PIN f_d[775]
    DIRECTION INPUT ;
    USE SIGNAL ;
    PORT
      LAYER M4 ;
        RECT  0 95.952 0.084 95.976 ;
    END
  END f_d[775]
  PIN f_d[776]
    DIRECTION INPUT ;
    USE SIGNAL ;
    PORT
      LAYER M4 ;
        RECT  0 96.144 0.084 96.168 ;
    END
  END f_d[776]
  PIN f_d[777]
    DIRECTION INPUT ;
    USE SIGNAL ;
    PORT
      LAYER M4 ;
        RECT  0 96.336 0.084 96.36 ;
    END
  END f_d[777]
  PIN f_d[778]
    DIRECTION INPUT ;
    USE SIGNAL ;
    PORT
      LAYER M4 ;
        RECT  0 96.528 0.084 96.552 ;
    END
  END f_d[778]
  PIN f_d[779]
    DIRECTION INPUT ;
    USE SIGNAL ;
    PORT
      LAYER M4 ;
        RECT  0 96.72 0.084 96.744 ;
    END
  END f_d[779]
  PIN f_d[77]
    DIRECTION INPUT ;
    USE SIGNAL ;
    PORT
      LAYER M4 ;
        RECT  0 161.04 0.084 161.064 ;
    END
  END f_d[77]
  PIN f_d[780]
    DIRECTION INPUT ;
    USE SIGNAL ;
    PORT
      LAYER M4 ;
        RECT  0 96.912 0.084 96.936 ;
    END
  END f_d[780]
  PIN f_d[781]
    DIRECTION INPUT ;
    USE SIGNAL ;
    PORT
      LAYER M4 ;
        RECT  0 97.104 0.084 97.128 ;
    END
  END f_d[781]
  PIN f_d[782]
    DIRECTION INPUT ;
    USE SIGNAL ;
    PORT
      LAYER M4 ;
        RECT  0 97.296 0.084 97.32 ;
    END
  END f_d[782]
  PIN f_d[783]
    DIRECTION INPUT ;
    USE SIGNAL ;
    PORT
      LAYER M4 ;
        RECT  0 97.488 0.084 97.512 ;
    END
  END f_d[783]
  PIN f_d[784]
    DIRECTION INPUT ;
    USE SIGNAL ;
    PORT
      LAYER M4 ;
        RECT  0 97.68 0.084 97.704 ;
    END
  END f_d[784]
  PIN f_d[785]
    DIRECTION INPUT ;
    USE SIGNAL ;
    PORT
      LAYER M4 ;
        RECT  0 97.872 0.084 97.896 ;
    END
  END f_d[785]
  PIN f_d[786]
    DIRECTION INPUT ;
    USE SIGNAL ;
    PORT
      LAYER M4 ;
        RECT  0 98.064 0.084 98.088 ;
    END
  END f_d[786]
  PIN f_d[787]
    DIRECTION INPUT ;
    USE SIGNAL ;
    PORT
      LAYER M4 ;
        RECT  0 98.256 0.084 98.28 ;
    END
  END f_d[787]
  PIN f_d[788]
    DIRECTION INPUT ;
    USE SIGNAL ;
    PORT
      LAYER M4 ;
        RECT  0 98.448 0.084 98.472 ;
    END
  END f_d[788]
  PIN f_d[789]
    DIRECTION INPUT ;
    USE SIGNAL ;
    PORT
      LAYER M4 ;
        RECT  0 98.64 0.084 98.664 ;
    END
  END f_d[789]
  PIN f_d[78]
    DIRECTION INPUT ;
    USE SIGNAL ;
    PORT
      LAYER M4 ;
        RECT  0 161.232 0.084 161.256 ;
    END
  END f_d[78]
  PIN f_d[790]
    DIRECTION INPUT ;
    USE SIGNAL ;
    PORT
      LAYER M4 ;
        RECT  0 98.832 0.084 98.856 ;
    END
  END f_d[790]
  PIN f_d[791]
    DIRECTION INPUT ;
    USE SIGNAL ;
    PORT
      LAYER M4 ;
        RECT  0 99.024 0.084 99.048 ;
    END
  END f_d[791]
  PIN f_d[792]
    DIRECTION INPUT ;
    USE SIGNAL ;
    PORT
      LAYER M4 ;
        RECT  0 99.216 0.084 99.24 ;
    END
  END f_d[792]
  PIN f_d[793]
    DIRECTION INPUT ;
    USE SIGNAL ;
    PORT
      LAYER M4 ;
        RECT  0 99.408 0.084 99.432 ;
    END
  END f_d[793]
  PIN f_d[794]
    DIRECTION INPUT ;
    USE SIGNAL ;
    PORT
      LAYER M4 ;
        RECT  0 99.6 0.084 99.624 ;
    END
  END f_d[794]
  PIN f_d[795]
    DIRECTION INPUT ;
    USE SIGNAL ;
    PORT
      LAYER M4 ;
        RECT  0 99.792 0.084 99.816 ;
    END
  END f_d[795]
  PIN f_d[796]
    DIRECTION INPUT ;
    USE SIGNAL ;
    PORT
      LAYER M4 ;
        RECT  0 99.984 0.084 100.008 ;
    END
  END f_d[796]
  PIN f_d[797]
    DIRECTION INPUT ;
    USE SIGNAL ;
    PORT
      LAYER M4 ;
        RECT  0 178.512 0.084 178.536 ;
    END
  END f_d[797]
  PIN f_d[798]
    DIRECTION INPUT ;
    USE SIGNAL ;
    PORT
      LAYER M4 ;
        RECT  0 178.704 0.084 178.728 ;
    END
  END f_d[798]
  PIN f_d[799]
    DIRECTION INPUT ;
    USE SIGNAL ;
    PORT
      LAYER M4 ;
        RECT  0 178.896 0.084 178.92 ;
    END
  END f_d[799]
  PIN f_d[79]
    DIRECTION INPUT ;
    USE SIGNAL ;
    PORT
      LAYER M4 ;
        RECT  0 161.424 0.084 161.448 ;
    END
  END f_d[79]
  PIN f_d[7]
    DIRECTION INPUT ;
    USE SIGNAL ;
    PORT
      LAYER M4 ;
        RECT  0 26.256 0.084 26.28 ;
    END
  END f_d[7]
  PIN f_d[800]
    DIRECTION INPUT ;
    USE SIGNAL ;
    PORT
      LAYER M4 ;
        RECT  0 179.088 0.084 179.112 ;
    END
  END f_d[800]
  PIN f_d[801]
    DIRECTION INPUT ;
    USE SIGNAL ;
    PORT
      LAYER M4 ;
        RECT  0 179.28 0.084 179.304 ;
    END
  END f_d[801]
  PIN f_d[802]
    DIRECTION INPUT ;
    USE SIGNAL ;
    PORT
      LAYER M4 ;
        RECT  0 179.472 0.084 179.496 ;
    END
  END f_d[802]
  PIN f_d[803]
    DIRECTION INPUT ;
    USE SIGNAL ;
    PORT
      LAYER M4 ;
        RECT  0 179.664 0.084 179.688 ;
    END
  END f_d[803]
  PIN f_d[804]
    DIRECTION INPUT ;
    USE SIGNAL ;
    PORT
      LAYER M4 ;
        RECT  0 179.856 0.084 179.88 ;
    END
  END f_d[804]
  PIN f_d[805]
    DIRECTION INPUT ;
    USE SIGNAL ;
    PORT
      LAYER M4 ;
        RECT  0 180.048 0.084 180.072 ;
    END
  END f_d[805]
  PIN f_d[806]
    DIRECTION INPUT ;
    USE SIGNAL ;
    PORT
      LAYER M4 ;
        RECT  0 180.24 0.084 180.264 ;
    END
  END f_d[806]
  PIN f_d[807]
    DIRECTION INPUT ;
    USE SIGNAL ;
    PORT
      LAYER M4 ;
        RECT  0 180.432 0.084 180.456 ;
    END
  END f_d[807]
  PIN f_d[808]
    DIRECTION INPUT ;
    USE SIGNAL ;
    PORT
      LAYER M4 ;
        RECT  0 180.624 0.084 180.648 ;
    END
  END f_d[808]
  PIN f_d[809]
    DIRECTION INPUT ;
    USE SIGNAL ;
    PORT
      LAYER M4 ;
        RECT  0 180.816 0.084 180.84 ;
    END
  END f_d[809]
  PIN f_d[80]
    DIRECTION INPUT ;
    USE SIGNAL ;
    PORT
      LAYER M4 ;
        RECT  0 161.616 0.084 161.64 ;
    END
  END f_d[80]
  PIN f_d[810]
    DIRECTION INPUT ;
    USE SIGNAL ;
    PORT
      LAYER M4 ;
        RECT  0 181.008 0.084 181.032 ;
    END
  END f_d[810]
  PIN f_d[811]
    DIRECTION INPUT ;
    USE SIGNAL ;
    PORT
      LAYER M4 ;
        RECT  0 181.2 0.084 181.224 ;
    END
  END f_d[811]
  PIN f_d[812]
    DIRECTION INPUT ;
    USE SIGNAL ;
    PORT
      LAYER M4 ;
        RECT  0 181.392 0.084 181.416 ;
    END
  END f_d[812]
  PIN f_d[813]
    DIRECTION INPUT ;
    USE SIGNAL ;
    PORT
      LAYER M4 ;
        RECT  0 181.584 0.084 181.608 ;
    END
  END f_d[813]
  PIN f_d[814]
    DIRECTION INPUT ;
    USE SIGNAL ;
    PORT
      LAYER M4 ;
        RECT  0 181.776 0.084 181.8 ;
    END
  END f_d[814]
  PIN f_d[815]
    DIRECTION INPUT ;
    USE SIGNAL ;
    PORT
      LAYER M4 ;
        RECT  0 181.968 0.084 181.992 ;
    END
  END f_d[815]
  PIN f_d[816]
    DIRECTION INPUT ;
    USE SIGNAL ;
    PORT
      LAYER M4 ;
        RECT  0 182.16 0.084 182.184 ;
    END
  END f_d[816]
  PIN f_d[817]
    DIRECTION INPUT ;
    USE SIGNAL ;
    PORT
      LAYER M4 ;
        RECT  0 182.352 0.084 182.376 ;
    END
  END f_d[817]
  PIN f_d[818]
    DIRECTION INPUT ;
    USE SIGNAL ;
    PORT
      LAYER M4 ;
        RECT  0 182.544 0.084 182.568 ;
    END
  END f_d[818]
  PIN f_d[819]
    DIRECTION INPUT ;
    USE SIGNAL ;
    PORT
      LAYER M4 ;
        RECT  0 182.736 0.084 182.76 ;
    END
  END f_d[819]
  PIN f_d[81]
    DIRECTION INPUT ;
    USE SIGNAL ;
    PORT
      LAYER M4 ;
        RECT  0 161.808 0.084 161.832 ;
    END
  END f_d[81]
  PIN f_d[820]
    DIRECTION INPUT ;
    USE SIGNAL ;
    PORT
      LAYER M4 ;
        RECT  0 182.928 0.084 182.952 ;
    END
  END f_d[820]
  PIN f_d[821]
    DIRECTION INPUT ;
    USE SIGNAL ;
    PORT
      LAYER M4 ;
        RECT  0 183.12 0.084 183.144 ;
    END
  END f_d[821]
  PIN f_d[822]
    DIRECTION INPUT ;
    USE SIGNAL ;
    PORT
      LAYER M4 ;
        RECT  0 183.312 0.084 183.336 ;
    END
  END f_d[822]
  PIN f_d[823]
    DIRECTION INPUT ;
    USE SIGNAL ;
    PORT
      LAYER M4 ;
        RECT  0 183.504 0.084 183.528 ;
    END
  END f_d[823]
  PIN f_d[824]
    DIRECTION INPUT ;
    USE SIGNAL ;
    PORT
      LAYER M4 ;
        RECT  0 183.696 0.084 183.72 ;
    END
  END f_d[824]
  PIN f_d[825]
    DIRECTION INPUT ;
    USE SIGNAL ;
    PORT
      LAYER M4 ;
        RECT  0 183.888 0.084 183.912 ;
    END
  END f_d[825]
  PIN f_d[826]
    DIRECTION INPUT ;
    USE SIGNAL ;
    PORT
      LAYER M4 ;
        RECT  0 184.08 0.084 184.104 ;
    END
  END f_d[826]
  PIN f_d[827]
    DIRECTION INPUT ;
    USE SIGNAL ;
    PORT
      LAYER M4 ;
        RECT  0 184.272 0.084 184.296 ;
    END
  END f_d[827]
  PIN f_d[828]
    DIRECTION INPUT ;
    USE SIGNAL ;
    PORT
      LAYER M4 ;
        RECT  0 184.464 0.084 184.488 ;
    END
  END f_d[828]
  PIN f_d[829]
    DIRECTION INPUT ;
    USE SIGNAL ;
    PORT
      LAYER M4 ;
        RECT  0 184.656 0.084 184.68 ;
    END
  END f_d[829]
  PIN f_d[82]
    DIRECTION INPUT ;
    USE SIGNAL ;
    PORT
      LAYER M4 ;
        RECT  0 162 0.084 162.024 ;
    END
  END f_d[82]
  PIN f_d[830]
    DIRECTION INPUT ;
    USE SIGNAL ;
    PORT
      LAYER M4 ;
        RECT  0 184.848 0.084 184.872 ;
    END
  END f_d[830]
  PIN f_d[831]
    DIRECTION INPUT ;
    USE SIGNAL ;
    PORT
      LAYER M4 ;
        RECT  0 185.04 0.084 185.064 ;
    END
  END f_d[831]
  PIN f_d[832]
    DIRECTION INPUT ;
    USE SIGNAL ;
    PORT
      LAYER M4 ;
        RECT  0 185.232 0.084 185.256 ;
    END
  END f_d[832]
  PIN f_d[833]
    DIRECTION INPUT ;
    USE SIGNAL ;
    PORT
      LAYER M4 ;
        RECT  0 185.424 0.084 185.448 ;
    END
  END f_d[833]
  PIN f_d[834]
    DIRECTION INPUT ;
    USE SIGNAL ;
    PORT
      LAYER M4 ;
        RECT  0 185.616 0.084 185.64 ;
    END
  END f_d[834]
  PIN f_d[835]
    DIRECTION INPUT ;
    USE SIGNAL ;
    PORT
      LAYER M4 ;
        RECT  0 185.808 0.084 185.832 ;
    END
  END f_d[835]
  PIN f_d[836]
    DIRECTION INPUT ;
    USE SIGNAL ;
    PORT
      LAYER M4 ;
        RECT  0 186 0.084 186.024 ;
    END
  END f_d[836]
  PIN f_d[837]
    DIRECTION INPUT ;
    USE SIGNAL ;
    PORT
      LAYER M4 ;
        RECT  0 186.192 0.084 186.216 ;
    END
  END f_d[837]
  PIN f_d[838]
    DIRECTION INPUT ;
    USE SIGNAL ;
    PORT
      LAYER M4 ;
        RECT  0 186.384 0.084 186.408 ;
    END
  END f_d[838]
  PIN f_d[839]
    DIRECTION INPUT ;
    USE SIGNAL ;
    PORT
      LAYER M4 ;
        RECT  0 186.576 0.084 186.6 ;
    END
  END f_d[839]
  PIN f_d[83]
    DIRECTION INPUT ;
    USE SIGNAL ;
    PORT
      LAYER M4 ;
        RECT  0 162.192 0.084 162.216 ;
    END
  END f_d[83]
  PIN f_d[840]
    DIRECTION INPUT ;
    USE SIGNAL ;
    PORT
      LAYER M4 ;
        RECT  0 186.768 0.084 186.792 ;
    END
  END f_d[840]
  PIN f_d[841]
    DIRECTION INPUT ;
    USE SIGNAL ;
    PORT
      LAYER M4 ;
        RECT  0 186.96 0.084 186.984 ;
    END
  END f_d[841]
  PIN f_d[842]
    DIRECTION INPUT ;
    USE SIGNAL ;
    PORT
      LAYER M4 ;
        RECT  0 187.152 0.084 187.176 ;
    END
  END f_d[842]
  PIN f_d[843]
    DIRECTION INPUT ;
    USE SIGNAL ;
    PORT
      LAYER M4 ;
        RECT  0 187.344 0.084 187.368 ;
    END
  END f_d[843]
  PIN f_d[844]
    DIRECTION INPUT ;
    USE SIGNAL ;
    PORT
      LAYER M4 ;
        RECT  0 187.536 0.084 187.56 ;
    END
  END f_d[844]
  PIN f_d[845]
    DIRECTION INPUT ;
    USE SIGNAL ;
    PORT
      LAYER M4 ;
        RECT  0 187.728 0.084 187.752 ;
    END
  END f_d[845]
  PIN f_d[846]
    DIRECTION INPUT ;
    USE SIGNAL ;
    PORT
      LAYER M4 ;
        RECT  0 187.92 0.084 187.944 ;
    END
  END f_d[846]
  PIN f_d[847]
    DIRECTION INPUT ;
    USE SIGNAL ;
    PORT
      LAYER M4 ;
        RECT  0 188.112 0.084 188.136 ;
    END
  END f_d[847]
  PIN f_d[848]
    DIRECTION INPUT ;
    USE SIGNAL ;
    PORT
      LAYER M4 ;
        RECT  0 188.304 0.084 188.328 ;
    END
  END f_d[848]
  PIN f_d[849]
    DIRECTION INPUT ;
    USE SIGNAL ;
    PORT
      LAYER M4 ;
        RECT  0 188.496 0.084 188.52 ;
    END
  END f_d[849]
  PIN f_d[84]
    DIRECTION INPUT ;
    USE SIGNAL ;
    PORT
      LAYER M4 ;
        RECT  0 162.384 0.084 162.408 ;
    END
  END f_d[84]
  PIN f_d[850]
    DIRECTION INPUT ;
    USE SIGNAL ;
    PORT
      LAYER M4 ;
        RECT  0 188.688 0.084 188.712 ;
    END
  END f_d[850]
  PIN f_d[851]
    DIRECTION INPUT ;
    USE SIGNAL ;
    PORT
      LAYER M4 ;
        RECT  0 188.88 0.084 188.904 ;
    END
  END f_d[851]
  PIN f_d[852]
    DIRECTION INPUT ;
    USE SIGNAL ;
    PORT
      LAYER M4 ;
        RECT  0 189.072 0.084 189.096 ;
    END
  END f_d[852]
  PIN f_d[853]
    DIRECTION INPUT ;
    USE SIGNAL ;
    PORT
      LAYER M4 ;
        RECT  0 189.264 0.084 189.288 ;
    END
  END f_d[853]
  PIN f_d[854]
    DIRECTION INPUT ;
    USE SIGNAL ;
    PORT
      LAYER M4 ;
        RECT  0 189.456 0.084 189.48 ;
    END
  END f_d[854]
  PIN f_d[855]
    DIRECTION INPUT ;
    USE SIGNAL ;
    PORT
      LAYER M4 ;
        RECT  0 189.648 0.084 189.672 ;
    END
  END f_d[855]
  PIN f_d[856]
    DIRECTION INPUT ;
    USE SIGNAL ;
    PORT
      LAYER M4 ;
        RECT  0 189.84 0.084 189.864 ;
    END
  END f_d[856]
  PIN f_d[857]
    DIRECTION INPUT ;
    USE SIGNAL ;
    PORT
      LAYER M4 ;
        RECT  0 190.032 0.084 190.056 ;
    END
  END f_d[857]
  PIN f_d[858]
    DIRECTION INPUT ;
    USE SIGNAL ;
    PORT
      LAYER M4 ;
        RECT  0 190.224 0.084 190.248 ;
    END
  END f_d[858]
  PIN f_d[859]
    DIRECTION INPUT ;
    USE SIGNAL ;
    PORT
      LAYER M4 ;
        RECT  0 190.416 0.084 190.44 ;
    END
  END f_d[859]
  PIN f_d[85]
    DIRECTION INPUT ;
    USE SIGNAL ;
    PORT
      LAYER M4 ;
        RECT  0 162.576 0.084 162.6 ;
    END
  END f_d[85]
  PIN f_d[860]
    DIRECTION INPUT ;
    USE SIGNAL ;
    PORT
      LAYER M4 ;
        RECT  0 190.608 0.084 190.632 ;
    END
  END f_d[860]
  PIN f_d[861]
    DIRECTION INPUT ;
    USE SIGNAL ;
    PORT
      LAYER M4 ;
        RECT  0 69.456 0.084 69.48 ;
    END
  END f_d[861]
  PIN f_d[862]
    DIRECTION INPUT ;
    USE SIGNAL ;
    PORT
      LAYER M4 ;
        RECT  0 69.648 0.084 69.672 ;
    END
  END f_d[862]
  PIN f_d[863]
    DIRECTION INPUT ;
    USE SIGNAL ;
    PORT
      LAYER M4 ;
        RECT  0 69.84 0.084 69.864 ;
    END
  END f_d[863]
  PIN f_d[864]
    DIRECTION INPUT ;
    USE SIGNAL ;
    PORT
      LAYER M4 ;
        RECT  0 70.032 0.084 70.056 ;
    END
  END f_d[864]
  PIN f_d[865]
    DIRECTION INPUT ;
    USE SIGNAL ;
    PORT
      LAYER M4 ;
        RECT  0 70.224 0.084 70.248 ;
    END
  END f_d[865]
  PIN f_d[866]
    DIRECTION INPUT ;
    USE SIGNAL ;
    PORT
      LAYER M4 ;
        RECT  0 70.416 0.084 70.44 ;
    END
  END f_d[866]
  PIN f_d[867]
    DIRECTION INPUT ;
    USE SIGNAL ;
    PORT
      LAYER M4 ;
        RECT  0 70.608 0.084 70.632 ;
    END
  END f_d[867]
  PIN f_d[868]
    DIRECTION INPUT ;
    USE SIGNAL ;
    PORT
      LAYER M4 ;
        RECT  0 70.8 0.084 70.824 ;
    END
  END f_d[868]
  PIN f_d[869]
    DIRECTION INPUT ;
    USE SIGNAL ;
    PORT
      LAYER M4 ;
        RECT  0 70.992 0.084 71.016 ;
    END
  END f_d[869]
  PIN f_d[86]
    DIRECTION INPUT ;
    USE SIGNAL ;
    PORT
      LAYER M4 ;
        RECT  0 162.768 0.084 162.792 ;
    END
  END f_d[86]
  PIN f_d[870]
    DIRECTION INPUT ;
    USE SIGNAL ;
    PORT
      LAYER M4 ;
        RECT  0 71.184 0.084 71.208 ;
    END
  END f_d[870]
  PIN f_d[871]
    DIRECTION INPUT ;
    USE SIGNAL ;
    PORT
      LAYER M4 ;
        RECT  0 71.376 0.084 71.4 ;
    END
  END f_d[871]
  PIN f_d[872]
    DIRECTION INPUT ;
    USE SIGNAL ;
    PORT
      LAYER M4 ;
        RECT  0 71.568 0.084 71.592 ;
    END
  END f_d[872]
  PIN f_d[873]
    DIRECTION INPUT ;
    USE SIGNAL ;
    PORT
      LAYER M4 ;
        RECT  0 71.76 0.084 71.784 ;
    END
  END f_d[873]
  PIN f_d[874]
    DIRECTION INPUT ;
    USE SIGNAL ;
    PORT
      LAYER M4 ;
        RECT  0 71.952 0.084 71.976 ;
    END
  END f_d[874]
  PIN f_d[875]
    DIRECTION INPUT ;
    USE SIGNAL ;
    PORT
      LAYER M4 ;
        RECT  0 72.144 0.084 72.168 ;
    END
  END f_d[875]
  PIN f_d[876]
    DIRECTION INPUT ;
    USE SIGNAL ;
    PORT
      LAYER M4 ;
        RECT  0 72.336 0.084 72.36 ;
    END
  END f_d[876]
  PIN f_d[877]
    DIRECTION INPUT ;
    USE SIGNAL ;
    PORT
      LAYER M4 ;
        RECT  0 72.528 0.084 72.552 ;
    END
  END f_d[877]
  PIN f_d[878]
    DIRECTION INPUT ;
    USE SIGNAL ;
    PORT
      LAYER M4 ;
        RECT  0 72.72 0.084 72.744 ;
    END
  END f_d[878]
  PIN f_d[879]
    DIRECTION INPUT ;
    USE SIGNAL ;
    PORT
      LAYER M4 ;
        RECT  0 72.912 0.084 72.936 ;
    END
  END f_d[879]
  PIN f_d[87]
    DIRECTION INPUT ;
    USE SIGNAL ;
    PORT
      LAYER M4 ;
        RECT  0 162.96 0.084 162.984 ;
    END
  END f_d[87]
  PIN f_d[880]
    DIRECTION INPUT ;
    USE SIGNAL ;
    PORT
      LAYER M4 ;
        RECT  0 73.104 0.084 73.128 ;
    END
  END f_d[880]
  PIN f_d[881]
    DIRECTION INPUT ;
    USE SIGNAL ;
    PORT
      LAYER M4 ;
        RECT  0 73.296 0.084 73.32 ;
    END
  END f_d[881]
  PIN f_d[882]
    DIRECTION INPUT ;
    USE SIGNAL ;
    PORT
      LAYER M4 ;
        RECT  0 73.488 0.084 73.512 ;
    END
  END f_d[882]
  PIN f_d[883]
    DIRECTION INPUT ;
    USE SIGNAL ;
    PORT
      LAYER M4 ;
        RECT  0 73.68 0.084 73.704 ;
    END
  END f_d[883]
  PIN f_d[884]
    DIRECTION INPUT ;
    USE SIGNAL ;
    PORT
      LAYER M4 ;
        RECT  0 73.872 0.084 73.896 ;
    END
  END f_d[884]
  PIN f_d[885]
    DIRECTION INPUT ;
    USE SIGNAL ;
    PORT
      LAYER M4 ;
        RECT  0 74.064 0.084 74.088 ;
    END
  END f_d[885]
  PIN f_d[886]
    DIRECTION INPUT ;
    USE SIGNAL ;
    PORT
      LAYER M4 ;
        RECT  0 74.256 0.084 74.28 ;
    END
  END f_d[886]
  PIN f_d[887]
    DIRECTION INPUT ;
    USE SIGNAL ;
    PORT
      LAYER M4 ;
        RECT  0 74.448 0.084 74.472 ;
    END
  END f_d[887]
  PIN f_d[888]
    DIRECTION INPUT ;
    USE SIGNAL ;
    PORT
      LAYER M4 ;
        RECT  0 74.64 0.084 74.664 ;
    END
  END f_d[888]
  PIN f_d[889]
    DIRECTION INPUT ;
    USE SIGNAL ;
    PORT
      LAYER M4 ;
        RECT  0 74.832 0.084 74.856 ;
    END
  END f_d[889]
  PIN f_d[88]
    DIRECTION INPUT ;
    USE SIGNAL ;
    PORT
      LAYER M4 ;
        RECT  0 163.152 0.084 163.176 ;
    END
  END f_d[88]
  PIN f_d[890]
    DIRECTION INPUT ;
    USE SIGNAL ;
    PORT
      LAYER M4 ;
        RECT  0 75.024 0.084 75.048 ;
    END
  END f_d[890]
  PIN f_d[891]
    DIRECTION INPUT ;
    USE SIGNAL ;
    PORT
      LAYER M4 ;
        RECT  0 75.216 0.084 75.24 ;
    END
  END f_d[891]
  PIN f_d[892]
    DIRECTION INPUT ;
    USE SIGNAL ;
    PORT
      LAYER M4 ;
        RECT  0 75.408 0.084 75.432 ;
    END
  END f_d[892]
  PIN f_d[893]
    DIRECTION INPUT ;
    USE SIGNAL ;
    PORT
      LAYER M4 ;
        RECT  0 63.312 0.084 63.336 ;
    END
  END f_d[893]
  PIN f_d[894]
    DIRECTION INPUT ;
    USE SIGNAL ;
    PORT
      LAYER M4 ;
        RECT  0 63.504 0.084 63.528 ;
    END
  END f_d[894]
  PIN f_d[895]
    DIRECTION INPUT ;
    USE SIGNAL ;
    PORT
      LAYER M4 ;
        RECT  0 63.696 0.084 63.72 ;
    END
  END f_d[895]
  PIN f_d[896]
    DIRECTION INPUT ;
    USE SIGNAL ;
    PORT
      LAYER M4 ;
        RECT  0 63.888 0.084 63.912 ;
    END
  END f_d[896]
  PIN f_d[897]
    DIRECTION INPUT ;
    USE SIGNAL ;
    PORT
      LAYER M4 ;
        RECT  0 64.08 0.084 64.104 ;
    END
  END f_d[897]
  PIN f_d[898]
    DIRECTION INPUT ;
    USE SIGNAL ;
    PORT
      LAYER M4 ;
        RECT  0 64.272 0.084 64.296 ;
    END
  END f_d[898]
  PIN f_d[899]
    DIRECTION INPUT ;
    USE SIGNAL ;
    PORT
      LAYER M4 ;
        RECT  0 64.464 0.084 64.488 ;
    END
  END f_d[899]
  PIN f_d[89]
    DIRECTION INPUT ;
    USE SIGNAL ;
    PORT
      LAYER M4 ;
        RECT  0 163.344 0.084 163.368 ;
    END
  END f_d[89]
  PIN f_d[8]
    DIRECTION INPUT ;
    USE SIGNAL ;
    PORT
      LAYER M4 ;
        RECT  0 26.448 0.084 26.472 ;
    END
  END f_d[8]
  PIN f_d[900]
    DIRECTION INPUT ;
    USE SIGNAL ;
    PORT
      LAYER M4 ;
        RECT  0 64.656 0.084 64.68 ;
    END
  END f_d[900]
  PIN f_d[901]
    DIRECTION INPUT ;
    USE SIGNAL ;
    PORT
      LAYER M4 ;
        RECT  0 64.848 0.084 64.872 ;
    END
  END f_d[901]
  PIN f_d[902]
    DIRECTION INPUT ;
    USE SIGNAL ;
    PORT
      LAYER M4 ;
        RECT  0 65.04 0.084 65.064 ;
    END
  END f_d[902]
  PIN f_d[903]
    DIRECTION INPUT ;
    USE SIGNAL ;
    PORT
      LAYER M4 ;
        RECT  0 65.232 0.084 65.256 ;
    END
  END f_d[903]
  PIN f_d[904]
    DIRECTION INPUT ;
    USE SIGNAL ;
    PORT
      LAYER M4 ;
        RECT  0 65.424 0.084 65.448 ;
    END
  END f_d[904]
  PIN f_d[905]
    DIRECTION INPUT ;
    USE SIGNAL ;
    PORT
      LAYER M4 ;
        RECT  0 65.616 0.084 65.64 ;
    END
  END f_d[905]
  PIN f_d[906]
    DIRECTION INPUT ;
    USE SIGNAL ;
    PORT
      LAYER M4 ;
        RECT  0 65.808 0.084 65.832 ;
    END
  END f_d[906]
  PIN f_d[907]
    DIRECTION INPUT ;
    USE SIGNAL ;
    PORT
      LAYER M4 ;
        RECT  0 66 0.084 66.024 ;
    END
  END f_d[907]
  PIN f_d[908]
    DIRECTION INPUT ;
    USE SIGNAL ;
    PORT
      LAYER M4 ;
        RECT  0 66.192 0.084 66.216 ;
    END
  END f_d[908]
  PIN f_d[909]
    DIRECTION INPUT ;
    USE SIGNAL ;
    PORT
      LAYER M4 ;
        RECT  0 66.384 0.084 66.408 ;
    END
  END f_d[909]
  PIN f_d[90]
    DIRECTION INPUT ;
    USE SIGNAL ;
    PORT
      LAYER M4 ;
        RECT  0 163.536 0.084 163.56 ;
    END
  END f_d[90]
  PIN f_d[910]
    DIRECTION INPUT ;
    USE SIGNAL ;
    PORT
      LAYER M4 ;
        RECT  0 66.576 0.084 66.6 ;
    END
  END f_d[910]
  PIN f_d[911]
    DIRECTION INPUT ;
    USE SIGNAL ;
    PORT
      LAYER M4 ;
        RECT  0 66.768 0.084 66.792 ;
    END
  END f_d[911]
  PIN f_d[912]
    DIRECTION INPUT ;
    USE SIGNAL ;
    PORT
      LAYER M4 ;
        RECT  0 66.96 0.084 66.984 ;
    END
  END f_d[912]
  PIN f_d[913]
    DIRECTION INPUT ;
    USE SIGNAL ;
    PORT
      LAYER M4 ;
        RECT  0 67.152 0.084 67.176 ;
    END
  END f_d[913]
  PIN f_d[914]
    DIRECTION INPUT ;
    USE SIGNAL ;
    PORT
      LAYER M4 ;
        RECT  0 67.344 0.084 67.368 ;
    END
  END f_d[914]
  PIN f_d[915]
    DIRECTION INPUT ;
    USE SIGNAL ;
    PORT
      LAYER M4 ;
        RECT  0 67.536 0.084 67.56 ;
    END
  END f_d[915]
  PIN f_d[916]
    DIRECTION INPUT ;
    USE SIGNAL ;
    PORT
      LAYER M4 ;
        RECT  0 67.728 0.084 67.752 ;
    END
  END f_d[916]
  PIN f_d[917]
    DIRECTION INPUT ;
    USE SIGNAL ;
    PORT
      LAYER M4 ;
        RECT  0 67.92 0.084 67.944 ;
    END
  END f_d[917]
  PIN f_d[918]
    DIRECTION INPUT ;
    USE SIGNAL ;
    PORT
      LAYER M4 ;
        RECT  0 68.112 0.084 68.136 ;
    END
  END f_d[918]
  PIN f_d[919]
    DIRECTION INPUT ;
    USE SIGNAL ;
    PORT
      LAYER M4 ;
        RECT  0 68.304 0.084 68.328 ;
    END
  END f_d[919]
  PIN f_d[91]
    DIRECTION INPUT ;
    USE SIGNAL ;
    PORT
      LAYER M4 ;
        RECT  0 163.728 0.084 163.752 ;
    END
  END f_d[91]
  PIN f_d[920]
    DIRECTION INPUT ;
    USE SIGNAL ;
    PORT
      LAYER M4 ;
        RECT  0 68.496 0.084 68.52 ;
    END
  END f_d[920]
  PIN f_d[921]
    DIRECTION INPUT ;
    USE SIGNAL ;
    PORT
      LAYER M4 ;
        RECT  0 68.688 0.084 68.712 ;
    END
  END f_d[921]
  PIN f_d[922]
    DIRECTION INPUT ;
    USE SIGNAL ;
    PORT
      LAYER M4 ;
        RECT  0 68.88 0.084 68.904 ;
    END
  END f_d[922]
  PIN f_d[923]
    DIRECTION INPUT ;
    USE SIGNAL ;
    PORT
      LAYER M4 ;
        RECT  0 69.072 0.084 69.096 ;
    END
  END f_d[923]
  PIN f_d[924]
    DIRECTION INPUT ;
    USE SIGNAL ;
    PORT
      LAYER M4 ;
        RECT  0 69.264 0.084 69.288 ;
    END
  END f_d[924]
  PIN f_d[925]
    DIRECTION INPUT ;
    USE SIGNAL ;
    PORT
      LAYER M4 ;
        RECT  0 190.8 0.084 190.824 ;
    END
  END f_d[925]
  PIN f_d[926]
    DIRECTION INPUT ;
    USE SIGNAL ;
    PORT
      LAYER M4 ;
        RECT  0 190.992 0.084 191.016 ;
    END
  END f_d[926]
  PIN f_d[927]
    DIRECTION INPUT ;
    USE SIGNAL ;
    PORT
      LAYER M4 ;
        RECT  0 191.184 0.084 191.208 ;
    END
  END f_d[927]
  PIN f_d[928]
    DIRECTION INPUT ;
    USE SIGNAL ;
    PORT
      LAYER M4 ;
        RECT  0 191.376 0.084 191.4 ;
    END
  END f_d[928]
  PIN f_d[929]
    DIRECTION INPUT ;
    USE SIGNAL ;
    PORT
      LAYER M4 ;
        RECT  0 191.568 0.084 191.592 ;
    END
  END f_d[929]
  PIN f_d[92]
    DIRECTION INPUT ;
    USE SIGNAL ;
    PORT
      LAYER M4 ;
        RECT  0 163.92 0.084 163.944 ;
    END
  END f_d[92]
  PIN f_d[930]
    DIRECTION INPUT ;
    USE SIGNAL ;
    PORT
      LAYER M4 ;
        RECT  0 191.76 0.084 191.784 ;
    END
  END f_d[930]
  PIN f_d[931]
    DIRECTION INPUT ;
    USE SIGNAL ;
    PORT
      LAYER M4 ;
        RECT  0 191.952 0.084 191.976 ;
    END
  END f_d[931]
  PIN f_d[932]
    DIRECTION INPUT ;
    USE SIGNAL ;
    PORT
      LAYER M4 ;
        RECT  0 192.144 0.084 192.168 ;
    END
  END f_d[932]
  PIN f_d[933]
    DIRECTION INPUT ;
    USE SIGNAL ;
    PORT
      LAYER M4 ;
        RECT  0 192.336 0.084 192.36 ;
    END
  END f_d[933]
  PIN f_d[934]
    DIRECTION INPUT ;
    USE SIGNAL ;
    PORT
      LAYER M4 ;
        RECT  0 192.528 0.084 192.552 ;
    END
  END f_d[934]
  PIN f_d[935]
    DIRECTION INPUT ;
    USE SIGNAL ;
    PORT
      LAYER M4 ;
        RECT  0 192.72 0.084 192.744 ;
    END
  END f_d[935]
  PIN f_d[936]
    DIRECTION INPUT ;
    USE SIGNAL ;
    PORT
      LAYER M4 ;
        RECT  0 192.912 0.084 192.936 ;
    END
  END f_d[936]
  PIN f_d[937]
    DIRECTION INPUT ;
    USE SIGNAL ;
    PORT
      LAYER M4 ;
        RECT  0 193.104 0.084 193.128 ;
    END
  END f_d[937]
  PIN f_d[938]
    DIRECTION INPUT ;
    USE SIGNAL ;
    PORT
      LAYER M4 ;
        RECT  0 193.296 0.084 193.32 ;
    END
  END f_d[938]
  PIN f_d[939]
    DIRECTION INPUT ;
    USE SIGNAL ;
    PORT
      LAYER M4 ;
        RECT  0 193.488 0.084 193.512 ;
    END
  END f_d[939]
  PIN f_d[93]
    DIRECTION INPUT ;
    USE SIGNAL ;
    PORT
      LAYER M4 ;
        RECT  0 164.112 0.084 164.136 ;
    END
  END f_d[93]
  PIN f_d[940]
    DIRECTION INPUT ;
    USE SIGNAL ;
    PORT
      LAYER M4 ;
        RECT  0 193.872 0.084 193.896 ;
    END
  END f_d[940]
  PIN f_d[941]
    DIRECTION INPUT ;
    USE SIGNAL ;
    PORT
      LAYER M4 ;
        RECT  0 194.064 0.084 194.088 ;
    END
  END f_d[941]
  PIN f_d[942]
    DIRECTION INPUT ;
    USE SIGNAL ;
    PORT
      LAYER M4 ;
        RECT  0 194.256 0.084 194.28 ;
    END
  END f_d[942]
  PIN f_d[943]
    DIRECTION INPUT ;
    USE SIGNAL ;
    PORT
      LAYER M4 ;
        RECT  0 194.448 0.084 194.472 ;
    END
  END f_d[943]
  PIN f_d[944]
    DIRECTION INPUT ;
    USE SIGNAL ;
    PORT
      LAYER M4 ;
        RECT  0 194.64 0.084 194.664 ;
    END
  END f_d[944]
  PIN f_d[945]
    DIRECTION INPUT ;
    USE SIGNAL ;
    PORT
      LAYER M4 ;
        RECT  0 194.832 0.084 194.856 ;
    END
  END f_d[945]
  PIN f_d[946]
    DIRECTION INPUT ;
    USE SIGNAL ;
    PORT
      LAYER M4 ;
        RECT  0 195.024 0.084 195.048 ;
    END
  END f_d[946]
  PIN f_d[947]
    DIRECTION INPUT ;
    USE SIGNAL ;
    PORT
      LAYER M4 ;
        RECT  0 195.216 0.084 195.24 ;
    END
  END f_d[947]
  PIN f_d[948]
    DIRECTION INPUT ;
    USE SIGNAL ;
    PORT
      LAYER M4 ;
        RECT  0 195.408 0.084 195.432 ;
    END
  END f_d[948]
  PIN f_d[949]
    DIRECTION INPUT ;
    USE SIGNAL ;
    PORT
      LAYER M4 ;
        RECT  0 195.6 0.084 195.624 ;
    END
  END f_d[949]
  PIN f_d[94]
    DIRECTION INPUT ;
    USE SIGNAL ;
    PORT
      LAYER M4 ;
        RECT  0 164.304 0.084 164.328 ;
    END
  END f_d[94]
  PIN f_d[950]
    DIRECTION INPUT ;
    USE SIGNAL ;
    PORT
      LAYER M4 ;
        RECT  0 195.792 0.084 195.816 ;
    END
  END f_d[950]
  PIN f_d[951]
    DIRECTION INPUT ;
    USE SIGNAL ;
    PORT
      LAYER M4 ;
        RECT  0 195.984 0.084 196.008 ;
    END
  END f_d[951]
  PIN f_d[952]
    DIRECTION INPUT ;
    USE SIGNAL ;
    PORT
      LAYER M4 ;
        RECT  0 196.176 0.084 196.2 ;
    END
  END f_d[952]
  PIN f_d[953]
    DIRECTION INPUT ;
    USE SIGNAL ;
    PORT
      LAYER M4 ;
        RECT  0 196.368 0.084 196.392 ;
    END
  END f_d[953]
  PIN f_d[954]
    DIRECTION INPUT ;
    USE SIGNAL ;
    PORT
      LAYER M4 ;
        RECT  0 196.56 0.084 196.584 ;
    END
  END f_d[954]
  PIN f_d[955]
    DIRECTION INPUT ;
    USE SIGNAL ;
    PORT
      LAYER M4 ;
        RECT  0 196.752 0.084 196.776 ;
    END
  END f_d[955]
  PIN f_d[956]
    DIRECTION INPUT ;
    USE SIGNAL ;
    PORT
      LAYER M4 ;
        RECT  0 196.944 0.084 196.968 ;
    END
  END f_d[956]
  PIN f_d[957]
    DIRECTION INPUT ;
    USE SIGNAL ;
    PORT
      LAYER M4 ;
        RECT  0 197.136 0.084 197.16 ;
    END
  END f_d[957]
  PIN f_d[958]
    DIRECTION INPUT ;
    USE SIGNAL ;
    PORT
      LAYER M4 ;
        RECT  0 197.328 0.084 197.352 ;
    END
  END f_d[958]
  PIN f_d[959]
    DIRECTION INPUT ;
    USE SIGNAL ;
    PORT
      LAYER M4 ;
        RECT  0 197.52 0.084 197.544 ;
    END
  END f_d[959]
  PIN f_d[95]
    DIRECTION INPUT ;
    USE SIGNAL ;
    PORT
      LAYER M4 ;
        RECT  0 164.496 0.084 164.52 ;
    END
  END f_d[95]
  PIN f_d[960]
    DIRECTION INPUT ;
    USE SIGNAL ;
    PORT
      LAYER M4 ;
        RECT  0 197.712 0.084 197.736 ;
    END
  END f_d[960]
  PIN f_d[961]
    DIRECTION INPUT ;
    USE SIGNAL ;
    PORT
      LAYER M4 ;
        RECT  0 197.904 0.084 197.928 ;
    END
  END f_d[961]
  PIN f_d[962]
    DIRECTION INPUT ;
    USE SIGNAL ;
    PORT
      LAYER M4 ;
        RECT  0 198.096 0.084 198.12 ;
    END
  END f_d[962]
  PIN f_d[963]
    DIRECTION INPUT ;
    USE SIGNAL ;
    PORT
      LAYER M4 ;
        RECT  0 198.288 0.084 198.312 ;
    END
  END f_d[963]
  PIN f_d[964]
    DIRECTION INPUT ;
    USE SIGNAL ;
    PORT
      LAYER M4 ;
        RECT  0 198.48 0.084 198.504 ;
    END
  END f_d[964]
  PIN f_d[965]
    DIRECTION INPUT ;
    USE SIGNAL ;
    PORT
      LAYER M4 ;
        RECT  0 198.672 0.084 198.696 ;
    END
  END f_d[965]
  PIN f_d[966]
    DIRECTION INPUT ;
    USE SIGNAL ;
    PORT
      LAYER M4 ;
        RECT  0 198.864 0.084 198.888 ;
    END
  END f_d[966]
  PIN f_d[967]
    DIRECTION INPUT ;
    USE SIGNAL ;
    PORT
      LAYER M4 ;
        RECT  0 199.056 0.084 199.08 ;
    END
  END f_d[967]
  PIN f_d[968]
    DIRECTION INPUT ;
    USE SIGNAL ;
    PORT
      LAYER M4 ;
        RECT  0 199.248 0.084 199.272 ;
    END
  END f_d[968]
  PIN f_d[969]
    DIRECTION INPUT ;
    USE SIGNAL ;
    PORT
      LAYER M4 ;
        RECT  0 199.44 0.084 199.464 ;
    END
  END f_d[969]
  PIN f_d[96]
    DIRECTION INPUT ;
    USE SIGNAL ;
    PORT
      LAYER M4 ;
        RECT  0 146.256 0.084 146.28 ;
    END
  END f_d[96]
  PIN f_d[970]
    DIRECTION INPUT ;
    USE SIGNAL ;
    PORT
      LAYER M4 ;
        RECT  0 199.632 0.084 199.656 ;
    END
  END f_d[970]
  PIN f_d[971]
    DIRECTION INPUT ;
    USE SIGNAL ;
    PORT
      LAYER M4 ;
        RECT  0 199.824 0.084 199.848 ;
    END
  END f_d[971]
  PIN f_d[972]
    DIRECTION INPUT ;
    USE SIGNAL ;
    PORT
      LAYER M4 ;
        RECT  0 200.016 0.084 200.04 ;
    END
  END f_d[972]
  PIN f_d[973]
    DIRECTION INPUT ;
    USE SIGNAL ;
    PORT
      LAYER M4 ;
        RECT  0 200.208 0.084 200.232 ;
    END
  END f_d[973]
  PIN f_d[974]
    DIRECTION INPUT ;
    USE SIGNAL ;
    PORT
      LAYER M4 ;
        RECT  0 200.4 0.084 200.424 ;
    END
  END f_d[974]
  PIN f_d[975]
    DIRECTION INPUT ;
    USE SIGNAL ;
    PORT
      LAYER M4 ;
        RECT  0 200.592 0.084 200.616 ;
    END
  END f_d[975]
  PIN f_d[976]
    DIRECTION INPUT ;
    USE SIGNAL ;
    PORT
      LAYER M4 ;
        RECT  0 200.784 0.084 200.808 ;
    END
  END f_d[976]
  PIN f_d[977]
    DIRECTION INPUT ;
    USE SIGNAL ;
    PORT
      LAYER M4 ;
        RECT  0 200.976 0.084 201 ;
    END
  END f_d[977]
  PIN f_d[978]
    DIRECTION INPUT ;
    USE SIGNAL ;
    PORT
      LAYER M4 ;
        RECT  0 201.168 0.084 201.192 ;
    END
  END f_d[978]
  PIN f_d[979]
    DIRECTION INPUT ;
    USE SIGNAL ;
    PORT
      LAYER M4 ;
        RECT  0 201.36 0.084 201.384 ;
    END
  END f_d[979]
  PIN f_d[97]
    DIRECTION INPUT ;
    USE SIGNAL ;
    PORT
      LAYER M4 ;
        RECT  0 146.448 0.084 146.472 ;
    END
  END f_d[97]
  PIN f_d[98]
    DIRECTION INPUT ;
    USE SIGNAL ;
    PORT
      LAYER M4 ;
        RECT  0 146.64 0.084 146.664 ;
    END
  END f_d[98]
  PIN f_d[99]
    DIRECTION INPUT ;
    USE SIGNAL ;
    PORT
      LAYER M4 ;
        RECT  0 146.832 0.084 146.856 ;
    END
  END f_d[99]
  PIN f_d[9]
    DIRECTION INPUT ;
    USE SIGNAL ;
    PORT
      LAYER M4 ;
        RECT  0 26.64 0.084 26.664 ;
    END
  END f_d[9]
  PIN f_f[0]
    DIRECTION INPUT ;
    USE SIGNAL ;
    PORT
      LAYER M4 ;
        RECT  0 201.552 0.084 201.576 ;
    END
  END f_f[0]
  PIN f_flt[0]
    DIRECTION INPUT ;
    USE SIGNAL ;
    PORT
      LAYER M4 ;
        RECT  0 202.32 0.084 202.344 ;
    END
  END f_flt[0]
  PIN f_flt[1]
    DIRECTION INPUT ;
    USE SIGNAL ;
    PORT
      LAYER M4 ;
        RECT  0 202.512 0.084 202.536 ;
    END
  END f_flt[1]
  PIN f_flt[2]
    DIRECTION INPUT ;
    USE SIGNAL ;
    PORT
      LAYER M4 ;
        RECT  0 202.704 0.084 202.728 ;
    END
  END f_flt[2]
  PIN f_flt[3]
    DIRECTION INPUT ;
    USE SIGNAL ;
    PORT
      LAYER M4 ;
        RECT  0 202.896 0.084 202.92 ;
    END
  END f_flt[3]
  PIN f_g[0]
    DIRECTION INPUT ;
    USE SIGNAL ;
    PORT
      LAYER M4 ;
        RECT  0 209.232 0.084 209.256 ;
    END
  END f_g[0]
  PIN f_l[0]
    DIRECTION INPUT ;
    USE SIGNAL ;
    PORT
      LAYER M4 ;
        RECT  0 210 0.084 210.024 ;
    END
  END f_l[0]
  PIN f_v[0]
    DIRECTION INPUT ;
    USE SIGNAL ;
    PORT
      LAYER M4 ;
        RECT  0 210.768 0.084 210.792 ;
    END
  END f_v[0]
  PIN fault
    DIRECTION OUTPUT ;
    USE SIGNAL ;
    PORT
      LAYER M5 ;
        RECT  61.2 215.916 61.224 216 ;
    END
  END fault
  PIN g_a[0]
    DIRECTION OUTPUT ;
    USE SIGNAL ;
    PORT
      LAYER M4 ;
        RECT  0 211.536 0.084 211.56 ;
    END
  END g_a[0]
  PIN g_a[10]
    DIRECTION OUTPUT ;
    USE SIGNAL ;
    PORT
      LAYER M4 ;
        RECT  0 213.456 0.084 213.48 ;
    END
  END g_a[10]
  PIN g_a[11]
    DIRECTION OUTPUT ;
    USE SIGNAL ;
    PORT
      LAYER M4 ;
        RECT  0 213.648 0.084 213.672 ;
    END
  END g_a[11]
  PIN g_a[12]
    DIRECTION OUTPUT ;
    USE SIGNAL ;
    PORT
      LAYER M4 ;
        RECT  0 213.84 0.084 213.864 ;
    END
  END g_a[12]
  PIN g_a[13]
    DIRECTION OUTPUT ;
    USE SIGNAL ;
    PORT
      LAYER M4 ;
        RECT  0 214.032 0.084 214.056 ;
    END
  END g_a[13]
  PIN g_a[14]
    DIRECTION OUTPUT ;
    USE SIGNAL ;
    PORT
      LAYER M4 ;
        RECT  0 214.224 0.084 214.248 ;
    END
  END g_a[14]
  PIN g_a[15]
    DIRECTION OUTPUT ;
    USE SIGNAL ;
    PORT
      LAYER M4 ;
        RECT  0 214.416 0.084 214.44 ;
    END
  END g_a[15]
  PIN g_a[16]
    DIRECTION OUTPUT ;
    USE SIGNAL ;
    PORT
      LAYER M4 ;
        RECT  0 214.608 0.084 214.632 ;
    END
  END g_a[16]
  PIN g_a[17]
    DIRECTION OUTPUT ;
    USE SIGNAL ;
    PORT
      LAYER M4 ;
        RECT  0 214.8 0.084 214.824 ;
    END
  END g_a[17]
  PIN g_a[18]
    DIRECTION OUTPUT ;
    USE SIGNAL ;
    PORT
      LAYER M4 ;
        RECT  0 214.992 0.084 215.016 ;
    END
  END g_a[18]
  PIN g_a[19]
    DIRECTION OUTPUT ;
    USE SIGNAL ;
    PORT
      LAYER M4 ;
        RECT  0 215.184 0.084 215.208 ;
    END
  END g_a[19]
  PIN g_a[1]
    DIRECTION OUTPUT ;
    USE SIGNAL ;
    PORT
      LAYER M4 ;
        RECT  0 211.728 0.084 211.752 ;
    END
  END g_a[1]
  PIN g_a[20]
    DIRECTION OUTPUT ;
    USE SIGNAL ;
    PORT
      LAYER M4 ;
        RECT  0 203.088 0.084 203.112 ;
    END
  END g_a[20]
  PIN g_a[21]
    DIRECTION OUTPUT ;
    USE SIGNAL ;
    PORT
      LAYER M4 ;
        RECT  0 203.28 0.084 203.304 ;
    END
  END g_a[21]
  PIN g_a[22]
    DIRECTION OUTPUT ;
    USE SIGNAL ;
    PORT
      LAYER M4 ;
        RECT  0 203.472 0.084 203.496 ;
    END
  END g_a[22]
  PIN g_a[23]
    DIRECTION OUTPUT ;
    USE SIGNAL ;
    PORT
      LAYER M4 ;
        RECT  0 203.664 0.084 203.688 ;
    END
  END g_a[23]
  PIN g_a[24]
    DIRECTION OUTPUT ;
    USE SIGNAL ;
    PORT
      LAYER M4 ;
        RECT  0 203.856 0.084 203.88 ;
    END
  END g_a[24]
  PIN g_a[25]
    DIRECTION OUTPUT ;
    USE SIGNAL ;
    PORT
      LAYER M4 ;
        RECT  0 204.048 0.084 204.072 ;
    END
  END g_a[25]
  PIN g_a[26]
    DIRECTION OUTPUT ;
    USE SIGNAL ;
    PORT
      LAYER M4 ;
        RECT  0 204.24 0.084 204.264 ;
    END
  END g_a[26]
  PIN g_a[27]
    DIRECTION OUTPUT ;
    USE SIGNAL ;
    PORT
      LAYER M4 ;
        RECT  0 204.432 0.084 204.456 ;
    END
  END g_a[27]
  PIN g_a[28]
    DIRECTION OUTPUT ;
    USE SIGNAL ;
    PORT
      LAYER M4 ;
        RECT  0 204.624 0.084 204.648 ;
    END
  END g_a[28]
  PIN g_a[29]
    DIRECTION OUTPUT ;
    USE SIGNAL ;
    PORT
      LAYER M4 ;
        RECT  0 204.816 0.084 204.84 ;
    END
  END g_a[29]
  PIN g_a[2]
    DIRECTION OUTPUT ;
    USE SIGNAL ;
    PORT
      LAYER M4 ;
        RECT  0 211.92 0.084 211.944 ;
    END
  END g_a[2]
  PIN g_a[30]
    DIRECTION OUTPUT ;
    USE SIGNAL ;
    PORT
      LAYER M4 ;
        RECT  0 205.008 0.084 205.032 ;
    END
  END g_a[30]
  PIN g_a[31]
    DIRECTION OUTPUT ;
    USE SIGNAL ;
    PORT
      LAYER M4 ;
        RECT  0 205.2 0.084 205.224 ;
    END
  END g_a[31]
  PIN g_a[32]
    DIRECTION OUTPUT ;
    USE SIGNAL ;
    PORT
      LAYER M4 ;
        RECT  0 205.392 0.084 205.416 ;
    END
  END g_a[32]
  PIN g_a[33]
    DIRECTION OUTPUT ;
    USE SIGNAL ;
    PORT
      LAYER M4 ;
        RECT  0 205.584 0.084 205.608 ;
    END
  END g_a[33]
  PIN g_a[34]
    DIRECTION OUTPUT ;
    USE SIGNAL ;
    PORT
      LAYER M4 ;
        RECT  0 205.776 0.084 205.8 ;
    END
  END g_a[34]
  PIN g_a[35]
    DIRECTION OUTPUT ;
    USE SIGNAL ;
    PORT
      LAYER M4 ;
        RECT  0 205.968 0.084 205.992 ;
    END
  END g_a[35]
  PIN g_a[36]
    DIRECTION OUTPUT ;
    USE SIGNAL ;
    PORT
      LAYER M4 ;
        RECT  0 206.16 0.084 206.184 ;
    END
  END g_a[36]
  PIN g_a[37]
    DIRECTION OUTPUT ;
    USE SIGNAL ;
    PORT
      LAYER M4 ;
        RECT  0 206.352 0.084 206.376 ;
    END
  END g_a[37]
  PIN g_a[38]
    DIRECTION OUTPUT ;
    USE SIGNAL ;
    PORT
      LAYER M4 ;
        RECT  0 206.544 0.084 206.568 ;
    END
  END g_a[38]
  PIN g_a[39]
    DIRECTION OUTPUT ;
    USE SIGNAL ;
    PORT
      LAYER M4 ;
        RECT  0 206.736 0.084 206.76 ;
    END
  END g_a[39]
  PIN g_a[3]
    DIRECTION OUTPUT ;
    USE SIGNAL ;
    PORT
      LAYER M4 ;
        RECT  0 212.112 0.084 212.136 ;
    END
  END g_a[3]
  PIN g_a[40]
    DIRECTION OUTPUT ;
    USE SIGNAL ;
    PORT
      LAYER M4 ;
        RECT  0 206.928 0.084 206.952 ;
    END
  END g_a[40]
  PIN g_a[41]
    DIRECTION OUTPUT ;
    USE SIGNAL ;
    PORT
      LAYER M4 ;
        RECT  0 207.12 0.084 207.144 ;
    END
  END g_a[41]
  PIN g_a[4]
    DIRECTION OUTPUT ;
    USE SIGNAL ;
    PORT
      LAYER M4 ;
        RECT  0 212.304 0.084 212.328 ;
    END
  END g_a[4]
  PIN g_a[5]
    DIRECTION OUTPUT ;
    USE SIGNAL ;
    PORT
      LAYER M4 ;
        RECT  0 212.496 0.084 212.52 ;
    END
  END g_a[5]
  PIN g_a[6]
    DIRECTION OUTPUT ;
    USE SIGNAL ;
    PORT
      LAYER M4 ;
        RECT  0 212.688 0.084 212.712 ;
    END
  END g_a[6]
  PIN g_a[7]
    DIRECTION OUTPUT ;
    USE SIGNAL ;
    PORT
      LAYER M4 ;
        RECT  0 212.88 0.084 212.904 ;
    END
  END g_a[7]
  PIN g_a[8]
    DIRECTION OUTPUT ;
    USE SIGNAL ;
    PORT
      LAYER M4 ;
        RECT  0 213.072 0.084 213.096 ;
    END
  END g_a[8]
  PIN g_a[9]
    DIRECTION OUTPUT ;
    USE SIGNAL ;
    PORT
      LAYER M4 ;
        RECT  0 213.264 0.084 213.288 ;
    END
  END g_a[9]
  PIN g_go
    DIRECTION OUTPUT ;
    USE SIGNAL ;
    PORT
      LAYER M4 ;
        RECT  0 207.312 0.084 207.336 ;
    END
  END g_go
  PIN g_hit[0]
    DIRECTION OUTPUT ;
    USE SIGNAL ;
    PORT
      LAYER M4 ;
        RECT  0 207.504 0.084 207.528 ;
    END
  END g_hit[0]
  PIN g_hit[10]
    DIRECTION OUTPUT ;
    USE SIGNAL ;
    PORT
      LAYER M4 ;
        RECT  0 2.256 0.084 2.28 ;
    END
  END g_hit[10]
  PIN g_hit[11]
    DIRECTION OUTPUT ;
    USE SIGNAL ;
    PORT
      LAYER M4 ;
        RECT  0 2.448 0.084 2.472 ;
    END
  END g_hit[11]
  PIN g_hit[12]
    DIRECTION OUTPUT ;
    USE SIGNAL ;
    PORT
      LAYER M4 ;
        RECT  0 2.64 0.084 2.664 ;
    END
  END g_hit[12]
  PIN g_hit[13]
    DIRECTION OUTPUT ;
    USE SIGNAL ;
    PORT
      LAYER M4 ;
        RECT  0 2.832 0.084 2.856 ;
    END
  END g_hit[13]
  PIN g_hit[14]
    DIRECTION OUTPUT ;
    USE SIGNAL ;
    PORT
      LAYER M4 ;
        RECT  0 3.024 0.084 3.048 ;
    END
  END g_hit[14]
  PIN g_hit[15]
    DIRECTION OUTPUT ;
    USE SIGNAL ;
    PORT
      LAYER M4 ;
        RECT  0 3.216 0.084 3.24 ;
    END
  END g_hit[15]
  PIN g_hit[16]
    DIRECTION OUTPUT ;
    USE SIGNAL ;
    PORT
      LAYER M4 ;
        RECT  0 3.408 0.084 3.432 ;
    END
  END g_hit[16]
  PIN g_hit[17]
    DIRECTION OUTPUT ;
    USE SIGNAL ;
    PORT
      LAYER M4 ;
        RECT  0 3.6 0.084 3.624 ;
    END
  END g_hit[17]
  PIN g_hit[18]
    DIRECTION OUTPUT ;
    USE SIGNAL ;
    PORT
      LAYER M4 ;
        RECT  0 3.792 0.084 3.816 ;
    END
  END g_hit[18]
  PIN g_hit[19]
    DIRECTION OUTPUT ;
    USE SIGNAL ;
    PORT
      LAYER M4 ;
        RECT  0 3.984 0.084 4.008 ;
    END
  END g_hit[19]
  PIN g_hit[1]
    DIRECTION OUTPUT ;
    USE SIGNAL ;
    PORT
      LAYER M4 ;
        RECT  0 207.696 0.084 207.72 ;
    END
  END g_hit[1]
  PIN g_hit[20]
    DIRECTION OUTPUT ;
    USE SIGNAL ;
    PORT
      LAYER M4 ;
        RECT  0 4.176 0.084 4.2 ;
    END
  END g_hit[20]
  PIN g_hit[21]
    DIRECTION OUTPUT ;
    USE SIGNAL ;
    PORT
      LAYER M4 ;
        RECT  0 4.368 0.084 4.392 ;
    END
  END g_hit[21]
  PIN g_hit[22]
    DIRECTION OUTPUT ;
    USE SIGNAL ;
    PORT
      LAYER M4 ;
        RECT  0 4.56 0.084 4.584 ;
    END
  END g_hit[22]
  PIN g_hit[23]
    DIRECTION OUTPUT ;
    USE SIGNAL ;
    PORT
      LAYER M4 ;
        RECT  0 4.752 0.084 4.776 ;
    END
  END g_hit[23]
  PIN g_hit[2]
    DIRECTION OUTPUT ;
    USE SIGNAL ;
    PORT
      LAYER M4 ;
        RECT  0 207.888 0.084 207.912 ;
    END
  END g_hit[2]
  PIN g_hit[3]
    DIRECTION OUTPUT ;
    USE SIGNAL ;
    PORT
      LAYER M4 ;
        RECT  0 208.08 0.084 208.104 ;
    END
  END g_hit[3]
  PIN g_hit[4]
    DIRECTION OUTPUT ;
    USE SIGNAL ;
    PORT
      LAYER M4 ;
        RECT  0 208.272 0.084 208.296 ;
    END
  END g_hit[4]
  PIN g_hit[5]
    DIRECTION OUTPUT ;
    USE SIGNAL ;
    PORT
      LAYER M4 ;
        RECT  0 208.464 0.084 208.488 ;
    END
  END g_hit[5]
  PIN g_hit[6]
    DIRECTION OUTPUT ;
    USE SIGNAL ;
    PORT
      LAYER M4 ;
        RECT  0 208.656 0.084 208.68 ;
    END
  END g_hit[6]
  PIN g_hit[7]
    DIRECTION OUTPUT ;
    USE SIGNAL ;
    PORT
      LAYER M4 ;
        RECT  0 208.848 0.084 208.872 ;
    END
  END g_hit[7]
  PIN g_hit[8]
    DIRECTION OUTPUT ;
    USE SIGNAL ;
    PORT
      LAYER M4 ;
        RECT  0 209.04 0.084 209.064 ;
    END
  END g_hit[8]
  PIN g_hit[9]
    DIRECTION OUTPUT ;
    USE SIGNAL ;
    PORT
      LAYER M4 ;
        RECT  0 2.064 0.084 2.088 ;
    END
  END g_hit[9]
  PIN i_ids[0]
    DIRECTION OUTPUT ;
    USE SIGNAL ;
    PORT
      LAYER M5 ;
        RECT  61.392 215.916 61.416 216 ;
    END
  END i_ids[0]
  PIN i_ids[10]
    DIRECTION OUTPUT ;
    USE SIGNAL ;
    PORT
      LAYER M5 ;
        RECT  63.312 215.916 63.336 216 ;
    END
  END i_ids[10]
  PIN i_ids[11]
    DIRECTION OUTPUT ;
    USE SIGNAL ;
    PORT
      LAYER M5 ;
        RECT  63.504 215.916 63.528 216 ;
    END
  END i_ids[11]
  PIN i_ids[12]
    DIRECTION OUTPUT ;
    USE SIGNAL ;
    PORT
      LAYER M5 ;
        RECT  63.696 215.916 63.72 216 ;
    END
  END i_ids[12]
  PIN i_ids[13]
    DIRECTION OUTPUT ;
    USE SIGNAL ;
    PORT
      LAYER M5 ;
        RECT  63.888 215.916 63.912 216 ;
    END
  END i_ids[13]
  PIN i_ids[14]
    DIRECTION OUTPUT ;
    USE SIGNAL ;
    PORT
      LAYER M5 ;
        RECT  64.08 215.916 64.104 216 ;
    END
  END i_ids[14]
  PIN i_ids[15]
    DIRECTION OUTPUT ;
    USE SIGNAL ;
    PORT
      LAYER M5 ;
        RECT  64.272 215.916 64.296 216 ;
    END
  END i_ids[15]
  PIN i_ids[16]
    DIRECTION OUTPUT ;
    USE SIGNAL ;
    PORT
      LAYER M5 ;
        RECT  64.464 215.916 64.488 216 ;
    END
  END i_ids[16]
  PIN i_ids[17]
    DIRECTION OUTPUT ;
    USE SIGNAL ;
    PORT
      LAYER M5 ;
        RECT  64.656 215.916 64.68 216 ;
    END
  END i_ids[17]
  PIN i_ids[18]
    DIRECTION OUTPUT ;
    USE SIGNAL ;
    PORT
      LAYER M5 ;
        RECT  64.848 215.916 64.872 216 ;
    END
  END i_ids[18]
  PIN i_ids[19]
    DIRECTION OUTPUT ;
    USE SIGNAL ;
    PORT
      LAYER M5 ;
        RECT  65.04 215.916 65.064 216 ;
    END
  END i_ids[19]
  PIN i_ids[1]
    DIRECTION OUTPUT ;
    USE SIGNAL ;
    PORT
      LAYER M5 ;
        RECT  61.584 215.916 61.608 216 ;
    END
  END i_ids[1]
  PIN i_ids[20]
    DIRECTION OUTPUT ;
    USE SIGNAL ;
    PORT
      LAYER M5 ;
        RECT  65.232 215.916 65.256 216 ;
    END
  END i_ids[20]
  PIN i_ids[21]
    DIRECTION OUTPUT ;
    USE SIGNAL ;
    PORT
      LAYER M5 ;
        RECT  65.424 215.916 65.448 216 ;
    END
  END i_ids[21]
  PIN i_ids[22]
    DIRECTION OUTPUT ;
    USE SIGNAL ;
    PORT
      LAYER M5 ;
        RECT  65.616 215.916 65.64 216 ;
    END
  END i_ids[22]
  PIN i_ids[23]
    DIRECTION OUTPUT ;
    USE SIGNAL ;
    PORT
      LAYER M5 ;
        RECT  65.808 215.916 65.832 216 ;
    END
  END i_ids[23]
  PIN i_ids[24]
    DIRECTION OUTPUT ;
    USE SIGNAL ;
    PORT
      LAYER M5 ;
        RECT  66 215.916 66.024 216 ;
    END
  END i_ids[24]
  PIN i_ids[25]
    DIRECTION OUTPUT ;
    USE SIGNAL ;
    PORT
      LAYER M5 ;
        RECT  66.192 215.916 66.216 216 ;
    END
  END i_ids[25]
  PIN i_ids[26]
    DIRECTION OUTPUT ;
    USE SIGNAL ;
    PORT
      LAYER M5 ;
        RECT  66.384 215.916 66.408 216 ;
    END
  END i_ids[26]
  PIN i_ids[27]
    DIRECTION OUTPUT ;
    USE SIGNAL ;
    PORT
      LAYER M5 ;
        RECT  66.576 215.916 66.6 216 ;
    END
  END i_ids[27]
  PIN i_ids[28]
    DIRECTION OUTPUT ;
    USE SIGNAL ;
    PORT
      LAYER M5 ;
        RECT  66.768 215.916 66.792 216 ;
    END
  END i_ids[28]
  PIN i_ids[29]
    DIRECTION OUTPUT ;
    USE SIGNAL ;
    PORT
      LAYER M5 ;
        RECT  66.96 215.916 66.984 216 ;
    END
  END i_ids[29]
  PIN i_ids[2]
    DIRECTION OUTPUT ;
    USE SIGNAL ;
    PORT
      LAYER M5 ;
        RECT  61.776 215.916 61.8 216 ;
    END
  END i_ids[2]
  PIN i_ids[30]
    DIRECTION OUTPUT ;
    USE SIGNAL ;
    PORT
      LAYER M5 ;
        RECT  67.152 215.916 67.176 216 ;
    END
  END i_ids[30]
  PIN i_ids[31]
    DIRECTION OUTPUT ;
    USE SIGNAL ;
    PORT
      LAYER M5 ;
        RECT  67.344 215.916 67.368 216 ;
    END
  END i_ids[31]
  PIN i_ids[32]
    DIRECTION OUTPUT ;
    USE SIGNAL ;
    PORT
      LAYER M5 ;
        RECT  67.536 215.916 67.56 216 ;
    END
  END i_ids[32]
  PIN i_ids[33]
    DIRECTION OUTPUT ;
    USE SIGNAL ;
    PORT
      LAYER M5 ;
        RECT  67.728 215.916 67.752 216 ;
    END
  END i_ids[33]
  PIN i_ids[34]
    DIRECTION OUTPUT ;
    USE SIGNAL ;
    PORT
      LAYER M5 ;
        RECT  67.92 215.916 67.944 216 ;
    END
  END i_ids[34]
  PIN i_ids[35]
    DIRECTION OUTPUT ;
    USE SIGNAL ;
    PORT
      LAYER M5 ;
        RECT  68.112 215.916 68.136 216 ;
    END
  END i_ids[35]
  PIN i_ids[36]
    DIRECTION OUTPUT ;
    USE SIGNAL ;
    PORT
      LAYER M5 ;
        RECT  68.304 215.916 68.328 216 ;
    END
  END i_ids[36]
  PIN i_ids[37]
    DIRECTION OUTPUT ;
    USE SIGNAL ;
    PORT
      LAYER M5 ;
        RECT  68.496 215.916 68.52 216 ;
    END
  END i_ids[37]
  PIN i_ids[38]
    DIRECTION OUTPUT ;
    USE SIGNAL ;
    PORT
      LAYER M5 ;
        RECT  68.688 215.916 68.712 216 ;
    END
  END i_ids[38]
  PIN i_ids[39]
    DIRECTION OUTPUT ;
    USE SIGNAL ;
    PORT
      LAYER M5 ;
        RECT  68.88 215.916 68.904 216 ;
    END
  END i_ids[39]
  PIN i_ids[3]
    DIRECTION OUTPUT ;
    USE SIGNAL ;
    PORT
      LAYER M5 ;
        RECT  61.968 215.916 61.992 216 ;
    END
  END i_ids[3]
  PIN i_ids[40]
    DIRECTION OUTPUT ;
    USE SIGNAL ;
    PORT
      LAYER M5 ;
        RECT  69.072 215.916 69.096 216 ;
    END
  END i_ids[40]
  PIN i_ids[41]
    DIRECTION OUTPUT ;
    USE SIGNAL ;
    PORT
      LAYER M5 ;
        RECT  69.264 215.916 69.288 216 ;
    END
  END i_ids[41]
  PIN i_ids[42]
    DIRECTION OUTPUT ;
    USE SIGNAL ;
    PORT
      LAYER M5 ;
        RECT  69.456 215.916 69.48 216 ;
    END
  END i_ids[42]
  PIN i_ids[43]
    DIRECTION OUTPUT ;
    USE SIGNAL ;
    PORT
      LAYER M5 ;
        RECT  69.648 215.916 69.672 216 ;
    END
  END i_ids[43]
  PIN i_ids[44]
    DIRECTION OUTPUT ;
    USE SIGNAL ;
    PORT
      LAYER M5 ;
        RECT  69.84 215.916 69.864 216 ;
    END
  END i_ids[44]
  PIN i_ids[45]
    DIRECTION OUTPUT ;
    USE SIGNAL ;
    PORT
      LAYER M5 ;
        RECT  70.032 215.916 70.056 216 ;
    END
  END i_ids[45]
  PIN i_ids[46]
    DIRECTION OUTPUT ;
    USE SIGNAL ;
    PORT
      LAYER M5 ;
        RECT  70.224 215.916 70.248 216 ;
    END
  END i_ids[46]
  PIN i_ids[47]
    DIRECTION OUTPUT ;
    USE SIGNAL ;
    PORT
      LAYER M5 ;
        RECT  70.416 215.916 70.44 216 ;
    END
  END i_ids[47]
  PIN i_ids[48]
    DIRECTION OUTPUT ;
    USE SIGNAL ;
    PORT
      LAYER M5 ;
        RECT  70.608 215.916 70.632 216 ;
    END
  END i_ids[48]
  PIN i_ids[49]
    DIRECTION OUTPUT ;
    USE SIGNAL ;
    PORT
      LAYER M5 ;
        RECT  70.8 215.916 70.824 216 ;
    END
  END i_ids[49]
  PIN i_ids[4]
    DIRECTION OUTPUT ;
    USE SIGNAL ;
    PORT
      LAYER M5 ;
        RECT  62.16 215.916 62.184 216 ;
    END
  END i_ids[4]
  PIN i_ids[50]
    DIRECTION OUTPUT ;
    USE SIGNAL ;
    PORT
      LAYER M5 ;
        RECT  70.992 215.916 71.016 216 ;
    END
  END i_ids[50]
  PIN i_ids[51]
    DIRECTION OUTPUT ;
    USE SIGNAL ;
    PORT
      LAYER M5 ;
        RECT  71.184 215.916 71.208 216 ;
    END
  END i_ids[51]
  PIN i_ids[52]
    DIRECTION OUTPUT ;
    USE SIGNAL ;
    PORT
      LAYER M5 ;
        RECT  71.376 215.916 71.4 216 ;
    END
  END i_ids[52]
  PIN i_ids[53]
    DIRECTION OUTPUT ;
    USE SIGNAL ;
    PORT
      LAYER M5 ;
        RECT  71.568 215.916 71.592 216 ;
    END
  END i_ids[53]
  PIN i_ids[5]
    DIRECTION OUTPUT ;
    USE SIGNAL ;
    PORT
      LAYER M5 ;
        RECT  62.352 215.916 62.376 216 ;
    END
  END i_ids[5]
  PIN i_ids[6]
    DIRECTION OUTPUT ;
    USE SIGNAL ;
    PORT
      LAYER M5 ;
        RECT  62.544 215.916 62.568 216 ;
    END
  END i_ids[6]
  PIN i_ids[7]
    DIRECTION OUTPUT ;
    USE SIGNAL ;
    PORT
      LAYER M5 ;
        RECT  62.736 215.916 62.76 216 ;
    END
  END i_ids[7]
  PIN i_ids[8]
    DIRECTION OUTPUT ;
    USE SIGNAL ;
    PORT
      LAYER M5 ;
        RECT  62.928 215.916 62.952 216 ;
    END
  END i_ids[8]
  PIN i_ids[9]
    DIRECTION OUTPUT ;
    USE SIGNAL ;
    PORT
      LAYER M5 ;
        RECT  63.12 215.916 63.144 216 ;
    END
  END i_ids[9]
  PIN i_v
    DIRECTION OUTPUT ;
    USE SIGNAL ;
    PORT
      LAYER M5 ;
        RECT  71.76 215.916 71.784 216 ;
    END
  END i_v
  PIN rst_n
    DIRECTION INPUT ;
    USE SIGNAL ;
    PORT
      LAYER M4 ;
        RECT  86.316 184.464 86.4 184.488 ;
    END
  END rst_n
  PIN s_d[0]
    DIRECTION OUTPUT ;
    USE SIGNAL ;
    PORT
      LAYER M5 ;
        RECT  71.952 215.916 71.976 216 ;
    END
  END s_d[0]
  PIN s_d[100]
    DIRECTION OUTPUT ;
    USE SIGNAL ;
    PORT
      LAYER M5 ;
        RECT  15.888 215.916 15.912 216 ;
    END
  END s_d[100]
  PIN s_d[101]
    DIRECTION OUTPUT ;
    USE SIGNAL ;
    PORT
      LAYER M5 ;
        RECT  16.08 215.916 16.104 216 ;
    END
  END s_d[101]
  PIN s_d[102]
    DIRECTION OUTPUT ;
    USE SIGNAL ;
    PORT
      LAYER M5 ;
        RECT  16.272 215.916 16.296 216 ;
    END
  END s_d[102]
  PIN s_d[103]
    DIRECTION OUTPUT ;
    USE SIGNAL ;
    PORT
      LAYER M5 ;
        RECT  16.464 215.916 16.488 216 ;
    END
  END s_d[103]
  PIN s_d[104]
    DIRECTION OUTPUT ;
    USE SIGNAL ;
    PORT
      LAYER M5 ;
        RECT  22.8 215.916 22.824 216 ;
    END
  END s_d[104]
  PIN s_d[105]
    DIRECTION OUTPUT ;
    USE SIGNAL ;
    PORT
      LAYER M5 ;
        RECT  22.992 215.916 23.016 216 ;
    END
  END s_d[105]
  PIN s_d[106]
    DIRECTION OUTPUT ;
    USE SIGNAL ;
    PORT
      LAYER M5 ;
        RECT  23.184 215.916 23.208 216 ;
    END
  END s_d[106]
  PIN s_d[107]
    DIRECTION OUTPUT ;
    USE SIGNAL ;
    PORT
      LAYER M5 ;
        RECT  23.376 215.916 23.4 216 ;
    END
  END s_d[107]
  PIN s_d[108]
    DIRECTION OUTPUT ;
    USE SIGNAL ;
    PORT
      LAYER M5 ;
        RECT  23.568 215.916 23.592 216 ;
    END
  END s_d[108]
  PIN s_d[109]
    DIRECTION OUTPUT ;
    USE SIGNAL ;
    PORT
      LAYER M5 ;
        RECT  23.76 215.916 23.784 216 ;
    END
  END s_d[109]
  PIN s_d[10]
    DIRECTION OUTPUT ;
    USE SIGNAL ;
    PORT
      LAYER M5 ;
        RECT  3.216 215.916 3.24 216 ;
    END
  END s_d[10]
  PIN s_d[110]
    DIRECTION OUTPUT ;
    USE SIGNAL ;
    PORT
      LAYER M5 ;
        RECT  23.952 215.916 23.976 216 ;
    END
  END s_d[110]
  PIN s_d[111]
    DIRECTION OUTPUT ;
    USE SIGNAL ;
    PORT
      LAYER M5 ;
        RECT  24.144 215.916 24.168 216 ;
    END
  END s_d[111]
  PIN s_d[112]
    DIRECTION OUTPUT ;
    USE SIGNAL ;
    PORT
      LAYER M5 ;
        RECT  24.336 215.916 24.36 216 ;
    END
  END s_d[112]
  PIN s_d[113]
    DIRECTION OUTPUT ;
    USE SIGNAL ;
    PORT
      LAYER M5 ;
        RECT  24.528 215.916 24.552 216 ;
    END
  END s_d[113]
  PIN s_d[114]
    DIRECTION OUTPUT ;
    USE SIGNAL ;
    PORT
      LAYER M5 ;
        RECT  24.72 215.916 24.744 216 ;
    END
  END s_d[114]
  PIN s_d[115]
    DIRECTION OUTPUT ;
    USE SIGNAL ;
    PORT
      LAYER M5 ;
        RECT  24.912 215.916 24.936 216 ;
    END
  END s_d[115]
  PIN s_d[116]
    DIRECTION OUTPUT ;
    USE SIGNAL ;
    PORT
      LAYER M5 ;
        RECT  25.104 215.916 25.128 216 ;
    END
  END s_d[116]
  PIN s_d[117]
    DIRECTION OUTPUT ;
    USE SIGNAL ;
    PORT
      LAYER M5 ;
        RECT  25.296 215.916 25.32 216 ;
    END
  END s_d[117]
  PIN s_d[118]
    DIRECTION OUTPUT ;
    USE SIGNAL ;
    PORT
      LAYER M5 ;
        RECT  25.488 215.916 25.512 216 ;
    END
  END s_d[118]
  PIN s_d[119]
    DIRECTION OUTPUT ;
    USE SIGNAL ;
    PORT
      LAYER M5 ;
        RECT  25.68 215.916 25.704 216 ;
    END
  END s_d[119]
  PIN s_d[11]
    DIRECTION OUTPUT ;
    USE SIGNAL ;
    PORT
      LAYER M5 ;
        RECT  3.408 215.916 3.432 216 ;
    END
  END s_d[11]
  PIN s_d[120]
    DIRECTION OUTPUT ;
    USE SIGNAL ;
    PORT
      LAYER M5 ;
        RECT  25.872 215.916 25.896 216 ;
    END
  END s_d[120]
  PIN s_d[121]
    DIRECTION OUTPUT ;
    USE SIGNAL ;
    PORT
      LAYER M5 ;
        RECT  26.064 215.916 26.088 216 ;
    END
  END s_d[121]
  PIN s_d[122]
    DIRECTION OUTPUT ;
    USE SIGNAL ;
    PORT
      LAYER M5 ;
        RECT  26.256 215.916 26.28 216 ;
    END
  END s_d[122]
  PIN s_d[123]
    DIRECTION OUTPUT ;
    USE SIGNAL ;
    PORT
      LAYER M5 ;
        RECT  26.448 215.916 26.472 216 ;
    END
  END s_d[123]
  PIN s_d[124]
    DIRECTION OUTPUT ;
    USE SIGNAL ;
    PORT
      LAYER M5 ;
        RECT  26.64 215.916 26.664 216 ;
    END
  END s_d[124]
  PIN s_d[125]
    DIRECTION OUTPUT ;
    USE SIGNAL ;
    PORT
      LAYER M5 ;
        RECT  26.832 215.916 26.856 216 ;
    END
  END s_d[125]
  PIN s_d[126]
    DIRECTION OUTPUT ;
    USE SIGNAL ;
    PORT
      LAYER M5 ;
        RECT  27.024 215.916 27.048 216 ;
    END
  END s_d[126]
  PIN s_d[127]
    DIRECTION OUTPUT ;
    USE SIGNAL ;
    PORT
      LAYER M5 ;
        RECT  27.216 215.916 27.24 216 ;
    END
  END s_d[127]
  PIN s_d[128]
    DIRECTION OUTPUT ;
    USE SIGNAL ;
    PORT
      LAYER M5 ;
        RECT  27.408 215.916 27.432 216 ;
    END
  END s_d[128]
  PIN s_d[129]
    DIRECTION OUTPUT ;
    USE SIGNAL ;
    PORT
      LAYER M5 ;
        RECT  27.6 215.916 27.624 216 ;
    END
  END s_d[129]
  PIN s_d[12]
    DIRECTION OUTPUT ;
    USE SIGNAL ;
    PORT
      LAYER M5 ;
        RECT  3.6 215.916 3.624 216 ;
    END
  END s_d[12]
  PIN s_d[130]
    DIRECTION OUTPUT ;
    USE SIGNAL ;
    PORT
      LAYER M5 ;
        RECT  27.792 215.916 27.816 216 ;
    END
  END s_d[130]
  PIN s_d[131]
    DIRECTION OUTPUT ;
    USE SIGNAL ;
    PORT
      LAYER M5 ;
        RECT  27.984 215.916 28.008 216 ;
    END
  END s_d[131]
  PIN s_d[132]
    DIRECTION OUTPUT ;
    USE SIGNAL ;
    PORT
      LAYER M5 ;
        RECT  28.176 215.916 28.2 216 ;
    END
  END s_d[132]
  PIN s_d[133]
    DIRECTION OUTPUT ;
    USE SIGNAL ;
    PORT
      LAYER M5 ;
        RECT  28.368 215.916 28.392 216 ;
    END
  END s_d[133]
  PIN s_d[134]
    DIRECTION OUTPUT ;
    USE SIGNAL ;
    PORT
      LAYER M5 ;
        RECT  28.56 215.916 28.584 216 ;
    END
  END s_d[134]
  PIN s_d[135]
    DIRECTION OUTPUT ;
    USE SIGNAL ;
    PORT
      LAYER M5 ;
        RECT  28.752 215.916 28.776 216 ;
    END
  END s_d[135]
  PIN s_d[136]
    DIRECTION OUTPUT ;
    USE SIGNAL ;
    PORT
      LAYER M5 ;
        RECT  28.944 215.916 28.968 216 ;
    END
  END s_d[136]
  PIN s_d[137]
    DIRECTION OUTPUT ;
    USE SIGNAL ;
    PORT
      LAYER M5 ;
        RECT  29.136 215.916 29.16 216 ;
    END
  END s_d[137]
  PIN s_d[138]
    DIRECTION OUTPUT ;
    USE SIGNAL ;
    PORT
      LAYER M5 ;
        RECT  29.328 215.916 29.352 216 ;
    END
  END s_d[138]
  PIN s_d[139]
    DIRECTION OUTPUT ;
    USE SIGNAL ;
    PORT
      LAYER M5 ;
        RECT  29.52 215.916 29.544 216 ;
    END
  END s_d[139]
  PIN s_d[13]
    DIRECTION OUTPUT ;
    USE SIGNAL ;
    PORT
      LAYER M5 ;
        RECT  3.792 215.916 3.816 216 ;
    END
  END s_d[13]
  PIN s_d[140]
    DIRECTION OUTPUT ;
    USE SIGNAL ;
    PORT
      LAYER M5 ;
        RECT  29.712 215.916 29.736 216 ;
    END
  END s_d[140]
  PIN s_d[141]
    DIRECTION OUTPUT ;
    USE SIGNAL ;
    PORT
      LAYER M5 ;
        RECT  29.904 215.916 29.928 216 ;
    END
  END s_d[141]
  PIN s_d[142]
    DIRECTION OUTPUT ;
    USE SIGNAL ;
    PORT
      LAYER M5 ;
        RECT  30.096 215.916 30.12 216 ;
    END
  END s_d[142]
  PIN s_d[143]
    DIRECTION OUTPUT ;
    USE SIGNAL ;
    PORT
      LAYER M5 ;
        RECT  30.288 215.916 30.312 216 ;
    END
  END s_d[143]
  PIN s_d[144]
    DIRECTION OUTPUT ;
    USE SIGNAL ;
    PORT
      LAYER M5 ;
        RECT  30.48 215.916 30.504 216 ;
    END
  END s_d[144]
  PIN s_d[145]
    DIRECTION OUTPUT ;
    USE SIGNAL ;
    PORT
      LAYER M5 ;
        RECT  30.672 215.916 30.696 216 ;
    END
  END s_d[145]
  PIN s_d[146]
    DIRECTION OUTPUT ;
    USE SIGNAL ;
    PORT
      LAYER M5 ;
        RECT  30.864 215.916 30.888 216 ;
    END
  END s_d[146]
  PIN s_d[147]
    DIRECTION OUTPUT ;
    USE SIGNAL ;
    PORT
      LAYER M5 ;
        RECT  31.056 215.916 31.08 216 ;
    END
  END s_d[147]
  PIN s_d[148]
    DIRECTION OUTPUT ;
    USE SIGNAL ;
    PORT
      LAYER M5 ;
        RECT  31.248 215.916 31.272 216 ;
    END
  END s_d[148]
  PIN s_d[149]
    DIRECTION OUTPUT ;
    USE SIGNAL ;
    PORT
      LAYER M5 ;
        RECT  31.44 215.916 31.464 216 ;
    END
  END s_d[149]
  PIN s_d[14]
    DIRECTION OUTPUT ;
    USE SIGNAL ;
    PORT
      LAYER M5 ;
        RECT  3.984 215.916 4.008 216 ;
    END
  END s_d[14]
  PIN s_d[150]
    DIRECTION OUTPUT ;
    USE SIGNAL ;
    PORT
      LAYER M5 ;
        RECT  31.632 215.916 31.656 216 ;
    END
  END s_d[150]
  PIN s_d[151]
    DIRECTION OUTPUT ;
    USE SIGNAL ;
    PORT
      LAYER M5 ;
        RECT  31.824 215.916 31.848 216 ;
    END
  END s_d[151]
  PIN s_d[152]
    DIRECTION OUTPUT ;
    USE SIGNAL ;
    PORT
      LAYER M5 ;
        RECT  32.016 215.916 32.04 216 ;
    END
  END s_d[152]
  PIN s_d[153]
    DIRECTION OUTPUT ;
    USE SIGNAL ;
    PORT
      LAYER M5 ;
        RECT  32.208 215.916 32.232 216 ;
    END
  END s_d[153]
  PIN s_d[154]
    DIRECTION OUTPUT ;
    USE SIGNAL ;
    PORT
      LAYER M5 ;
        RECT  32.4 215.916 32.424 216 ;
    END
  END s_d[154]
  PIN s_d[155]
    DIRECTION OUTPUT ;
    USE SIGNAL ;
    PORT
      LAYER M5 ;
        RECT  32.592 215.916 32.616 216 ;
    END
  END s_d[155]
  PIN s_d[156]
    DIRECTION OUTPUT ;
    USE SIGNAL ;
    PORT
      LAYER M5 ;
        RECT  32.784 215.916 32.808 216 ;
    END
  END s_d[156]
  PIN s_d[157]
    DIRECTION OUTPUT ;
    USE SIGNAL ;
    PORT
      LAYER M5 ;
        RECT  32.976 215.916 33 216 ;
    END
  END s_d[157]
  PIN s_d[158]
    DIRECTION OUTPUT ;
    USE SIGNAL ;
    PORT
      LAYER M5 ;
        RECT  33.168 215.916 33.192 216 ;
    END
  END s_d[158]
  PIN s_d[159]
    DIRECTION OUTPUT ;
    USE SIGNAL ;
    PORT
      LAYER M5 ;
        RECT  33.36 215.916 33.384 216 ;
    END
  END s_d[159]
  PIN s_d[15]
    DIRECTION OUTPUT ;
    USE SIGNAL ;
    PORT
      LAYER M5 ;
        RECT  4.176 215.916 4.2 216 ;
    END
  END s_d[15]
  PIN s_d[160]
    DIRECTION OUTPUT ;
    USE SIGNAL ;
    PORT
      LAYER M5 ;
        RECT  33.552 215.916 33.576 216 ;
    END
  END s_d[160]
  PIN s_d[161]
    DIRECTION OUTPUT ;
    USE SIGNAL ;
    PORT
      LAYER M5 ;
        RECT  33.744 215.916 33.768 216 ;
    END
  END s_d[161]
  PIN s_d[162]
    DIRECTION OUTPUT ;
    USE SIGNAL ;
    PORT
      LAYER M5 ;
        RECT  33.936 215.916 33.96 216 ;
    END
  END s_d[162]
  PIN s_d[163]
    DIRECTION OUTPUT ;
    USE SIGNAL ;
    PORT
      LAYER M5 ;
        RECT  34.128 215.916 34.152 216 ;
    END
  END s_d[163]
  PIN s_d[164]
    DIRECTION OUTPUT ;
    USE SIGNAL ;
    PORT
      LAYER M5 ;
        RECT  34.32 215.916 34.344 216 ;
    END
  END s_d[164]
  PIN s_d[165]
    DIRECTION OUTPUT ;
    USE SIGNAL ;
    PORT
      LAYER M5 ;
        RECT  34.512 215.916 34.536 216 ;
    END
  END s_d[165]
  PIN s_d[166]
    DIRECTION OUTPUT ;
    USE SIGNAL ;
    PORT
      LAYER M5 ;
        RECT  34.704 215.916 34.728 216 ;
    END
  END s_d[166]
  PIN s_d[167]
    DIRECTION OUTPUT ;
    USE SIGNAL ;
    PORT
      LAYER M5 ;
        RECT  34.896 215.916 34.92 216 ;
    END
  END s_d[167]
  PIN s_d[168]
    DIRECTION OUTPUT ;
    USE SIGNAL ;
    PORT
      LAYER M5 ;
        RECT  36.432 215.916 36.456 216 ;
    END
  END s_d[168]
  PIN s_d[169]
    DIRECTION OUTPUT ;
    USE SIGNAL ;
    PORT
      LAYER M5 ;
        RECT  36.624 215.916 36.648 216 ;
    END
  END s_d[169]
  PIN s_d[16]
    DIRECTION OUTPUT ;
    USE SIGNAL ;
    PORT
      LAYER M5 ;
        RECT  4.368 215.916 4.392 216 ;
    END
  END s_d[16]
  PIN s_d[170]
    DIRECTION OUTPUT ;
    USE SIGNAL ;
    PORT
      LAYER M5 ;
        RECT  36.816 215.916 36.84 216 ;
    END
  END s_d[170]
  PIN s_d[171]
    DIRECTION OUTPUT ;
    USE SIGNAL ;
    PORT
      LAYER M5 ;
        RECT  37.008 215.916 37.032 216 ;
    END
  END s_d[171]
  PIN s_d[172]
    DIRECTION OUTPUT ;
    USE SIGNAL ;
    PORT
      LAYER M5 ;
        RECT  37.2 215.916 37.224 216 ;
    END
  END s_d[172]
  PIN s_d[173]
    DIRECTION OUTPUT ;
    USE SIGNAL ;
    PORT
      LAYER M5 ;
        RECT  37.392 215.916 37.416 216 ;
    END
  END s_d[173]
  PIN s_d[174]
    DIRECTION OUTPUT ;
    USE SIGNAL ;
    PORT
      LAYER M5 ;
        RECT  37.584 215.916 37.608 216 ;
    END
  END s_d[174]
  PIN s_d[175]
    DIRECTION OUTPUT ;
    USE SIGNAL ;
    PORT
      LAYER M5 ;
        RECT  37.776 215.916 37.8 216 ;
    END
  END s_d[175]
  PIN s_d[176]
    DIRECTION OUTPUT ;
    USE SIGNAL ;
    PORT
      LAYER M5 ;
        RECT  37.968 215.916 37.992 216 ;
    END
  END s_d[176]
  PIN s_d[177]
    DIRECTION OUTPUT ;
    USE SIGNAL ;
    PORT
      LAYER M5 ;
        RECT  38.16 215.916 38.184 216 ;
    END
  END s_d[177]
  PIN s_d[178]
    DIRECTION OUTPUT ;
    USE SIGNAL ;
    PORT
      LAYER M5 ;
        RECT  38.352 215.916 38.376 216 ;
    END
  END s_d[178]
  PIN s_d[179]
    DIRECTION OUTPUT ;
    USE SIGNAL ;
    PORT
      LAYER M5 ;
        RECT  38.544 215.916 38.568 216 ;
    END
  END s_d[179]
  PIN s_d[17]
    DIRECTION OUTPUT ;
    USE SIGNAL ;
    PORT
      LAYER M5 ;
        RECT  4.56 215.916 4.584 216 ;
    END
  END s_d[17]
  PIN s_d[180]
    DIRECTION OUTPUT ;
    USE SIGNAL ;
    PORT
      LAYER M5 ;
        RECT  38.736 215.916 38.76 216 ;
    END
  END s_d[180]
  PIN s_d[181]
    DIRECTION OUTPUT ;
    USE SIGNAL ;
    PORT
      LAYER M5 ;
        RECT  38.928 215.916 38.952 216 ;
    END
  END s_d[181]
  PIN s_d[182]
    DIRECTION OUTPUT ;
    USE SIGNAL ;
    PORT
      LAYER M5 ;
        RECT  39.12 215.916 39.144 216 ;
    END
  END s_d[182]
  PIN s_d[183]
    DIRECTION OUTPUT ;
    USE SIGNAL ;
    PORT
      LAYER M5 ;
        RECT  39.312 215.916 39.336 216 ;
    END
  END s_d[183]
  PIN s_d[184]
    DIRECTION OUTPUT ;
    USE SIGNAL ;
    PORT
      LAYER M5 ;
        RECT  39.504 215.916 39.528 216 ;
    END
  END s_d[184]
  PIN s_d[185]
    DIRECTION OUTPUT ;
    USE SIGNAL ;
    PORT
      LAYER M5 ;
        RECT  39.696 215.916 39.72 216 ;
    END
  END s_d[185]
  PIN s_d[186]
    DIRECTION OUTPUT ;
    USE SIGNAL ;
    PORT
      LAYER M5 ;
        RECT  39.888 215.916 39.912 216 ;
    END
  END s_d[186]
  PIN s_d[187]
    DIRECTION OUTPUT ;
    USE SIGNAL ;
    PORT
      LAYER M5 ;
        RECT  40.08 215.916 40.104 216 ;
    END
  END s_d[187]
  PIN s_d[188]
    DIRECTION OUTPUT ;
    USE SIGNAL ;
    PORT
      LAYER M5 ;
        RECT  40.272 215.916 40.296 216 ;
    END
  END s_d[188]
  PIN s_d[189]
    DIRECTION OUTPUT ;
    USE SIGNAL ;
    PORT
      LAYER M5 ;
        RECT  40.464 215.916 40.488 216 ;
    END
  END s_d[189]
  PIN s_d[18]
    DIRECTION OUTPUT ;
    USE SIGNAL ;
    PORT
      LAYER M5 ;
        RECT  4.752 215.916 4.776 216 ;
    END
  END s_d[18]
  PIN s_d[190]
    DIRECTION OUTPUT ;
    USE SIGNAL ;
    PORT
      LAYER M5 ;
        RECT  40.656 215.916 40.68 216 ;
    END
  END s_d[190]
  PIN s_d[191]
    DIRECTION OUTPUT ;
    USE SIGNAL ;
    PORT
      LAYER M5 ;
        RECT  40.848 215.916 40.872 216 ;
    END
  END s_d[191]
  PIN s_d[19]
    DIRECTION OUTPUT ;
    USE SIGNAL ;
    PORT
      LAYER M5 ;
        RECT  4.944 215.916 4.968 216 ;
    END
  END s_d[19]
  PIN s_d[1]
    DIRECTION OUTPUT ;
    USE SIGNAL ;
    PORT
      LAYER M5 ;
        RECT  72.144 215.916 72.168 216 ;
    END
  END s_d[1]
  PIN s_d[20]
    DIRECTION OUTPUT ;
    USE SIGNAL ;
    PORT
      LAYER M5 ;
        RECT  5.136 215.916 5.16 216 ;
    END
  END s_d[20]
  PIN s_d[21]
    DIRECTION OUTPUT ;
    USE SIGNAL ;
    PORT
      LAYER M5 ;
        RECT  5.328 215.916 5.352 216 ;
    END
  END s_d[21]
  PIN s_d[22]
    DIRECTION OUTPUT ;
    USE SIGNAL ;
    PORT
      LAYER M5 ;
        RECT  5.52 215.916 5.544 216 ;
    END
  END s_d[22]
  PIN s_d[23]
    DIRECTION OUTPUT ;
    USE SIGNAL ;
    PORT
      LAYER M5 ;
        RECT  5.712 215.916 5.736 216 ;
    END
  END s_d[23]
  PIN s_d[24]
    DIRECTION OUTPUT ;
    USE SIGNAL ;
    PORT
      LAYER M5 ;
        RECT  5.904 215.916 5.928 216 ;
    END
  END s_d[24]
  PIN s_d[25]
    DIRECTION OUTPUT ;
    USE SIGNAL ;
    PORT
      LAYER M5 ;
        RECT  6.096 215.916 6.12 216 ;
    END
  END s_d[25]
  PIN s_d[26]
    DIRECTION OUTPUT ;
    USE SIGNAL ;
    PORT
      LAYER M5 ;
        RECT  6.288 215.916 6.312 216 ;
    END
  END s_d[26]
  PIN s_d[27]
    DIRECTION OUTPUT ;
    USE SIGNAL ;
    PORT
      LAYER M5 ;
        RECT  6.48 215.916 6.504 216 ;
    END
  END s_d[27]
  PIN s_d[28]
    DIRECTION OUTPUT ;
    USE SIGNAL ;
    PORT
      LAYER M5 ;
        RECT  6.672 215.916 6.696 216 ;
    END
  END s_d[28]
  PIN s_d[29]
    DIRECTION OUTPUT ;
    USE SIGNAL ;
    PORT
      LAYER M5 ;
        RECT  6.864 215.916 6.888 216 ;
    END
  END s_d[29]
  PIN s_d[2]
    DIRECTION OUTPUT ;
    USE SIGNAL ;
    PORT
      LAYER M5 ;
        RECT  72.336 215.916 72.36 216 ;
    END
  END s_d[2]
  PIN s_d[30]
    DIRECTION OUTPUT ;
    USE SIGNAL ;
    PORT
      LAYER M5 ;
        RECT  7.056 215.916 7.08 216 ;
    END
  END s_d[30]
  PIN s_d[31]
    DIRECTION OUTPUT ;
    USE SIGNAL ;
    PORT
      LAYER M5 ;
        RECT  7.248 215.916 7.272 216 ;
    END
  END s_d[31]
  PIN s_d[32]
    DIRECTION OUTPUT ;
    USE SIGNAL ;
    PORT
      LAYER M5 ;
        RECT  7.44 215.916 7.464 216 ;
    END
  END s_d[32]
  PIN s_d[33]
    DIRECTION OUTPUT ;
    USE SIGNAL ;
    PORT
      LAYER M5 ;
        RECT  7.632 215.916 7.656 216 ;
    END
  END s_d[33]
  PIN s_d[34]
    DIRECTION OUTPUT ;
    USE SIGNAL ;
    PORT
      LAYER M5 ;
        RECT  7.824 215.916 7.848 216 ;
    END
  END s_d[34]
  PIN s_d[35]
    DIRECTION OUTPUT ;
    USE SIGNAL ;
    PORT
      LAYER M5 ;
        RECT  8.016 215.916 8.04 216 ;
    END
  END s_d[35]
  PIN s_d[36]
    DIRECTION OUTPUT ;
    USE SIGNAL ;
    PORT
      LAYER M5 ;
        RECT  8.208 215.916 8.232 216 ;
    END
  END s_d[36]
  PIN s_d[37]
    DIRECTION OUTPUT ;
    USE SIGNAL ;
    PORT
      LAYER M5 ;
        RECT  8.4 215.916 8.424 216 ;
    END
  END s_d[37]
  PIN s_d[38]
    DIRECTION OUTPUT ;
    USE SIGNAL ;
    PORT
      LAYER M5 ;
        RECT  8.592 215.916 8.616 216 ;
    END
  END s_d[38]
  PIN s_d[39]
    DIRECTION OUTPUT ;
    USE SIGNAL ;
    PORT
      LAYER M5 ;
        RECT  8.784 215.916 8.808 216 ;
    END
  END s_d[39]
  PIN s_d[3]
    DIRECTION OUTPUT ;
    USE SIGNAL ;
    PORT
      LAYER M5 ;
        RECT  72.528 215.916 72.552 216 ;
    END
  END s_d[3]
  PIN s_d[40]
    DIRECTION OUTPUT ;
    USE SIGNAL ;
    PORT
      LAYER M5 ;
        RECT  16.656 215.916 16.68 216 ;
    END
  END s_d[40]
  PIN s_d[41]
    DIRECTION OUTPUT ;
    USE SIGNAL ;
    PORT
      LAYER M5 ;
        RECT  16.848 215.916 16.872 216 ;
    END
  END s_d[41]
  PIN s_d[42]
    DIRECTION OUTPUT ;
    USE SIGNAL ;
    PORT
      LAYER M5 ;
        RECT  17.04 215.916 17.064 216 ;
    END
  END s_d[42]
  PIN s_d[43]
    DIRECTION OUTPUT ;
    USE SIGNAL ;
    PORT
      LAYER M5 ;
        RECT  17.232 215.916 17.256 216 ;
    END
  END s_d[43]
  PIN s_d[44]
    DIRECTION OUTPUT ;
    USE SIGNAL ;
    PORT
      LAYER M5 ;
        RECT  17.424 215.916 17.448 216 ;
    END
  END s_d[44]
  PIN s_d[45]
    DIRECTION OUTPUT ;
    USE SIGNAL ;
    PORT
      LAYER M5 ;
        RECT  17.616 215.916 17.64 216 ;
    END
  END s_d[45]
  PIN s_d[46]
    DIRECTION OUTPUT ;
    USE SIGNAL ;
    PORT
      LAYER M5 ;
        RECT  17.808 215.916 17.832 216 ;
    END
  END s_d[46]
  PIN s_d[47]
    DIRECTION OUTPUT ;
    USE SIGNAL ;
    PORT
      LAYER M5 ;
        RECT  18 215.916 18.024 216 ;
    END
  END s_d[47]
  PIN s_d[48]
    DIRECTION OUTPUT ;
    USE SIGNAL ;
    PORT
      LAYER M5 ;
        RECT  18.192 215.916 18.216 216 ;
    END
  END s_d[48]
  PIN s_d[49]
    DIRECTION OUTPUT ;
    USE SIGNAL ;
    PORT
      LAYER M5 ;
        RECT  18.384 215.916 18.408 216 ;
    END
  END s_d[49]
  PIN s_d[4]
    DIRECTION OUTPUT ;
    USE SIGNAL ;
    PORT
      LAYER M5 ;
        RECT  72.72 215.916 72.744 216 ;
    END
  END s_d[4]
  PIN s_d[50]
    DIRECTION OUTPUT ;
    USE SIGNAL ;
    PORT
      LAYER M5 ;
        RECT  18.576 215.916 18.6 216 ;
    END
  END s_d[50]
  PIN s_d[51]
    DIRECTION OUTPUT ;
    USE SIGNAL ;
    PORT
      LAYER M5 ;
        RECT  18.768 215.916 18.792 216 ;
    END
  END s_d[51]
  PIN s_d[52]
    DIRECTION OUTPUT ;
    USE SIGNAL ;
    PORT
      LAYER M5 ;
        RECT  18.96 215.916 18.984 216 ;
    END
  END s_d[52]
  PIN s_d[53]
    DIRECTION OUTPUT ;
    USE SIGNAL ;
    PORT
      LAYER M5 ;
        RECT  19.152 215.916 19.176 216 ;
    END
  END s_d[53]
  PIN s_d[54]
    DIRECTION OUTPUT ;
    USE SIGNAL ;
    PORT
      LAYER M5 ;
        RECT  19.344 215.916 19.368 216 ;
    END
  END s_d[54]
  PIN s_d[55]
    DIRECTION OUTPUT ;
    USE SIGNAL ;
    PORT
      LAYER M5 ;
        RECT  19.536 215.916 19.56 216 ;
    END
  END s_d[55]
  PIN s_d[56]
    DIRECTION OUTPUT ;
    USE SIGNAL ;
    PORT
      LAYER M5 ;
        RECT  19.728 215.916 19.752 216 ;
    END
  END s_d[56]
  PIN s_d[57]
    DIRECTION OUTPUT ;
    USE SIGNAL ;
    PORT
      LAYER M5 ;
        RECT  19.92 215.916 19.944 216 ;
    END
  END s_d[57]
  PIN s_d[58]
    DIRECTION OUTPUT ;
    USE SIGNAL ;
    PORT
      LAYER M5 ;
        RECT  20.112 215.916 20.136 216 ;
    END
  END s_d[58]
  PIN s_d[59]
    DIRECTION OUTPUT ;
    USE SIGNAL ;
    PORT
      LAYER M5 ;
        RECT  20.304 215.916 20.328 216 ;
    END
  END s_d[59]
  PIN s_d[5]
    DIRECTION OUTPUT ;
    USE SIGNAL ;
    PORT
      LAYER M5 ;
        RECT  72.912 215.916 72.936 216 ;
    END
  END s_d[5]
  PIN s_d[60]
    DIRECTION OUTPUT ;
    USE SIGNAL ;
    PORT
      LAYER M5 ;
        RECT  20.496 215.916 20.52 216 ;
    END
  END s_d[60]
  PIN s_d[61]
    DIRECTION OUTPUT ;
    USE SIGNAL ;
    PORT
      LAYER M5 ;
        RECT  20.688 215.916 20.712 216 ;
    END
  END s_d[61]
  PIN s_d[62]
    DIRECTION OUTPUT ;
    USE SIGNAL ;
    PORT
      LAYER M5 ;
        RECT  20.88 215.916 20.904 216 ;
    END
  END s_d[62]
  PIN s_d[63]
    DIRECTION OUTPUT ;
    USE SIGNAL ;
    PORT
      LAYER M5 ;
        RECT  21.072 215.916 21.096 216 ;
    END
  END s_d[63]
  PIN s_d[64]
    DIRECTION OUTPUT ;
    USE SIGNAL ;
    PORT
      LAYER M5 ;
        RECT  21.264 215.916 21.288 216 ;
    END
  END s_d[64]
  PIN s_d[65]
    DIRECTION OUTPUT ;
    USE SIGNAL ;
    PORT
      LAYER M5 ;
        RECT  21.456 215.916 21.48 216 ;
    END
  END s_d[65]
  PIN s_d[66]
    DIRECTION OUTPUT ;
    USE SIGNAL ;
    PORT
      LAYER M5 ;
        RECT  21.648 215.916 21.672 216 ;
    END
  END s_d[66]
  PIN s_d[67]
    DIRECTION OUTPUT ;
    USE SIGNAL ;
    PORT
      LAYER M5 ;
        RECT  21.84 215.916 21.864 216 ;
    END
  END s_d[67]
  PIN s_d[68]
    DIRECTION OUTPUT ;
    USE SIGNAL ;
    PORT
      LAYER M5 ;
        RECT  22.032 215.916 22.056 216 ;
    END
  END s_d[68]
  PIN s_d[69]
    DIRECTION OUTPUT ;
    USE SIGNAL ;
    PORT
      LAYER M5 ;
        RECT  22.224 215.916 22.248 216 ;
    END
  END s_d[69]
  PIN s_d[6]
    DIRECTION OUTPUT ;
    USE SIGNAL ;
    PORT
      LAYER M5 ;
        RECT  73.104 215.916 73.128 216 ;
    END
  END s_d[6]
  PIN s_d[70]
    DIRECTION OUTPUT ;
    USE SIGNAL ;
    PORT
      LAYER M5 ;
        RECT  22.416 215.916 22.44 216 ;
    END
  END s_d[70]
  PIN s_d[71]
    DIRECTION OUTPUT ;
    USE SIGNAL ;
    PORT
      LAYER M5 ;
        RECT  22.608 215.916 22.632 216 ;
    END
  END s_d[71]
  PIN s_d[72]
    DIRECTION OUTPUT ;
    USE SIGNAL ;
    PORT
      LAYER M5 ;
        RECT  10.512 215.916 10.536 216 ;
    END
  END s_d[72]
  PIN s_d[73]
    DIRECTION OUTPUT ;
    USE SIGNAL ;
    PORT
      LAYER M5 ;
        RECT  10.704 215.916 10.728 216 ;
    END
  END s_d[73]
  PIN s_d[74]
    DIRECTION OUTPUT ;
    USE SIGNAL ;
    PORT
      LAYER M5 ;
        RECT  10.896 215.916 10.92 216 ;
    END
  END s_d[74]
  PIN s_d[75]
    DIRECTION OUTPUT ;
    USE SIGNAL ;
    PORT
      LAYER M5 ;
        RECT  11.088 215.916 11.112 216 ;
    END
  END s_d[75]
  PIN s_d[76]
    DIRECTION OUTPUT ;
    USE SIGNAL ;
    PORT
      LAYER M5 ;
        RECT  11.28 215.916 11.304 216 ;
    END
  END s_d[76]
  PIN s_d[77]
    DIRECTION OUTPUT ;
    USE SIGNAL ;
    PORT
      LAYER M5 ;
        RECT  11.472 215.916 11.496 216 ;
    END
  END s_d[77]
  PIN s_d[78]
    DIRECTION OUTPUT ;
    USE SIGNAL ;
    PORT
      LAYER M5 ;
        RECT  11.664 215.916 11.688 216 ;
    END
  END s_d[78]
  PIN s_d[79]
    DIRECTION OUTPUT ;
    USE SIGNAL ;
    PORT
      LAYER M5 ;
        RECT  11.856 215.916 11.88 216 ;
    END
  END s_d[79]
  PIN s_d[7]
    DIRECTION OUTPUT ;
    USE SIGNAL ;
    PORT
      LAYER M5 ;
        RECT  73.296 215.916 73.32 216 ;
    END
  END s_d[7]
  PIN s_d[80]
    DIRECTION OUTPUT ;
    USE SIGNAL ;
    PORT
      LAYER M5 ;
        RECT  12.048 215.916 12.072 216 ;
    END
  END s_d[80]
  PIN s_d[81]
    DIRECTION OUTPUT ;
    USE SIGNAL ;
    PORT
      LAYER M5 ;
        RECT  12.24 215.916 12.264 216 ;
    END
  END s_d[81]
  PIN s_d[82]
    DIRECTION OUTPUT ;
    USE SIGNAL ;
    PORT
      LAYER M5 ;
        RECT  12.432 215.916 12.456 216 ;
    END
  END s_d[82]
  PIN s_d[83]
    DIRECTION OUTPUT ;
    USE SIGNAL ;
    PORT
      LAYER M5 ;
        RECT  12.624 215.916 12.648 216 ;
    END
  END s_d[83]
  PIN s_d[84]
    DIRECTION OUTPUT ;
    USE SIGNAL ;
    PORT
      LAYER M5 ;
        RECT  12.816 215.916 12.84 216 ;
    END
  END s_d[84]
  PIN s_d[85]
    DIRECTION OUTPUT ;
    USE SIGNAL ;
    PORT
      LAYER M5 ;
        RECT  13.008 215.916 13.032 216 ;
    END
  END s_d[85]
  PIN s_d[86]
    DIRECTION OUTPUT ;
    USE SIGNAL ;
    PORT
      LAYER M5 ;
        RECT  13.2 215.916 13.224 216 ;
    END
  END s_d[86]
  PIN s_d[87]
    DIRECTION OUTPUT ;
    USE SIGNAL ;
    PORT
      LAYER M5 ;
        RECT  13.392 215.916 13.416 216 ;
    END
  END s_d[87]
  PIN s_d[88]
    DIRECTION OUTPUT ;
    USE SIGNAL ;
    PORT
      LAYER M5 ;
        RECT  13.584 215.916 13.608 216 ;
    END
  END s_d[88]
  PIN s_d[89]
    DIRECTION OUTPUT ;
    USE SIGNAL ;
    PORT
      LAYER M5 ;
        RECT  13.776 215.916 13.8 216 ;
    END
  END s_d[89]
  PIN s_d[8]
    DIRECTION OUTPUT ;
    USE SIGNAL ;
    PORT
      LAYER M5 ;
        RECT  2.832 215.916 2.856 216 ;
    END
  END s_d[8]
  PIN s_d[90]
    DIRECTION OUTPUT ;
    USE SIGNAL ;
    PORT
      LAYER M5 ;
        RECT  13.968 215.916 13.992 216 ;
    END
  END s_d[90]
  PIN s_d[91]
    DIRECTION OUTPUT ;
    USE SIGNAL ;
    PORT
      LAYER M5 ;
        RECT  14.16 215.916 14.184 216 ;
    END
  END s_d[91]
  PIN s_d[92]
    DIRECTION OUTPUT ;
    USE SIGNAL ;
    PORT
      LAYER M5 ;
        RECT  14.352 215.916 14.376 216 ;
    END
  END s_d[92]
  PIN s_d[93]
    DIRECTION OUTPUT ;
    USE SIGNAL ;
    PORT
      LAYER M5 ;
        RECT  14.544 215.916 14.568 216 ;
    END
  END s_d[93]
  PIN s_d[94]
    DIRECTION OUTPUT ;
    USE SIGNAL ;
    PORT
      LAYER M5 ;
        RECT  14.736 215.916 14.76 216 ;
    END
  END s_d[94]
  PIN s_d[95]
    DIRECTION OUTPUT ;
    USE SIGNAL ;
    PORT
      LAYER M5 ;
        RECT  14.928 215.916 14.952 216 ;
    END
  END s_d[95]
  PIN s_d[96]
    DIRECTION OUTPUT ;
    USE SIGNAL ;
    PORT
      LAYER M5 ;
        RECT  15.12 215.916 15.144 216 ;
    END
  END s_d[96]
  PIN s_d[97]
    DIRECTION OUTPUT ;
    USE SIGNAL ;
    PORT
      LAYER M5 ;
        RECT  15.312 215.916 15.336 216 ;
    END
  END s_d[97]
  PIN s_d[98]
    DIRECTION OUTPUT ;
    USE SIGNAL ;
    PORT
      LAYER M5 ;
        RECT  15.504 215.916 15.528 216 ;
    END
  END s_d[98]
  PIN s_d[99]
    DIRECTION OUTPUT ;
    USE SIGNAL ;
    PORT
      LAYER M5 ;
        RECT  15.696 215.916 15.72 216 ;
    END
  END s_d[99]
  PIN s_d[9]
    DIRECTION OUTPUT ;
    USE SIGNAL ;
    PORT
      LAYER M5 ;
        RECT  3.024 215.916 3.048 216 ;
    END
  END s_d[9]
  PIN s_v
    DIRECTION OUTPUT ;
    USE SIGNAL ;
    PORT
      LAYER M5 ;
        RECT  41.04 215.916 41.064 216 ;
    END
  END s_v
  PIN VDD
    DIRECTION INOUT ;
    USE POWER ;
    PORT
      LAYER M5 ;
        RECT  79.956 4.311 80.076 211.689 ;
        RECT  75.636 4.311 75.756 211.689 ;
        RECT  71.316 4.311 71.436 211.689 ;
        RECT  66.996 4.311 67.116 211.689 ;
        RECT  62.676 4.311 62.796 211.689 ;
        RECT  58.356 4.311 58.476 211.689 ;
        RECT  54.036 4.311 54.156 211.689 ;
        RECT  49.716 4.311 49.836 211.689 ;
        RECT  45.396 4.311 45.516 211.689 ;
        RECT  41.076 4.311 41.196 211.689 ;
        RECT  36.756 4.311 36.876 211.689 ;
        RECT  32.436 4.311 32.556 211.689 ;
        RECT  28.116 4.311 28.236 211.689 ;
        RECT  23.796 4.311 23.916 211.689 ;
        RECT  19.476 4.311 19.596 211.689 ;
        RECT  15.156 4.311 15.276 211.689 ;
        RECT  10.836 4.311 10.956 211.689 ;
        RECT  6.516 4.311 6.636 211.689 ;
    END
  END VDD
  PIN VSS
    DIRECTION INOUT ;
    USE GROUND ;
    PORT
      LAYER M5 ;
        RECT  79.764 4.297 79.884 211.703 ;
        RECT  75.444 4.297 75.564 211.703 ;
        RECT  71.124 4.297 71.244 211.703 ;
        RECT  66.804 4.297 66.924 211.703 ;
        RECT  62.484 4.297 62.604 211.703 ;
        RECT  58.164 4.297 58.284 211.703 ;
        RECT  53.844 4.297 53.964 211.703 ;
        RECT  49.524 4.297 49.644 211.703 ;
        RECT  45.204 4.297 45.324 211.703 ;
        RECT  40.884 4.297 41.004 211.703 ;
        RECT  36.564 4.297 36.684 211.703 ;
        RECT  32.244 4.297 32.364 211.703 ;
        RECT  27.924 4.297 28.044 211.703 ;
        RECT  23.604 4.297 23.724 211.703 ;
        RECT  19.284 4.297 19.404 211.703 ;
        RECT  14.964 4.297 15.084 211.703 ;
        RECT  10.644 4.297 10.764 211.703 ;
        RECT  6.324 4.297 6.444 211.703 ;
    END
  END VSS
  OBS
    LAYER RVTN ;
     RECT  0 2.059 86.4 216 ;
    LAYER RVTP ;
     RECT  0 2.059 86.4 216 ;
    LAYER M1 ;
     RECT  0 2.059 86.4 216 ;
    LAYER M2 ;
     RECT  0 2.059 86.4 216 ;
    LAYER M3 ;
     RECT  0 2.059 86.4 216 ;
    LAYER M4 ;
     RECT  0 2.059 86.4 216 ;
    LAYER M5 ;
     RECT  0 2.059 86.4 216 ;
  END
END dsdv_gunit_l1c
END LIBRARY
